###############################################################
#  Generated by:      Cadence Innovus 20.13-s083_1
#  OS:                Linux x86_64(Host ID iron-502-28)
#  Generated on:      Fri Apr 22 15:13:27 2022
#  Design:            user_proj_example
#  Command:           write_lef_abstract -specifyTopLayer 6 -PGPinLayers {5 6} -noCutObs -stripePin results/user_proj_example.lef
###############################################################

VERSION 5.8 ;

BUSBITCHARS "[]" ;
DIVIDERCHAR "/" ;

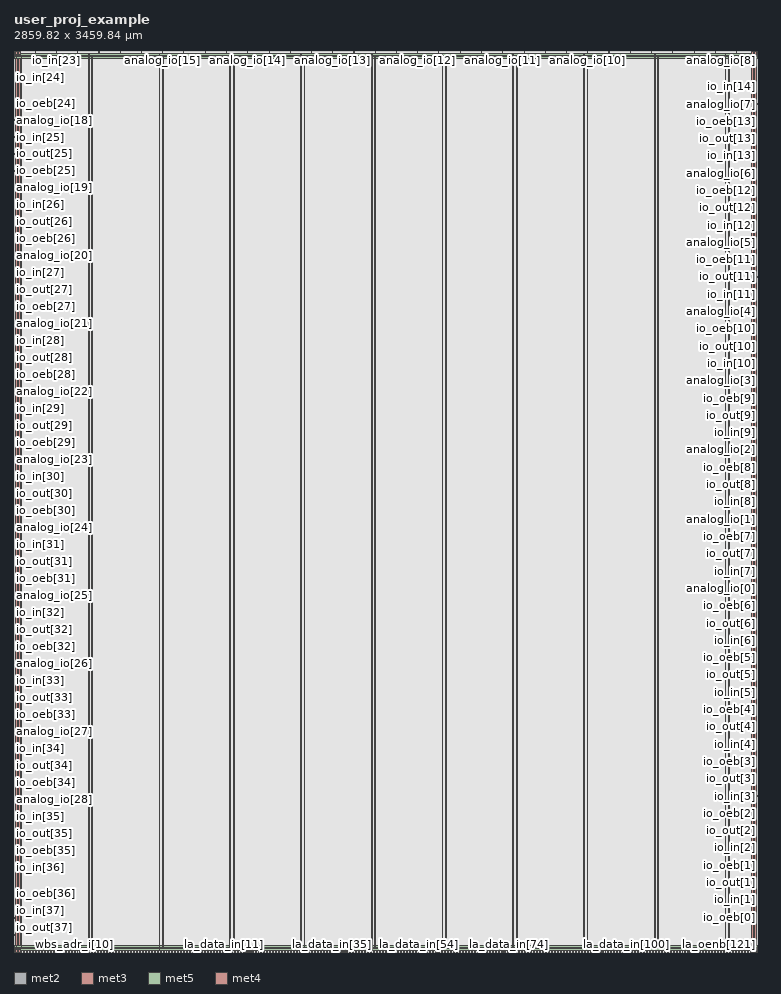
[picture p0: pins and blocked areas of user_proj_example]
MACRO user_proj_example
  CLASS BLOCK ;
  SIZE 2859.820000 BY 3459.840000 ;
  FOREIGN user_proj_example 0.000000 0.000000 ;
  ORIGIN 0 0 ;
  SYMMETRY X Y R90 ;
  PIN wb_clk_i
    DIRECTION INPUT ;
    USE SIGNAL ;
    ANTENNAPARTIALMETALAREA 4.1174 LAYER met2  ;
    ANTENNAPARTIALMETALSIDEAREA 20.426 LAYER met2  ;
    ANTENNAPARTIALCUTAREA 0.04 LAYER via2  ;
    ANTENNAPARTIALMETALAREA 8.6748 LAYER met3  ;
    ANTENNAPARTIALMETALSIDEAREA 46.736 LAYER met3  ;
    ANTENNAMODEL OXIDE1 ;
    ANTENNAGATEAREA 0.576 LAYER met3  ;
    ANTENNAMAXAREACAR 16.2276 LAYER met3  ;
    ANTENNAMAXSIDEAREACAR 83.9896 LAYER met3  ;
    ANTENNAMAXCUTCAR 0.158681 LAYER via3  ;
    PORT
      LAYER met2 ;
        RECT 0.620000 0.000000 0.760000 0.485000 ;
    END
  END wb_clk_i
  PIN wb_rst_i
    DIRECTION INPUT ;
    USE SIGNAL ;
    ANTENNAPARTIALMETALAREA 5.9323 LAYER met2  ;
    ANTENNAPARTIALMETALSIDEAREA 29.0815 LAYER met2  ;
    ANTENNAMODEL OXIDE1 ;
    ANTENNAGATEAREA 0.7425 LAYER met2  ;
    ANTENNAMAXAREACAR 10.0106 LAYER met2  ;
    ANTENNAMAXSIDEAREACAR 47.1104 LAYER met2  ;
    ANTENNAMAXCUTCAR 0.298586 LAYER via2  ;
    PORT
      LAYER met2 ;
        RECT 6.140000 0.000000 6.280000 0.485000 ;
    END
  END wb_rst_i
  PIN wbs_stb_i
    DIRECTION INPUT ;
    USE SIGNAL ;
    ANTENNAPARTIALMETALAREA 4.6987 LAYER met2  ;
    ANTENNAPARTIALMETALSIDEAREA 23.1595 LAYER met2  ;
    ANTENNAMODEL OXIDE1 ;
    ANTENNAGATEAREA 0.3735 LAYER met2  ;
    ANTENNAMAXAREACAR 17.4596 LAYER met2  ;
    ANTENNAMAXSIDEAREACAR 75.7726 LAYER met2  ;
    ANTENNAMAXCUTCAR 0.407937 LAYER via2  ;
    PORT
      LAYER met2 ;
        RECT 23.620000 0.000000 23.760000 0.485000 ;
    END
  END wbs_stb_i
  PIN wbs_cyc_i
    DIRECTION INPUT ;
    USE SIGNAL ;
    ANTENNAPARTIALMETALAREA 4.8961 LAYER met2  ;
    ANTENNAPARTIALMETALSIDEAREA 24.1465 LAYER met2  ;
    ANTENNAMODEL OXIDE1 ;
    ANTENNAGATEAREA 0.3735 LAYER met2  ;
    ANTENNAMAXAREACAR 20.2178 LAYER met2  ;
    ANTENNAMAXSIDEAREACAR 88.2643 LAYER met2  ;
    ANTENNAMAXCUTCAR 0.407937 LAYER via2  ;
    PORT
      LAYER met2 ;
        RECT 17.640000 0.000000 17.780000 0.485000 ;
    END
  END wbs_cyc_i
  PIN wbs_we_i
    DIRECTION INPUT ;
    USE SIGNAL ;
    ANTENNAPARTIALMETALAREA 5.2293 LAYER met2  ;
    ANTENNAPARTIALMETALSIDEAREA 25.8125 LAYER met2  ;
    ANTENNAMODEL OXIDE1 ;
    ANTENNAGATEAREA 0.3735 LAYER met2  ;
    ANTENNAMAXAREACAR 18.0833 LAYER met2  ;
    ANTENNAMAXSIDEAREACAR 79.3756 LAYER met2  ;
    ANTENNAMAXCUTCAR 0.407937 LAYER via2  ;
    PORT
      LAYER met2 ;
        RECT 29.600000 0.000000 29.740000 0.485000 ;
    END
  END wbs_we_i
  PIN wbs_sel_i[3]
    DIRECTION INPUT ;
    USE SIGNAL ;
    PORT
      LAYER met2 ;
        RECT 122.060000 0.000000 122.200000 0.485000 ;
    END
  END wbs_sel_i[3]
  PIN wbs_sel_i[2]
    DIRECTION INPUT ;
    USE SIGNAL ;
    PORT
      LAYER met2 ;
        RECT 99.060000 0.000000 99.200000 0.485000 ;
    END
  END wbs_sel_i[2]
  PIN wbs_sel_i[1]
    DIRECTION INPUT ;
    USE SIGNAL ;
    PORT
      LAYER met2 ;
        RECT 75.600000 0.000000 75.740000 0.485000 ;
    END
  END wbs_sel_i[1]
  PIN wbs_sel_i[0]
    DIRECTION INPUT ;
    USE SIGNAL ;
    PORT
      LAYER met2 ;
        RECT 52.600000 0.000000 52.740000 0.485000 ;
    END
  END wbs_sel_i[0]
  PIN wbs_dat_i[31]
    DIRECTION INPUT ;
    USE SIGNAL ;
    ANTENNAPARTIALMETALAREA 4.4991 LAYER met2  ;
    ANTENNAPARTIALMETALSIDEAREA 22.1515 LAYER met2  ;
    ANTENNAMODEL OXIDE1 ;
    ANTENNAGATEAREA 0.246 LAYER met2  ;
    ANTENNAMAXAREACAR 24.7075 LAYER met2  ;
    ANTENNAMAXSIDEAREACAR 120.012 LAYER met2  ;
    ANTENNAMAXCUTCAR 0.208943 LAYER via2  ;
    PORT
      LAYER met2 ;
        RECT 603.680000 0.000000 603.820000 0.485000 ;
    END
  END wbs_dat_i[31]
  PIN wbs_dat_i[30]
    DIRECTION INPUT ;
    USE SIGNAL ;
    ANTENNAPARTIALMETALAREA 5.0816 LAYER met2  ;
    ANTENNAPARTIALMETALSIDEAREA 25.102 LAYER met2  ;
    ANTENNAPARTIALCUTAREA 0.04 LAYER via2  ;
    ANTENNAPARTIALMETALAREA 2.8788 LAYER met3  ;
    ANTENNAPARTIALMETALSIDEAREA 15.824 LAYER met3  ;
    ANTENNAMODEL OXIDE1 ;
    ANTENNAGATEAREA 0.246 LAYER met3  ;
    ANTENNAMAXAREACAR 13.4085 LAYER met3  ;
    ANTENNAMAXSIDEAREACAR 69.8049 LAYER met3  ;
    ANTENNAMAXCUTCAR 0.371545 LAYER via3  ;
    PORT
      LAYER met2 ;
        RECT 586.200000 0.000000 586.340000 0.485000 ;
    END
  END wbs_dat_i[30]
  PIN wbs_dat_i[29]
    DIRECTION INPUT ;
    USE SIGNAL ;
    ANTENNAPARTIALMETALAREA 4.8799 LAYER met2  ;
    ANTENNAPARTIALMETALSIDEAREA 24.0555 LAYER met2  ;
    ANTENNAMODEL OXIDE1 ;
    ANTENNAGATEAREA 0.246 LAYER met2  ;
    ANTENNAMAXAREACAR 22.6587 LAYER met2  ;
    ANTENNAMAXSIDEAREACAR 109.768 LAYER met2  ;
    ANTENNAMAXCUTCAR 0.208943 LAYER via2  ;
    PORT
      LAYER met2 ;
        RECT 568.720000 0.000000 568.860000 0.485000 ;
    END
  END wbs_dat_i[29]
  PIN wbs_dat_i[28]
    DIRECTION INPUT ;
    USE SIGNAL ;
    ANTENNAPARTIALMETALAREA 4.9935 LAYER met2  ;
    ANTENNAPARTIALMETALSIDEAREA 24.7415 LAYER met2  ;
    ANTENNAMODEL OXIDE1 ;
    ANTENNAGATEAREA 0.246 LAYER met2  ;
    ANTENNAMAXAREACAR 21.3459 LAYER met2  ;
    ANTENNAMAXSIDEAREACAR 103.565 LAYER met2  ;
    ANTENNAMAXCUTCAR 0.208943 LAYER via2  ;
    PORT
      LAYER met2 ;
        RECT 551.240000 0.000000 551.380000 0.485000 ;
    END
  END wbs_dat_i[28]
  PIN wbs_dat_i[27]
    DIRECTION INPUT ;
    USE SIGNAL ;
    ANTENNAPARTIALMETALAREA 4.2837 LAYER met2  ;
    ANTENNAPARTIALMETALSIDEAREA 21.1925 LAYER met2  ;
    ANTENNAMODEL OXIDE1 ;
    ANTENNAGATEAREA 0.246 LAYER met2  ;
    ANTENNAMAXAREACAR 18.4606 LAYER met2  ;
    ANTENNAMAXSIDEAREACAR 89.1382 LAYER met2  ;
    ANTENNAMAXCUTCAR 0.208943 LAYER via2  ;
    PORT
      LAYER met2 ;
        RECT 533.760000 0.000000 533.900000 0.485000 ;
    END
  END wbs_dat_i[27]
  PIN wbs_dat_i[26]
    DIRECTION INPUT ;
    USE SIGNAL ;
    ANTENNAPARTIALMETALAREA 4.3271 LAYER met2  ;
    ANTENNAPARTIALMETALSIDEAREA 21.4095 LAYER met2  ;
    ANTENNAMODEL OXIDE1 ;
    ANTENNAGATEAREA 0.246 LAYER met2  ;
    ANTENNAMAXAREACAR 18.637 LAYER met2  ;
    ANTENNAMAXSIDEAREACAR 90.0203 LAYER met2  ;
    ANTENNAMAXCUTCAR 0.208943 LAYER via2  ;
    PORT
      LAYER met2 ;
        RECT 516.740000 0.000000 516.880000 0.485000 ;
    END
  END wbs_dat_i[26]
  PIN wbs_dat_i[25]
    DIRECTION INPUT ;
    USE SIGNAL ;
    ANTENNAPARTIALMETALAREA 4.1367 LAYER met2  ;
    ANTENNAPARTIALMETALSIDEAREA 20.4575 LAYER met2  ;
    ANTENNAMODEL OXIDE1 ;
    ANTENNAGATEAREA 0.246 LAYER met2  ;
    ANTENNAMAXAREACAR 17.863 LAYER met2  ;
    ANTENNAMAXSIDEAREACAR 86.1504 LAYER met2  ;
    ANTENNAMAXCUTCAR 0.208943 LAYER via2  ;
    PORT
      LAYER met2 ;
        RECT 499.260000 0.000000 499.400000 0.485000 ;
    END
  END wbs_dat_i[25]
  PIN wbs_dat_i[24]
    DIRECTION INPUT ;
    USE SIGNAL ;
    ANTENNAPARTIALMETALAREA 4.2319 LAYER met2  ;
    ANTENNAPARTIALMETALSIDEAREA 20.9335 LAYER met2  ;
    ANTENNAMODEL OXIDE1 ;
    ANTENNAGATEAREA 0.246 LAYER met2  ;
    ANTENNAMAXAREACAR 18.25 LAYER met2  ;
    ANTENNAMAXSIDEAREACAR 88.0854 LAYER met2  ;
    ANTENNAMAXCUTCAR 0.208943 LAYER via2  ;
    PORT
      LAYER met2 ;
        RECT 481.780000 0.000000 481.920000 0.485000 ;
    END
  END wbs_dat_i[24]
  PIN wbs_dat_i[23]
    DIRECTION INPUT ;
    USE SIGNAL ;
    ANTENNAPARTIALMETALAREA 4.4769 LAYER met2  ;
    ANTENNAPARTIALMETALSIDEAREA 22.1585 LAYER met2  ;
    ANTENNAMODEL OXIDE1 ;
    ANTENNAGATEAREA 0.246 LAYER met2  ;
    ANTENNAMAXAREACAR 19.2459 LAYER met2  ;
    ANTENNAMAXSIDEAREACAR 93.065 LAYER met2  ;
    ANTENNAMAXCUTCAR 0.208943 LAYER via2  ;
    PORT
      LAYER met2 ;
        RECT 464.300000 0.000000 464.440000 0.485000 ;
    END
  END wbs_dat_i[23]
  PIN wbs_dat_i[22]
    DIRECTION INPUT ;
    USE SIGNAL ;
    ANTENNAPARTIALMETALAREA 4.2319 LAYER met2  ;
    ANTENNAPARTIALMETALSIDEAREA 20.9335 LAYER met2  ;
    ANTENNAMODEL OXIDE1 ;
    ANTENNAGATEAREA 0.246 LAYER met2  ;
    ANTENNAMAXAREACAR 18.25 LAYER met2  ;
    ANTENNAMAXSIDEAREACAR 88.0854 LAYER met2  ;
    ANTENNAMAXCUTCAR 0.208943 LAYER via2  ;
    PORT
      LAYER met2 ;
        RECT 446.820000 0.000000 446.960000 0.485000 ;
    END
  END wbs_dat_i[22]
  PIN wbs_dat_i[21]
    DIRECTION INPUT ;
    USE SIGNAL ;
    ANTENNAPARTIALMETALAREA 4.3481 LAYER met2  ;
    ANTENNAPARTIALMETALSIDEAREA 21.5145 LAYER met2  ;
    ANTENNAMODEL OXIDE1 ;
    ANTENNAGATEAREA 0.246 LAYER met2  ;
    ANTENNAMAXAREACAR 18.7224 LAYER met2  ;
    ANTENNAMAXSIDEAREACAR 90.4472 LAYER met2  ;
    ANTENNAMAXCUTCAR 0.208943 LAYER via2  ;
    PORT
      LAYER met2 ;
        RECT 429.800000 0.000000 429.940000 0.485000 ;
    END
  END wbs_dat_i[21]
  PIN wbs_dat_i[20]
    DIRECTION INPUT ;
    USE SIGNAL ;
    ANTENNAPARTIALMETALAREA 4.5987 LAYER met2  ;
    ANTENNAPARTIALMETALSIDEAREA 22.7675 LAYER met2  ;
    ANTENNAMODEL OXIDE1 ;
    ANTENNAGATEAREA 0.246 LAYER met2  ;
    ANTENNAMAXAREACAR 20.9238 LAYER met2  ;
    ANTENNAMAXSIDEAREACAR 101.573 LAYER met2  ;
    ANTENNAMAXCUTCAR 0.208943 LAYER via2  ;
    PORT
      LAYER met2 ;
        RECT 412.320000 0.000000 412.460000 0.485000 ;
    END
  END wbs_dat_i[20]
  PIN wbs_dat_i[19]
    DIRECTION INPUT ;
    USE SIGNAL ;
    ANTENNAPARTIALMETALAREA 4.2795 LAYER met2  ;
    ANTENNAPARTIALMETALSIDEAREA 21.1715 LAYER met2  ;
    ANTENNAMODEL OXIDE1 ;
    ANTENNAGATEAREA 0.246 LAYER met2  ;
    ANTENNAMAXAREACAR 18.4435 LAYER met2  ;
    ANTENNAMAXSIDEAREACAR 89.0528 LAYER met2  ;
    ANTENNAMAXCUTCAR 0.208943 LAYER via2  ;
    PORT
      LAYER met2 ;
        RECT 394.840000 0.000000 394.980000 0.485000 ;
    END
  END wbs_dat_i[19]
  PIN wbs_dat_i[18]
    DIRECTION INPUT ;
    USE SIGNAL ;
    ANTENNAPARTIALMETALAREA 4.4293 LAYER met2  ;
    ANTENNAPARTIALMETALSIDEAREA 21.9205 LAYER met2  ;
    ANTENNAMODEL OXIDE1 ;
    ANTENNAGATEAREA 0.246 LAYER met2  ;
    ANTENNAMAXAREACAR 19.0524 LAYER met2  ;
    ANTENNAMAXSIDEAREACAR 92.0976 LAYER met2  ;
    ANTENNAMAXCUTCAR 0.208943 LAYER via2  ;
    PORT
      LAYER met2 ;
        RECT 377.360000 0.000000 377.500000 0.485000 ;
    END
  END wbs_dat_i[18]
  PIN wbs_dat_i[17]
    DIRECTION INPUT ;
    USE SIGNAL ;
    ANTENNAPARTIALMETALAREA 5.2385 LAYER met2  ;
    ANTENNAPARTIALMETALSIDEAREA 25.9665 LAYER met2  ;
    ANTENNAMODEL OXIDE1 ;
    ANTENNAGATEAREA 0.246 LAYER met2  ;
    ANTENNAMAXAREACAR 22.3419 LAYER met2  ;
    ANTENNAMAXSIDEAREACAR 108.545 LAYER met2  ;
    ANTENNAMAXCUTCAR 0.208943 LAYER via2  ;
    PORT
      LAYER met2 ;
        RECT 359.880000 0.000000 360.020000 0.485000 ;
    END
  END wbs_dat_i[17]
  PIN wbs_dat_i[16]
    DIRECTION INPUT ;
    USE SIGNAL ;
    ANTENNAPARTIALMETALAREA 4.3649 LAYER met2  ;
    ANTENNAPARTIALMETALSIDEAREA 21.5985 LAYER met2  ;
    ANTENNAMODEL OXIDE1 ;
    ANTENNAGATEAREA 0.246 LAYER met2  ;
    ANTENNAMAXAREACAR 18.7907 LAYER met2  ;
    ANTENNAMAXSIDEAREACAR 90.7886 LAYER met2  ;
    ANTENNAMAXCUTCAR 0.208943 LAYER via2  ;
    PORT
      LAYER met2 ;
        RECT 342.400000 0.000000 342.540000 0.485000 ;
    END
  END wbs_dat_i[16]
  PIN wbs_dat_i[15]
    DIRECTION INPUT ;
    USE SIGNAL ;
    ANTENNAPARTIALMETALAREA 5.3984 LAYER met2  ;
    ANTENNAPARTIALMETALSIDEAREA 26.831 LAYER met2  ;
    ANTENNAPARTIALCUTAREA 0.04 LAYER via2  ;
    ANTENNAPARTIALMETALAREA 15.028 LAYER met3  ;
    ANTENNAPARTIALMETALSIDEAREA 80.616 LAYER met3  ;
    ANTENNAPARTIALCUTAREA 0.04 LAYER via3  ;
    ANTENNAPARTIALMETALAREA 0.6516 LAYER met4  ;
    ANTENNAPARTIALMETALSIDEAREA 4.416 LAYER met4  ;
    ANTENNAMODEL OXIDE1 ;
    ANTENNAGATEAREA 0.2475 LAYER met4  ;
    ANTENNAMAXAREACAR 6.16909 LAYER met4  ;
    ANTENNAMAXSIDEAREACAR 35.2768 LAYER met4  ;
    ANTENNAMAXCUTCAR 0.530909 LAYER via4  ;
    PORT
      LAYER met2 ;
        RECT 325.380000 0.000000 325.520000 0.485000 ;
    END
  END wbs_dat_i[15]
  PIN wbs_dat_i[14]
    DIRECTION INPUT ;
    USE SIGNAL ;
    ANTENNAPARTIALMETALAREA 5.5717 LAYER met2  ;
    ANTENNAPARTIALMETALSIDEAREA 27.6325 LAYER met2  ;
    ANTENNAMODEL OXIDE1 ;
    ANTENNAGATEAREA 0.2475 LAYER met2  ;
    ANTENNAMAXAREACAR 26.2616 LAYER met2  ;
    ANTENNAMAXSIDEAREACAR 128.133 LAYER met2  ;
    ANTENNAMAXCUTCAR 0.207677 LAYER via2  ;
    PORT
      LAYER met2 ;
        RECT 307.900000 0.000000 308.040000 0.485000 ;
    END
  END wbs_dat_i[14]
  PIN wbs_dat_i[13]
    DIRECTION INPUT ;
    USE SIGNAL ;
    ANTENNAPARTIALMETALAREA 5.8027 LAYER met2  ;
    ANTENNAPARTIALMETALSIDEAREA 28.7875 LAYER met2  ;
    ANTENNAMODEL OXIDE1 ;
    ANTENNAGATEAREA 0.2475 LAYER met2  ;
    ANTENNAMAXAREACAR 24.4422 LAYER met2  ;
    ANTENNAMAXSIDEAREACAR 119.309 LAYER met2  ;
    ANTENNAMAXCUTCAR 0.207677 LAYER via2  ;
    PORT
      LAYER met2 ;
        RECT 290.420000 0.000000 290.560000 0.485000 ;
    END
  END wbs_dat_i[13]
  PIN wbs_dat_i[12]
    DIRECTION INPUT ;
    USE SIGNAL ;
    ANTENNAPARTIALMETALAREA 1.3846 LAYER met2  ;
    ANTENNAPARTIALMETALSIDEAREA 6.762 LAYER met2  ;
    ANTENNAPARTIALCUTAREA 0.04 LAYER via2  ;
    ANTENNAPARTIALMETALAREA 3.7068 LAYER met3  ;
    ANTENNAPARTIALMETALSIDEAREA 20.24 LAYER met3  ;
    ANTENNAMODEL OXIDE1 ;
    ANTENNAGATEAREA 0.2475 LAYER met3  ;
    ANTENNAMAXAREACAR 32.7715 LAYER met3  ;
    ANTENNAMAXSIDEAREACAR 167.798 LAYER met3  ;
    ANTENNAMAXCUTCAR 0.369293 LAYER via3  ;
    PORT
      LAYER met2 ;
        RECT 272.940000 0.000000 273.080000 0.485000 ;
    END
  END wbs_dat_i[12]
  PIN wbs_dat_i[11]
    DIRECTION INPUT ;
    USE SIGNAL ;
    ANTENNAPARTIALMETALAREA 5.4767 LAYER met2  ;
    ANTENNAPARTIALMETALSIDEAREA 27.2755 LAYER met2  ;
    ANTENNAMODEL OXIDE1 ;
    ANTENNAGATEAREA 0.2475 LAYER met2  ;
    ANTENNAMAXAREACAR 23.5869 LAYER met2  ;
    ANTENNAMAXSIDEAREACAR 115.236 LAYER met2  ;
    ANTENNAMAXCUTCAR 0.207677 LAYER via2  ;
    PORT
      LAYER met2 ;
        RECT 255.460000 0.000000 255.600000 0.485000 ;
    END
  END wbs_dat_i[11]
  PIN wbs_dat_i[10]
    DIRECTION INPUT ;
    USE SIGNAL ;
    ANTENNAPARTIALMETALAREA 4.5863 LAYER met2  ;
    ANTENNAPARTIALMETALSIDEAREA 22.8235 LAYER met2  ;
    ANTENNAMODEL OXIDE1 ;
    ANTENNAGATEAREA 0.2475 LAYER met2  ;
    ANTENNAMAXAREACAR 19.5275 LAYER met2  ;
    ANTENNAMAXSIDEAREACAR 95.2121 LAYER met2  ;
    ANTENNAMAXCUTCAR 0.207677 LAYER via2  ;
    PORT
      LAYER met2 ;
        RECT 237.980000 0.000000 238.120000 0.485000 ;
    END
  END wbs_dat_i[10]
  PIN wbs_dat_i[9]
    DIRECTION INPUT ;
    USE SIGNAL ;
    ANTENNAPARTIALMETALAREA 5.4459 LAYER met2  ;
    ANTENNAPARTIALMETALSIDEAREA 27.1215 LAYER met2  ;
    ANTENNAMODEL OXIDE1 ;
    ANTENNAGATEAREA 0.2475 LAYER met2  ;
    ANTENNAMAXAREACAR 28.0103 LAYER met2  ;
    ANTENNAMAXSIDEAREACAR 137.354 LAYER met2  ;
    ANTENNAMAXCUTCAR 0.207677 LAYER via2  ;
    PORT
      LAYER met2 ;
        RECT 220.960000 0.000000 221.100000 0.485000 ;
    END
  END wbs_dat_i[9]
  PIN wbs_dat_i[8]
    DIRECTION INPUT ;
    USE SIGNAL ;
    ANTENNAPARTIALMETALAREA 5.8237 LAYER met2  ;
    ANTENNAPARTIALMETALSIDEAREA 28.8925 LAYER met2  ;
    ANTENNAMODEL OXIDE1 ;
    ANTENNAGATEAREA 0.2475 LAYER met2  ;
    ANTENNAMAXAREACAR 30.5097 LAYER met2  ;
    ANTENNAMAXSIDEAREACAR 149.374 LAYER met2  ;
    ANTENNAMAXCUTCAR 0.207677 LAYER via2  ;
    PORT
      LAYER met2 ;
        RECT 203.480000 0.000000 203.620000 0.485000 ;
    END
  END wbs_dat_i[8]
  PIN wbs_dat_i[7]
    DIRECTION INPUT ;
    USE SIGNAL ;
    ANTENNAPARTIALMETALAREA 6.432 LAYER met2  ;
    ANTENNAPARTIALMETALSIDEAREA 31.934 LAYER met2  ;
    ANTENNAMODEL OXIDE1 ;
    ANTENNAGATEAREA 0.2475 LAYER met2  ;
    ANTENNAMAXAREACAR 27.9105 LAYER met2  ;
    ANTENNAMAXSIDEAREACAR 136.378 LAYER met2  ;
    ANTENNAMAXCUTCAR 0.207677 LAYER via2  ;
    PORT
      LAYER met2 ;
        RECT 186.000000 0.000000 186.140000 0.485000 ;
    END
  END wbs_dat_i[7]
  PIN wbs_dat_i[6]
    DIRECTION INPUT ;
    USE SIGNAL ;
    ANTENNAPARTIALMETALAREA 5.7551 LAYER met2  ;
    ANTENNAPARTIALMETALSIDEAREA 28.5495 LAYER met2  ;
    ANTENNAMODEL OXIDE1 ;
    ANTENNAGATEAREA 0.2475 LAYER met2  ;
    ANTENNAMAXAREACAR 26.4653 LAYER met2  ;
    ANTENNAMAXSIDEAREACAR 129.152 LAYER met2  ;
    ANTENNAMAXCUTCAR 0.207677 LAYER via2  ;
    PORT
      LAYER met2 ;
        RECT 168.520000 0.000000 168.660000 0.485000 ;
    END
  END wbs_dat_i[6]
  PIN wbs_dat_i[5]
    DIRECTION INPUT ;
    USE SIGNAL ;
    ANTENNAPARTIALMETALAREA 5.7957 LAYER met2  ;
    ANTENNAPARTIALMETALSIDEAREA 28.7525 LAYER met2  ;
    ANTENNAMODEL OXIDE1 ;
    ANTENNAGATEAREA 0.2475 LAYER met2  ;
    ANTENNAMAXAREACAR 24.4139 LAYER met2  ;
    ANTENNAMAXSIDEAREACAR 119.168 LAYER met2  ;
    ANTENNAMAXCUTCAR 0.207677 LAYER via2  ;
    PORT
      LAYER met2 ;
        RECT 151.040000 0.000000 151.180000 0.485000 ;
    END
  END wbs_dat_i[5]
  PIN wbs_dat_i[4]
    DIRECTION INPUT ;
    USE SIGNAL ;
    ANTENNAPARTIALMETALAREA 4.7079 LAYER met2  ;
    ANTENNAPARTIALMETALSIDEAREA 23.3135 LAYER met2  ;
    ANTENNAMODEL OXIDE1 ;
    ANTENNAGATEAREA 0.2475 LAYER met2  ;
    ANTENNAMAXAREACAR 20.2204 LAYER met2  ;
    ANTENNAMAXSIDEAREACAR 97.9273 LAYER met2  ;
    ANTENNAMAXCUTCAR 0.207677 LAYER via2  ;
    PORT
      LAYER met2 ;
        RECT 133.560000 0.000000 133.700000 0.485000 ;
    END
  END wbs_dat_i[4]
  PIN wbs_dat_i[3]
    DIRECTION INPUT ;
    USE SIGNAL ;
    ANTENNAPARTIALMETALAREA 3.115 LAYER met2  ;
    ANTENNAPARTIALMETALSIDEAREA 15.414 LAYER met2  ;
    ANTENNAPARTIALCUTAREA 0.04 LAYER via2  ;
    ANTENNAPARTIALMETALAREA 22.618 LAYER met3  ;
    ANTENNAPARTIALMETALSIDEAREA 121.096 LAYER met3  ;
    ANTENNAPARTIALCUTAREA 0.04 LAYER via3  ;
    ANTENNAPARTIALMETALAREA 5.2428 LAYER met4  ;
    ANTENNAPARTIALMETALSIDEAREA 28.432 LAYER met4  ;
    ANTENNAMODEL OXIDE1 ;
    ANTENNAGATEAREA 0.2475 LAYER met4  ;
    ANTENNAMAXAREACAR 24.6051 LAYER met4  ;
    ANTENNAMAXSIDEAREACAR 131.192 LAYER met4  ;
    ANTENNAMAXCUTCAR 0.530909 LAYER via4  ;
    PORT
      LAYER met2 ;
        RECT 110.560000 0.000000 110.700000 0.485000 ;
    END
  END wbs_dat_i[3]
  PIN wbs_dat_i[2]
    DIRECTION INPUT ;
    USE SIGNAL ;
    ANTENNAPARTIALMETALAREA 5.3003 LAYER met2  ;
    ANTENNAPARTIALMETALSIDEAREA 26.3935 LAYER met2  ;
    ANTENNAMODEL OXIDE1 ;
    ANTENNAGATEAREA 0.2475 LAYER met2  ;
    ANTENNAMAXAREACAR 67.9626 LAYER met2  ;
    ANTENNAMAXSIDEAREACAR 337.115 LAYER met2  ;
    ANTENNAMAXCUTCAR 0.207677 LAYER via2  ;
    PORT
      LAYER met2 ;
        RECT 87.560000 0.000000 87.700000 0.485000 ;
    END
  END wbs_dat_i[2]
  PIN wbs_dat_i[1]
    DIRECTION INPUT ;
    USE SIGNAL ;
    ANTENNAPARTIALMETALAREA 4.6603 LAYER met2  ;
    ANTENNAPARTIALMETALSIDEAREA 23.0755 LAYER met2  ;
    ANTENNAMODEL OXIDE1 ;
    ANTENNAGATEAREA 0.2475 LAYER met2  ;
    ANTENNAMAXAREACAR 20.2883 LAYER met2  ;
    ANTENNAMAXSIDEAREACAR 98.2667 LAYER met2  ;
    ANTENNAMAXCUTCAR 0.207677 LAYER via2  ;
    PORT
      LAYER met2 ;
        RECT 64.100000 0.000000 64.240000 0.485000 ;
    END
  END wbs_dat_i[1]
  PIN wbs_dat_i[0]
    DIRECTION INPUT ;
    USE SIGNAL ;
    ANTENNAPARTIALMETALAREA 4.5651 LAYER met2  ;
    ANTENNAPARTIALMETALSIDEAREA 22.5995 LAYER met2  ;
    ANTENNAMODEL OXIDE1 ;
    ANTENNAGATEAREA 0.2475 LAYER met2  ;
    ANTENNAMAXAREACAR 24.3271 LAYER met2  ;
    ANTENNAMAXSIDEAREACAR 118.461 LAYER met2  ;
    ANTENNAMAXCUTCAR 0.207677 LAYER via2  ;
    PORT
      LAYER met2 ;
        RECT 41.100000 0.000000 41.240000 0.485000 ;
    END
  END wbs_dat_i[0]
  PIN wbs_adr_i[31]
    DIRECTION INPUT ;
    USE SIGNAL ;
    PORT
      LAYER met2 ;
        RECT 597.700000 0.000000 597.840000 0.485000 ;
    END
  END wbs_adr_i[31]
  PIN wbs_adr_i[30]
    DIRECTION INPUT ;
    USE SIGNAL ;
    PORT
      LAYER met2 ;
        RECT 580.220000 0.000000 580.360000 0.485000 ;
    END
  END wbs_adr_i[30]
  PIN wbs_adr_i[29]
    DIRECTION INPUT ;
    USE SIGNAL ;
    PORT
      LAYER met2 ;
        RECT 563.200000 0.000000 563.340000 0.485000 ;
    END
  END wbs_adr_i[29]
  PIN wbs_adr_i[28]
    DIRECTION INPUT ;
    USE SIGNAL ;
    PORT
      LAYER met2 ;
        RECT 545.720000 0.000000 545.860000 0.485000 ;
    END
  END wbs_adr_i[28]
  PIN wbs_adr_i[27]
    DIRECTION INPUT ;
    USE SIGNAL ;
    PORT
      LAYER met2 ;
        RECT 528.240000 0.000000 528.380000 0.485000 ;
    END
  END wbs_adr_i[27]
  PIN wbs_adr_i[26]
    DIRECTION INPUT ;
    USE SIGNAL ;
    PORT
      LAYER met2 ;
        RECT 510.760000 0.000000 510.900000 0.485000 ;
    END
  END wbs_adr_i[26]
  PIN wbs_adr_i[25]
    DIRECTION INPUT ;
    USE SIGNAL ;
    PORT
      LAYER met2 ;
        RECT 493.280000 0.000000 493.420000 0.485000 ;
    END
  END wbs_adr_i[25]
  PIN wbs_adr_i[24]
    DIRECTION INPUT ;
    USE SIGNAL ;
    PORT
      LAYER met2 ;
        RECT 475.800000 0.000000 475.940000 0.485000 ;
    END
  END wbs_adr_i[24]
  PIN wbs_adr_i[23]
    DIRECTION INPUT ;
    USE SIGNAL ;
    PORT
      LAYER met2 ;
        RECT 458.780000 0.000000 458.920000 0.485000 ;
    END
  END wbs_adr_i[23]
  PIN wbs_adr_i[22]
    DIRECTION INPUT ;
    USE SIGNAL ;
    PORT
      LAYER met2 ;
        RECT 441.300000 0.000000 441.440000 0.485000 ;
    END
  END wbs_adr_i[22]
  PIN wbs_adr_i[21]
    DIRECTION INPUT ;
    USE SIGNAL ;
    PORT
      LAYER met2 ;
        RECT 423.820000 0.000000 423.960000 0.485000 ;
    END
  END wbs_adr_i[21]
  PIN wbs_adr_i[20]
    DIRECTION INPUT ;
    USE SIGNAL ;
    PORT
      LAYER met2 ;
        RECT 406.340000 0.000000 406.480000 0.485000 ;
    END
  END wbs_adr_i[20]
  PIN wbs_adr_i[19]
    DIRECTION INPUT ;
    USE SIGNAL ;
    PORT
      LAYER met2 ;
        RECT 388.860000 0.000000 389.000000 0.485000 ;
    END
  END wbs_adr_i[19]
  PIN wbs_adr_i[18]
    DIRECTION INPUT ;
    USE SIGNAL ;
    PORT
      LAYER met2 ;
        RECT 371.380000 0.000000 371.520000 0.485000 ;
    END
  END wbs_adr_i[18]
  PIN wbs_adr_i[17]
    DIRECTION INPUT ;
    USE SIGNAL ;
    PORT
      LAYER met2 ;
        RECT 354.360000 0.000000 354.500000 0.485000 ;
    END
  END wbs_adr_i[17]
  PIN wbs_adr_i[16]
    DIRECTION INPUT ;
    USE SIGNAL ;
    PORT
      LAYER met2 ;
        RECT 336.880000 0.000000 337.020000 0.485000 ;
    END
  END wbs_adr_i[16]
  PIN wbs_adr_i[15]
    DIRECTION INPUT ;
    USE SIGNAL ;
    PORT
      LAYER met2 ;
        RECT 319.400000 0.000000 319.540000 0.485000 ;
    END
  END wbs_adr_i[15]
  PIN wbs_adr_i[14]
    DIRECTION INPUT ;
    USE SIGNAL ;
    PORT
      LAYER met2 ;
        RECT 301.920000 0.000000 302.060000 0.485000 ;
    END
  END wbs_adr_i[14]
  PIN wbs_adr_i[13]
    DIRECTION INPUT ;
    USE SIGNAL ;
    PORT
      LAYER met2 ;
        RECT 284.440000 0.000000 284.580000 0.485000 ;
    END
  END wbs_adr_i[13]
  PIN wbs_adr_i[12]
    DIRECTION INPUT ;
    USE SIGNAL ;
    PORT
      LAYER met2 ;
        RECT 266.960000 0.000000 267.100000 0.485000 ;
    END
  END wbs_adr_i[12]
  PIN wbs_adr_i[11]
    DIRECTION INPUT ;
    USE SIGNAL ;
    PORT
      LAYER met2 ;
        RECT 249.940000 0.000000 250.080000 0.485000 ;
    END
  END wbs_adr_i[11]
  PIN wbs_adr_i[10]
    DIRECTION INPUT ;
    USE SIGNAL ;
    PORT
      LAYER met2 ;
        RECT 232.460000 0.000000 232.600000 0.485000 ;
    END
  END wbs_adr_i[10]
  PIN wbs_adr_i[9]
    DIRECTION INPUT ;
    USE SIGNAL ;
    PORT
      LAYER met2 ;
        RECT 214.980000 0.000000 215.120000 0.485000 ;
    END
  END wbs_adr_i[9]
  PIN wbs_adr_i[8]
    DIRECTION INPUT ;
    USE SIGNAL ;
    PORT
      LAYER met2 ;
        RECT 197.500000 0.000000 197.640000 0.485000 ;
    END
  END wbs_adr_i[8]
  PIN wbs_adr_i[7]
    DIRECTION INPUT ;
    USE SIGNAL ;
    PORT
      LAYER met2 ;
        RECT 180.020000 0.000000 180.160000 0.485000 ;
    END
  END wbs_adr_i[7]
  PIN wbs_adr_i[6]
    DIRECTION INPUT ;
    USE SIGNAL ;
    PORT
      LAYER met2 ;
        RECT 163.000000 0.000000 163.140000 0.485000 ;
    END
  END wbs_adr_i[6]
  PIN wbs_adr_i[5]
    DIRECTION INPUT ;
    USE SIGNAL ;
    PORT
      LAYER met2 ;
        RECT 145.520000 0.000000 145.660000 0.485000 ;
    END
  END wbs_adr_i[5]
  PIN wbs_adr_i[4]
    DIRECTION INPUT ;
    USE SIGNAL ;
    PORT
      LAYER met2 ;
        RECT 128.040000 0.000000 128.180000 0.485000 ;
    END
  END wbs_adr_i[4]
  PIN wbs_adr_i[3]
    DIRECTION INPUT ;
    USE SIGNAL ;
    PORT
      LAYER met2 ;
        RECT 104.580000 0.000000 104.720000 0.485000 ;
    END
  END wbs_adr_i[3]
  PIN wbs_adr_i[2]
    DIRECTION INPUT ;
    USE SIGNAL ;
    PORT
      LAYER met2 ;
        RECT 81.580000 0.000000 81.720000 0.485000 ;
    END
  END wbs_adr_i[2]
  PIN wbs_adr_i[1]
    DIRECTION INPUT ;
    USE SIGNAL ;
    PORT
      LAYER met2 ;
        RECT 58.580000 0.000000 58.720000 0.485000 ;
    END
  END wbs_adr_i[1]
  PIN wbs_adr_i[0]
    DIRECTION INPUT ;
    USE SIGNAL ;
    PORT
      LAYER met2 ;
        RECT 35.120000 0.000000 35.260000 0.485000 ;
    END
  END wbs_adr_i[0]
  PIN wbs_ack_o
    DIRECTION OUTPUT ;
    USE SIGNAL ;
    ANTENNADIFFAREA 0.429 LAYER met2  ;
    ANTENNAPARTIALMETALAREA 4.5651 LAYER met2  ;
    ANTENNAPARTIALMETALSIDEAREA 22.5995 LAYER met2  ;
    PORT
      LAYER met2 ;
        RECT 12.120000 0.000000 12.260000 0.485000 ;
    END
  END wbs_ack_o
  PIN wbs_dat_o[31]
    DIRECTION OUTPUT ;
    USE SIGNAL ;
    ANTENNADIFFAREA 0.336 LAYER met2  ;
    ANTENNAPARTIALMETALAREA 4.0627 LAYER met2  ;
    ANTENNAPARTIALMETALSIDEAREA 20.2055 LAYER met2  ;
    PORT
      LAYER met2 ;
        RECT 609.200000 0.000000 609.340000 0.485000 ;
    END
  END wbs_dat_o[31]
  PIN wbs_dat_o[30]
    DIRECTION OUTPUT ;
    USE SIGNAL ;
    ANTENNADIFFAREA 0.336 LAYER met2  ;
    ANTENNAPARTIALMETALAREA 4.0627 LAYER met2  ;
    ANTENNAPARTIALMETALSIDEAREA 20.2055 LAYER met2  ;
    PORT
      LAYER met2 ;
        RECT 592.180000 0.000000 592.320000 0.485000 ;
    END
  END wbs_dat_o[30]
  PIN wbs_dat_o[29]
    DIRECTION OUTPUT ;
    USE SIGNAL ;
    ANTENNADIFFAREA 0.336 LAYER met2  ;
    ANTENNAPARTIALMETALAREA 4.0627 LAYER met2  ;
    ANTENNAPARTIALMETALSIDEAREA 20.2055 LAYER met2  ;
    PORT
      LAYER met2 ;
        RECT 574.700000 0.000000 574.840000 0.485000 ;
    END
  END wbs_dat_o[29]
  PIN wbs_dat_o[28]
    DIRECTION OUTPUT ;
    USE SIGNAL ;
    ANTENNADIFFAREA 0.336 LAYER met2  ;
    ANTENNAPARTIALMETALAREA 4.0627 LAYER met2  ;
    ANTENNAPARTIALMETALSIDEAREA 20.2055 LAYER met2  ;
    PORT
      LAYER met2 ;
        RECT 557.220000 0.000000 557.360000 0.485000 ;
    END
  END wbs_dat_o[28]
  PIN wbs_dat_o[27]
    DIRECTION OUTPUT ;
    USE SIGNAL ;
    ANTENNADIFFAREA 0.336 LAYER met2  ;
    ANTENNAPARTIALMETALAREA 4.0627 LAYER met2  ;
    ANTENNAPARTIALMETALSIDEAREA 20.2055 LAYER met2  ;
    PORT
      LAYER met2 ;
        RECT 539.740000 0.000000 539.880000 0.485000 ;
    END
  END wbs_dat_o[27]
  PIN wbs_dat_o[26]
    DIRECTION OUTPUT ;
    USE SIGNAL ;
    ANTENNADIFFAREA 0.336 LAYER met2  ;
    ANTENNAPARTIALMETALAREA 4.0627 LAYER met2  ;
    ANTENNAPARTIALMETALSIDEAREA 20.2055 LAYER met2  ;
    PORT
      LAYER met2 ;
        RECT 522.260000 0.000000 522.400000 0.485000 ;
    END
  END wbs_dat_o[26]
  PIN wbs_dat_o[25]
    DIRECTION OUTPUT ;
    USE SIGNAL ;
    ANTENNADIFFAREA 0.336 LAYER met2  ;
    ANTENNAPARTIALMETALAREA 4.4435 LAYER met2  ;
    ANTENNAPARTIALMETALSIDEAREA 22.1095 LAYER met2  ;
    PORT
      LAYER met2 ;
        RECT 504.780000 0.000000 504.920000 0.485000 ;
    END
  END wbs_dat_o[25]
  PIN wbs_dat_o[24]
    DIRECTION OUTPUT ;
    USE SIGNAL ;
    ANTENNADIFFAREA 0.336 LAYER met2  ;
    ANTENNAPARTIALMETALAREA 4.0627 LAYER met2  ;
    ANTENNAPARTIALMETALSIDEAREA 20.2055 LAYER met2  ;
    PORT
      LAYER met2 ;
        RECT 487.760000 0.000000 487.900000 0.485000 ;
    END
  END wbs_dat_o[24]
  PIN wbs_dat_o[23]
    DIRECTION OUTPUT ;
    USE SIGNAL ;
    ANTENNADIFFAREA 0.336 LAYER met2  ;
    ANTENNAPARTIALMETALAREA 4.0627 LAYER met2  ;
    ANTENNAPARTIALMETALSIDEAREA 20.2055 LAYER met2  ;
    PORT
      LAYER met2 ;
        RECT 470.280000 0.000000 470.420000 0.485000 ;
    END
  END wbs_dat_o[23]
  PIN wbs_dat_o[22]
    DIRECTION OUTPUT ;
    USE SIGNAL ;
    ANTENNADIFFAREA 0.336 LAYER met2  ;
    ANTENNAPARTIALMETALAREA 4.4435 LAYER met2  ;
    ANTENNAPARTIALMETALSIDEAREA 22.1095 LAYER met2  ;
    PORT
      LAYER met2 ;
        RECT 452.800000 0.000000 452.940000 0.485000 ;
    END
  END wbs_dat_o[22]
  PIN wbs_dat_o[21]
    DIRECTION OUTPUT ;
    USE SIGNAL ;
    ANTENNADIFFAREA 0.336 LAYER met2  ;
    ANTENNAPARTIALMETALAREA 4.0627 LAYER met2  ;
    ANTENNAPARTIALMETALSIDEAREA 20.2055 LAYER met2  ;
    PORT
      LAYER met2 ;
        RECT 435.320000 0.000000 435.460000 0.485000 ;
    END
  END wbs_dat_o[21]
  PIN wbs_dat_o[20]
    DIRECTION OUTPUT ;
    USE SIGNAL ;
    ANTENNADIFFAREA 0.336 LAYER met2  ;
    ANTENNAPARTIALMETALAREA 4.0627 LAYER met2  ;
    ANTENNAPARTIALMETALSIDEAREA 20.2055 LAYER met2  ;
    PORT
      LAYER met2 ;
        RECT 417.840000 0.000000 417.980000 0.485000 ;
    END
  END wbs_dat_o[20]
  PIN wbs_dat_o[19]
    DIRECTION OUTPUT ;
    USE SIGNAL ;
    ANTENNADIFFAREA 0.336 LAYER met2  ;
    ANTENNAPARTIALMETALAREA 4.0627 LAYER met2  ;
    ANTENNAPARTIALMETALSIDEAREA 20.2055 LAYER met2  ;
    PORT
      LAYER met2 ;
        RECT 400.360000 0.000000 400.500000 0.485000 ;
    END
  END wbs_dat_o[19]
  PIN wbs_dat_o[18]
    DIRECTION OUTPUT ;
    USE SIGNAL ;
    ANTENNADIFFAREA 0.336 LAYER met2  ;
    ANTENNAPARTIALMETALAREA 4.0627 LAYER met2  ;
    ANTENNAPARTIALMETALSIDEAREA 20.2055 LAYER met2  ;
    PORT
      LAYER met2 ;
        RECT 383.340000 0.000000 383.480000 0.485000 ;
    END
  END wbs_dat_o[18]
  PIN wbs_dat_o[17]
    DIRECTION OUTPUT ;
    USE SIGNAL ;
    ANTENNADIFFAREA 0.336 LAYER met2  ;
    ANTENNAPARTIALMETALAREA 4.0627 LAYER met2  ;
    ANTENNAPARTIALMETALSIDEAREA 20.2055 LAYER met2  ;
    PORT
      LAYER met2 ;
        RECT 365.860000 0.000000 366.000000 0.485000 ;
    END
  END wbs_dat_o[17]
  PIN wbs_dat_o[16]
    DIRECTION OUTPUT ;
    USE SIGNAL ;
    ANTENNADIFFAREA 0.336 LAYER met2  ;
    ANTENNAPARTIALMETALAREA 4.0627 LAYER met2  ;
    ANTENNAPARTIALMETALSIDEAREA 20.2055 LAYER met2  ;
    PORT
      LAYER met2 ;
        RECT 348.380000 0.000000 348.520000 0.485000 ;
    END
  END wbs_dat_o[16]
  PIN wbs_dat_o[15]
    DIRECTION OUTPUT ;
    USE SIGNAL ;
    ANTENNADIFFAREA 0.525 LAYER met2  ;
    ANTENNAPARTIALMETALAREA 4.9935 LAYER met2  ;
    ANTENNAPARTIALMETALSIDEAREA 24.7415 LAYER met2  ;
    ANTENNAMODEL OXIDE1 ;
    ANTENNAGATEAREA 0.246 LAYER met2  ;
    ANTENNAMAXAREACAR 21.288 LAYER met2  ;
    ANTENNAMAXSIDEAREACAR 103.528 LAYER met2  ;
    ANTENNAMAXCUTCAR 0.208943 LAYER via2  ;
    PORT
      LAYER met2 ;
        RECT 330.900000 0.000000 331.040000 0.485000 ;
    END
  END wbs_dat_o[15]
  PIN wbs_dat_o[14]
    DIRECTION OUTPUT ;
    USE SIGNAL ;
    ANTENNADIFFAREA 0.5235 LAYER met2  ;
    ANTENNAPARTIALMETALAREA 5.4261 LAYER met2  ;
    ANTENNAPARTIALMETALSIDEAREA 26.7435 LAYER met2  ;
    ANTENNAPARTIALCUTAREA 0.04 LAYER via2  ;
    ANTENNADIFFAREA 0.5235 LAYER met3  ;
    ANTENNAPARTIALMETALAREA 3.0168 LAYER met3  ;
    ANTENNAPARTIALMETALSIDEAREA 16.56 LAYER met3  ;
    ANTENNAMODEL OXIDE1 ;
    ANTENNAGATEAREA 0.246 LAYER met3  ;
    ANTENNAMAXAREACAR 15.7098 LAYER met3  ;
    ANTENNAMAXSIDEAREACAR 81.9797 LAYER met3  ;
    ANTENNAMAXCUTCAR 0.371545 LAYER via3  ;
    PORT
      LAYER met2 ;
        RECT 313.420000 0.000000 313.560000 0.485000 ;
    END
  END wbs_dat_o[14]
  PIN wbs_dat_o[13]
    DIRECTION OUTPUT ;
    USE SIGNAL ;
    ANTENNAPARTIALMETALAREA 4.459 LAYER met2  ;
    ANTENNAPARTIALMETALSIDEAREA 22.134 LAYER met2  ;
    ANTENNAPARTIALCUTAREA 0.04 LAYER via2  ;
    ANTENNADIFFAREA 0.5235 LAYER met3  ;
    ANTENNAPARTIALMETALAREA 7.2567 LAYER met3  ;
    ANTENNAPARTIALMETALSIDEAREA 39.168 LAYER met3  ;
    ANTENNAMODEL OXIDE1 ;
    ANTENNAGATEAREA 0.246 LAYER met3  ;
    ANTENNAMAXAREACAR 31.0835 LAYER met3  ;
    ANTENNAMAXSIDEAREACAR 164.492 LAYER met3  ;
    ANTENNAMAXCUTCAR 0.371545 LAYER via3  ;
    PORT
      LAYER met2 ;
        RECT 296.400000 0.000000 296.540000 0.485000 ;
    END
  END wbs_dat_o[13]
  PIN wbs_dat_o[12]
    DIRECTION OUTPUT ;
    USE SIGNAL ;
    ANTENNADIFFAREA 0.5235 LAYER met2  ;
    ANTENNAPARTIALMETALAREA 4.9669 LAYER met2  ;
    ANTENNAPARTIALMETALSIDEAREA 24.6085 LAYER met2  ;
    ANTENNAMODEL OXIDE1 ;
    ANTENNAGATEAREA 0.246 LAYER met2  ;
    ANTENNAMAXAREACAR 21.1799 LAYER met2  ;
    ANTENNAMAXSIDEAREACAR 102.988 LAYER met2  ;
    ANTENNAMAXCUTCAR 0.208943 LAYER via2  ;
    PORT
      LAYER met2 ;
        RECT 278.920000 0.000000 279.060000 0.485000 ;
    END
  END wbs_dat_o[12]
  PIN wbs_dat_o[11]
    DIRECTION OUTPUT ;
    USE SIGNAL ;
    ANTENNADIFFAREA 0.5235 LAYER met2  ;
    ANTENNAPARTIALMETALAREA 5.6187 LAYER met2  ;
    ANTENNAPARTIALMETALSIDEAREA 27.8775 LAYER met2  ;
    ANTENNAMODEL OXIDE1 ;
    ANTENNAGATEAREA 0.246 LAYER met2  ;
    ANTENNAMAXAREACAR 23.8295 LAYER met2  ;
    ANTENNAMAXSIDEAREACAR 116.276 LAYER met2  ;
    ANTENNAMAXCUTCAR 0.208943 LAYER via2  ;
    PORT
      LAYER met2 ;
        RECT 261.440000 0.000000 261.580000 0.485000 ;
    END
  END wbs_dat_o[11]
  PIN wbs_dat_o[10]
    DIRECTION OUTPUT ;
    USE SIGNAL ;
    ANTENNADIFFAREA 0.5235 LAYER met2  ;
    ANTENNAPARTIALMETALAREA 5.0559 LAYER met2  ;
    ANTENNAPARTIALMETALSIDEAREA 25.0635 LAYER met2  ;
    ANTENNAMODEL OXIDE1 ;
    ANTENNAGATEAREA 0.246 LAYER met2  ;
    ANTENNAMAXAREACAR 21.9561 LAYER met2  ;
    ANTENNAMAXSIDEAREACAR 107.028 LAYER met2  ;
    ANTENNAMAXCUTCAR 0.208943 LAYER via2  ;
    PORT
      LAYER met2 ;
        RECT 243.960000 0.000000 244.100000 0.485000 ;
    END
  END wbs_dat_o[10]
  PIN wbs_dat_o[9]
    DIRECTION OUTPUT ;
    USE SIGNAL ;
    ANTENNADIFFAREA 0.5235 LAYER met2  ;
    ANTENNAPARTIALMETALAREA 4.7227 LAYER met2  ;
    ANTENNAPARTIALMETALSIDEAREA 23.3975 LAYER met2  ;
    ANTENNAMODEL OXIDE1 ;
    ANTENNAGATEAREA 0.246 LAYER met2  ;
    ANTENNAMAXAREACAR 23.0089 LAYER met2  ;
    ANTENNAMAXSIDEAREACAR 112.293 LAYER met2  ;
    ANTENNAMAXCUTCAR 0.208943 LAYER via2  ;
    PORT
      LAYER met2 ;
        RECT 226.480000 0.000000 226.620000 0.485000 ;
    END
  END wbs_dat_o[9]
  PIN wbs_dat_o[8]
    DIRECTION OUTPUT ;
    USE SIGNAL ;
    ANTENNAPARTIALMETALAREA 4.032 LAYER met2  ;
    ANTENNAPARTIALMETALSIDEAREA 19.999 LAYER met2  ;
    ANTENNAPARTIALCUTAREA 0.04 LAYER via2  ;
    ANTENNADIFFAREA 0.5235 LAYER met3  ;
    ANTENNAPARTIALMETALAREA 4.4868 LAYER met3  ;
    ANTENNAPARTIALMETALSIDEAREA 24.4 LAYER met3  ;
    ANTENNAMODEL OXIDE1 ;
    ANTENNAGATEAREA 0.246 LAYER met3  ;
    ANTENNAMAXAREACAR 25.239 LAYER met3  ;
    ANTENNAMAXSIDEAREACAR 131.179 LAYER met3  ;
    ANTENNAMAXCUTCAR 0.371545 LAYER via3  ;
    PORT
      LAYER met2 ;
        RECT 209.000000 0.000000 209.140000 0.485000 ;
    END
  END wbs_dat_o[8]
  PIN wbs_dat_o[7]
    DIRECTION OUTPUT ;
    USE SIGNAL ;
    ANTENNADIFFAREA 0.5235 LAYER met2  ;
    ANTENNAPARTIALMETALAREA 4.7673 LAYER met2  ;
    ANTENNAPARTIALMETALSIDEAREA 23.5025 LAYER met2  ;
    ANTENNAMODEL OXIDE1 ;
    ANTENNAGATEAREA 0.246 LAYER met2  ;
    ANTENNAMAXAREACAR 22.1431 LAYER met2  ;
    ANTENNAMAXSIDEAREACAR 107.484 LAYER met2  ;
    ANTENNAMAXCUTCAR 0.208943 LAYER via2  ;
    PORT
      LAYER met2 ;
        RECT 191.980000 0.000000 192.120000 0.485000 ;
    END
  END wbs_dat_o[7]
  PIN wbs_dat_o[6]
    DIRECTION OUTPUT ;
    USE SIGNAL ;
    ANTENNADIFFAREA 0.5235 LAYER met2  ;
    ANTENNAPARTIALMETALAREA 5.4987 LAYER met2  ;
    ANTENNAPARTIALMETALSIDEAREA 27.1495 LAYER met2  ;
    ANTENNAMODEL OXIDE1 ;
    ANTENNAGATEAREA 0.246 LAYER met2  ;
    ANTENNAMAXAREACAR 23.3075 LAYER met2  ;
    ANTENNAMAXSIDEAREACAR 113.146 LAYER met2  ;
    ANTENNAMAXCUTCAR 0.208943 LAYER via2  ;
    PORT
      LAYER met2 ;
        RECT 174.500000 0.000000 174.640000 0.485000 ;
    END
  END wbs_dat_o[6]
  PIN wbs_dat_o[5]
    DIRECTION OUTPUT ;
    USE SIGNAL ;
    ANTENNADIFFAREA 0.5235 LAYER met2  ;
    ANTENNAPARTIALMETALAREA 5.5435 LAYER met2  ;
    ANTENNAPARTIALMETALSIDEAREA 27.3735 LAYER met2  ;
    ANTENNAMODEL OXIDE1 ;
    ANTENNAGATEAREA 0.246 LAYER met2  ;
    ANTENNAMAXAREACAR 24.2 LAYER met2  ;
    ANTENNAMAXSIDEAREACAR 117.728 LAYER met2  ;
    ANTENNAMAXCUTCAR 0.208943 LAYER via2  ;
    PORT
      LAYER met2 ;
        RECT 157.020000 0.000000 157.160000 0.485000 ;
    END
  END wbs_dat_o[5]
  PIN wbs_dat_o[4]
    DIRECTION OUTPUT ;
    USE SIGNAL ;
    ANTENNADIFFAREA 0.5235 LAYER met2  ;
    ANTENNAPARTIALMETALAREA 5.4175 LAYER met2  ;
    ANTENNAPARTIALMETALSIDEAREA 26.7435 LAYER met2  ;
    ANTENNAMODEL OXIDE1 ;
    ANTENNAGATEAREA 0.246 LAYER met2  ;
    ANTENNAMAXAREACAR 25.2415 LAYER met2  ;
    ANTENNAMAXSIDEAREACAR 122.935 LAYER met2  ;
    ANTENNAMAXCUTCAR 0.208943 LAYER via2  ;
    PORT
      LAYER met2 ;
        RECT 139.540000 0.000000 139.680000 0.485000 ;
    END
  END wbs_dat_o[4]
  PIN wbs_dat_o[3]
    DIRECTION OUTPUT ;
    USE SIGNAL ;
    ANTENNAPARTIALMETALAREA 3.9466 LAYER met2  ;
    ANTENNAPARTIALMETALSIDEAREA 19.572 LAYER met2  ;
    ANTENNAPARTIALCUTAREA 0.04 LAYER via2  ;
    ANTENNADIFFAREA 0.5235 LAYER met3  ;
    ANTENNAPARTIALMETALAREA 23.2548 LAYER met3  ;
    ANTENNAPARTIALMETALSIDEAREA 124.496 LAYER met3  ;
    ANTENNAMODEL OXIDE1 ;
    ANTENNAGATEAREA 0.246 LAYER met3  ;
    ANTENNAMAXAREACAR 107.377 LAYER met3  ;
    ANTENNAMAXSIDEAREACAR 567.183 LAYER met3  ;
    ANTENNAMAXCUTCAR 0.371545 LAYER via3  ;
    PORT
      LAYER met2 ;
        RECT 116.540000 0.000000 116.680000 0.485000 ;
    END
  END wbs_dat_o[3]
  PIN wbs_dat_o[2]
    DIRECTION OUTPUT ;
    USE SIGNAL ;
    ANTENNADIFFAREA 0.5235 LAYER met2  ;
    ANTENNAPARTIALMETALAREA 6.3675 LAYER met2  ;
    ANTENNAPARTIALMETALSIDEAREA 31.5035 LAYER met2  ;
    ANTENNAMODEL OXIDE1 ;
    ANTENNAGATEAREA 0.246 LAYER met2  ;
    ANTENNAMAXAREACAR 27.2878 LAYER met2  ;
    ANTENNAMAXSIDEAREACAR 133.207 LAYER met2  ;
    ANTENNAMAXCUTCAR 0.208943 LAYER via2  ;
    PORT
      LAYER met2 ;
        RECT 93.080000 0.000000 93.220000 0.485000 ;
    END
  END wbs_dat_o[2]
  PIN wbs_dat_o[1]
    DIRECTION OUTPUT ;
    USE SIGNAL ;
    ANTENNADIFFAREA 0.5235 LAYER met2  ;
    ANTENNAPARTIALMETALAREA 7.8971 LAYER met2  ;
    ANTENNAPARTIALMETALSIDEAREA 39.2595 LAYER met2  ;
    ANTENNAMODEL OXIDE1 ;
    ANTENNAGATEAREA 0.246 LAYER met2  ;
    ANTENNAMAXAREACAR 39.1797 LAYER met2  ;
    ANTENNAMAXSIDEAREACAR 193.106 LAYER met2  ;
    ANTENNAMAXCUTCAR 0.208943 LAYER via2  ;
    PORT
      LAYER met2 ;
        RECT 70.080000 0.000000 70.220000 0.485000 ;
    END
  END wbs_dat_o[1]
  PIN wbs_dat_o[0]
    DIRECTION OUTPUT ;
    USE SIGNAL ;
    ANTENNADIFFAREA 0.8005 LAYER met2  ;
    ANTENNAPARTIALMETALAREA 4.6447 LAYER met2  ;
    ANTENNAPARTIALMETALSIDEAREA 22.8655 LAYER met2  ;
    ANTENNAPARTIALCUTAREA 0.04 LAYER via2  ;
    ANTENNADIFFAREA 0.8005 LAYER met3  ;
    ANTENNAPARTIALMETALAREA 1.3608 LAYER met3  ;
    ANTENNAPARTIALMETALSIDEAREA 7.728 LAYER met3  ;
    ANTENNAMODEL OXIDE1 ;
    ANTENNAGATEAREA 0.246 LAYER met3  ;
    ANTENNAMAXAREACAR 8.31463 LAYER met3  ;
    ANTENNAMAXSIDEAREACAR 42.9187 LAYER met3  ;
    ANTENNAMAXCUTCAR 0.371545 LAYER via3  ;
    PORT
      LAYER met2 ;
        RECT 46.620000 0.000000 46.760000 0.485000 ;
    END
  END wbs_dat_o[0]
  PIN la_data_in[127]
    DIRECTION INPUT ;
    USE SIGNAL ;
    PORT
      LAYER met2 ;
        RECT 2825.020000 0.000000 2825.160000 0.485000 ;
    END
  END la_data_in[127]
  PIN la_data_in[126]
    DIRECTION INPUT ;
    USE SIGNAL ;
    PORT
      LAYER met2 ;
        RECT 2807.540000 0.000000 2807.680000 0.485000 ;
    END
  END la_data_in[126]
  PIN la_data_in[125]
    DIRECTION INPUT ;
    USE SIGNAL ;
    PORT
      LAYER met2 ;
        RECT 2790.060000 0.000000 2790.200000 0.485000 ;
    END
  END la_data_in[125]
  PIN la_data_in[124]
    DIRECTION INPUT ;
    USE SIGNAL ;
    PORT
      LAYER met2 ;
        RECT 2772.580000 0.000000 2772.720000 0.485000 ;
    END
  END la_data_in[124]
  PIN la_data_in[123]
    DIRECTION INPUT ;
    USE SIGNAL ;
    PORT
      LAYER met2 ;
        RECT 2755.560000 0.000000 2755.700000 0.485000 ;
    END
  END la_data_in[123]
  PIN la_data_in[122]
    DIRECTION INPUT ;
    USE SIGNAL ;
    PORT
      LAYER met2 ;
        RECT 2738.080000 0.000000 2738.220000 0.485000 ;
    END
  END la_data_in[122]
  PIN la_data_in[121]
    DIRECTION INPUT ;
    USE SIGNAL ;
    PORT
      LAYER met2 ;
        RECT 2720.600000 0.000000 2720.740000 0.485000 ;
    END
  END la_data_in[121]
  PIN la_data_in[120]
    DIRECTION INPUT ;
    USE SIGNAL ;
    PORT
      LAYER met2 ;
        RECT 2703.120000 0.000000 2703.260000 0.485000 ;
    END
  END la_data_in[120]
  PIN la_data_in[119]
    DIRECTION INPUT ;
    USE SIGNAL ;
    PORT
      LAYER met2 ;
        RECT 2685.640000 0.000000 2685.780000 0.485000 ;
    END
  END la_data_in[119]
  PIN la_data_in[118]
    DIRECTION INPUT ;
    USE SIGNAL ;
    PORT
      LAYER met2 ;
        RECT 2668.160000 0.000000 2668.300000 0.485000 ;
    END
  END la_data_in[118]
  PIN la_data_in[117]
    DIRECTION INPUT ;
    USE SIGNAL ;
    PORT
      LAYER met2 ;
        RECT 2651.140000 0.000000 2651.280000 0.485000 ;
    END
  END la_data_in[117]
  PIN la_data_in[116]
    DIRECTION INPUT ;
    USE SIGNAL ;
    PORT
      LAYER met2 ;
        RECT 2633.660000 0.000000 2633.800000 0.485000 ;
    END
  END la_data_in[116]
  PIN la_data_in[115]
    DIRECTION INPUT ;
    USE SIGNAL ;
    PORT
      LAYER met2 ;
        RECT 2616.180000 0.000000 2616.320000 0.485000 ;
    END
  END la_data_in[115]
  PIN la_data_in[114]
    DIRECTION INPUT ;
    USE SIGNAL ;
    PORT
      LAYER met2 ;
        RECT 2598.700000 0.000000 2598.840000 0.485000 ;
    END
  END la_data_in[114]
  PIN la_data_in[113]
    DIRECTION INPUT ;
    USE SIGNAL ;
    PORT
      LAYER met2 ;
        RECT 2581.220000 0.000000 2581.360000 0.485000 ;
    END
  END la_data_in[113]
  PIN la_data_in[112]
    DIRECTION INPUT ;
    USE SIGNAL ;
    PORT
      LAYER met2 ;
        RECT 2563.740000 0.000000 2563.880000 0.485000 ;
    END
  END la_data_in[112]
  PIN la_data_in[111]
    DIRECTION INPUT ;
    USE SIGNAL ;
    PORT
      LAYER met2 ;
        RECT 2546.720000 0.000000 2546.860000 0.485000 ;
    END
  END la_data_in[111]
  PIN la_data_in[110]
    DIRECTION INPUT ;
    USE SIGNAL ;
    PORT
      LAYER met2 ;
        RECT 2529.240000 0.000000 2529.380000 0.485000 ;
    END
  END la_data_in[110]
  PIN la_data_in[109]
    DIRECTION INPUT ;
    USE SIGNAL ;
    PORT
      LAYER met2 ;
        RECT 2511.760000 0.000000 2511.900000 0.485000 ;
    END
  END la_data_in[109]
  PIN la_data_in[108]
    DIRECTION INPUT ;
    USE SIGNAL ;
    PORT
      LAYER met2 ;
        RECT 2494.280000 0.000000 2494.420000 0.485000 ;
    END
  END la_data_in[108]
  PIN la_data_in[107]
    DIRECTION INPUT ;
    USE SIGNAL ;
    PORT
      LAYER met2 ;
        RECT 2476.800000 0.000000 2476.940000 0.485000 ;
    END
  END la_data_in[107]
  PIN la_data_in[106]
    DIRECTION INPUT ;
    USE SIGNAL ;
    PORT
      LAYER met2 ;
        RECT 2459.780000 0.000000 2459.920000 0.485000 ;
    END
  END la_data_in[106]
  PIN la_data_in[105]
    DIRECTION INPUT ;
    USE SIGNAL ;
    PORT
      LAYER met2 ;
        RECT 2442.300000 0.000000 2442.440000 0.485000 ;
    END
  END la_data_in[105]
  PIN la_data_in[104]
    DIRECTION INPUT ;
    USE SIGNAL ;
    PORT
      LAYER met2 ;
        RECT 2424.820000 0.000000 2424.960000 0.485000 ;
    END
  END la_data_in[104]
  PIN la_data_in[103]
    DIRECTION INPUT ;
    USE SIGNAL ;
    PORT
      LAYER met2 ;
        RECT 2407.340000 0.000000 2407.480000 0.485000 ;
    END
  END la_data_in[103]
  PIN la_data_in[102]
    DIRECTION INPUT ;
    USE SIGNAL ;
    PORT
      LAYER met2 ;
        RECT 2389.860000 0.000000 2390.000000 0.485000 ;
    END
  END la_data_in[102]
  PIN la_data_in[101]
    DIRECTION INPUT ;
    USE SIGNAL ;
    PORT
      LAYER met2 ;
        RECT 2372.380000 0.000000 2372.520000 0.485000 ;
    END
  END la_data_in[101]
  PIN la_data_in[100]
    DIRECTION INPUT ;
    USE SIGNAL ;
    PORT
      LAYER met2 ;
        RECT 2355.360000 0.000000 2355.500000 0.485000 ;
    END
  END la_data_in[100]
  PIN la_data_in[99]
    DIRECTION INPUT ;
    USE SIGNAL ;
    PORT
      LAYER met2 ;
        RECT 2337.880000 0.000000 2338.020000 0.485000 ;
    END
  END la_data_in[99]
  PIN la_data_in[98]
    DIRECTION INPUT ;
    USE SIGNAL ;
    PORT
      LAYER met2 ;
        RECT 2320.400000 0.000000 2320.540000 0.485000 ;
    END
  END la_data_in[98]
  PIN la_data_in[97]
    DIRECTION INPUT ;
    USE SIGNAL ;
    PORT
      LAYER met2 ;
        RECT 2302.920000 0.000000 2303.060000 0.485000 ;
    END
  END la_data_in[97]
  PIN la_data_in[96]
    DIRECTION INPUT ;
    USE SIGNAL ;
    PORT
      LAYER met2 ;
        RECT 2285.440000 0.000000 2285.580000 0.485000 ;
    END
  END la_data_in[96]
  PIN la_data_in[95]
    DIRECTION INPUT ;
    USE SIGNAL ;
    PORT
      LAYER met2 ;
        RECT 2267.960000 0.000000 2268.100000 0.485000 ;
    END
  END la_data_in[95]
  PIN la_data_in[94]
    DIRECTION INPUT ;
    USE SIGNAL ;
    PORT
      LAYER met2 ;
        RECT 2250.940000 0.000000 2251.080000 0.485000 ;
    END
  END la_data_in[94]
  PIN la_data_in[93]
    DIRECTION INPUT ;
    USE SIGNAL ;
    PORT
      LAYER met2 ;
        RECT 2233.460000 0.000000 2233.600000 0.485000 ;
    END
  END la_data_in[93]
  PIN la_data_in[92]
    DIRECTION INPUT ;
    USE SIGNAL ;
    PORT
      LAYER met2 ;
        RECT 2215.980000 0.000000 2216.120000 0.485000 ;
    END
  END la_data_in[92]
  PIN la_data_in[91]
    DIRECTION INPUT ;
    USE SIGNAL ;
    PORT
      LAYER met2 ;
        RECT 2198.500000 0.000000 2198.640000 0.485000 ;
    END
  END la_data_in[91]
  PIN la_data_in[90]
    DIRECTION INPUT ;
    USE SIGNAL ;
    PORT
      LAYER met2 ;
        RECT 2181.020000 0.000000 2181.160000 0.485000 ;
    END
  END la_data_in[90]
  PIN la_data_in[89]
    DIRECTION INPUT ;
    USE SIGNAL ;
    PORT
      LAYER met2 ;
        RECT 2163.540000 0.000000 2163.680000 0.485000 ;
    END
  END la_data_in[89]
  PIN la_data_in[88]
    DIRECTION INPUT ;
    USE SIGNAL ;
    PORT
      LAYER met2 ;
        RECT 2146.520000 0.000000 2146.660000 0.485000 ;
    END
  END la_data_in[88]
  PIN la_data_in[87]
    DIRECTION INPUT ;
    USE SIGNAL ;
    PORT
      LAYER met2 ;
        RECT 2129.040000 0.000000 2129.180000 0.485000 ;
    END
  END la_data_in[87]
  PIN la_data_in[86]
    DIRECTION INPUT ;
    USE SIGNAL ;
    PORT
      LAYER met2 ;
        RECT 2111.560000 0.000000 2111.700000 0.485000 ;
    END
  END la_data_in[86]
  PIN la_data_in[85]
    DIRECTION INPUT ;
    USE SIGNAL ;
    PORT
      LAYER met2 ;
        RECT 2094.080000 0.000000 2094.220000 0.485000 ;
    END
  END la_data_in[85]
  PIN la_data_in[84]
    DIRECTION INPUT ;
    USE SIGNAL ;
    PORT
      LAYER met2 ;
        RECT 2076.600000 0.000000 2076.740000 0.485000 ;
    END
  END la_data_in[84]
  PIN la_data_in[83]
    DIRECTION INPUT ;
    USE SIGNAL ;
    PORT
      LAYER met2 ;
        RECT 2059.580000 0.000000 2059.720000 0.485000 ;
    END
  END la_data_in[83]
  PIN la_data_in[82]
    DIRECTION INPUT ;
    USE SIGNAL ;
    PORT
      LAYER met2 ;
        RECT 2042.100000 0.000000 2042.240000 0.485000 ;
    END
  END la_data_in[82]
  PIN la_data_in[81]
    DIRECTION INPUT ;
    USE SIGNAL ;
    PORT
      LAYER met2 ;
        RECT 2024.620000 0.000000 2024.760000 0.485000 ;
    END
  END la_data_in[81]
  PIN la_data_in[80]
    DIRECTION INPUT ;
    USE SIGNAL ;
    PORT
      LAYER met2 ;
        RECT 2007.140000 0.000000 2007.280000 0.485000 ;
    END
  END la_data_in[80]
  PIN la_data_in[79]
    DIRECTION INPUT ;
    USE SIGNAL ;
    PORT
      LAYER met2 ;
        RECT 1989.660000 0.000000 1989.800000 0.485000 ;
    END
  END la_data_in[79]
  PIN la_data_in[78]
    DIRECTION INPUT ;
    USE SIGNAL ;
    PORT
      LAYER met2 ;
        RECT 1972.180000 0.000000 1972.320000 0.485000 ;
    END
  END la_data_in[78]
  PIN la_data_in[77]
    DIRECTION INPUT ;
    USE SIGNAL ;
    PORT
      LAYER met2 ;
        RECT 1955.160000 0.000000 1955.300000 0.485000 ;
    END
  END la_data_in[77]
  PIN la_data_in[76]
    DIRECTION INPUT ;
    USE SIGNAL ;
    PORT
      LAYER met2 ;
        RECT 1937.680000 0.000000 1937.820000 0.485000 ;
    END
  END la_data_in[76]
  PIN la_data_in[75]
    DIRECTION INPUT ;
    USE SIGNAL ;
    PORT
      LAYER met2 ;
        RECT 1920.200000 0.000000 1920.340000 0.485000 ;
    END
  END la_data_in[75]
  PIN la_data_in[74]
    DIRECTION INPUT ;
    USE SIGNAL ;
    PORT
      LAYER met2 ;
        RECT 1902.720000 0.000000 1902.860000 0.485000 ;
    END
  END la_data_in[74]
  PIN la_data_in[73]
    DIRECTION INPUT ;
    USE SIGNAL ;
    PORT
      LAYER met2 ;
        RECT 1885.240000 0.000000 1885.380000 0.485000 ;
    END
  END la_data_in[73]
  PIN la_data_in[72]
    DIRECTION INPUT ;
    USE SIGNAL ;
    PORT
      LAYER met2 ;
        RECT 1867.760000 0.000000 1867.900000 0.485000 ;
    END
  END la_data_in[72]
  PIN la_data_in[71]
    DIRECTION INPUT ;
    USE SIGNAL ;
    PORT
      LAYER met2 ;
        RECT 1850.740000 0.000000 1850.880000 0.485000 ;
    END
  END la_data_in[71]
  PIN la_data_in[70]
    DIRECTION INPUT ;
    USE SIGNAL ;
    PORT
      LAYER met2 ;
        RECT 1833.260000 0.000000 1833.400000 0.485000 ;
    END
  END la_data_in[70]
  PIN la_data_in[69]
    DIRECTION INPUT ;
    USE SIGNAL ;
    PORT
      LAYER met2 ;
        RECT 1815.780000 0.000000 1815.920000 0.485000 ;
    END
  END la_data_in[69]
  PIN la_data_in[68]
    DIRECTION INPUT ;
    USE SIGNAL ;
    PORT
      LAYER met2 ;
        RECT 1798.300000 0.000000 1798.440000 0.485000 ;
    END
  END la_data_in[68]
  PIN la_data_in[67]
    DIRECTION INPUT ;
    USE SIGNAL ;
    PORT
      LAYER met2 ;
        RECT 1780.820000 0.000000 1780.960000 0.485000 ;
    END
  END la_data_in[67]
  PIN la_data_in[66]
    DIRECTION INPUT ;
    USE SIGNAL ;
    PORT
      LAYER met2 ;
        RECT 1763.340000 0.000000 1763.480000 0.485000 ;
    END
  END la_data_in[66]
  PIN la_data_in[65]
    DIRECTION INPUT ;
    USE SIGNAL ;
    PORT
      LAYER met2 ;
        RECT 1746.320000 0.000000 1746.460000 0.485000 ;
    END
  END la_data_in[65]
  PIN la_data_in[64]
    DIRECTION INPUT ;
    USE SIGNAL ;
    PORT
      LAYER met2 ;
        RECT 1728.840000 0.000000 1728.980000 0.485000 ;
    END
  END la_data_in[64]
  PIN la_data_in[63]
    DIRECTION INPUT ;
    USE SIGNAL ;
    PORT
      LAYER met2 ;
        RECT 1711.360000 0.000000 1711.500000 0.485000 ;
    END
  END la_data_in[63]
  PIN la_data_in[62]
    DIRECTION INPUT ;
    USE SIGNAL ;
    PORT
      LAYER met2 ;
        RECT 1693.880000 0.000000 1694.020000 0.485000 ;
    END
  END la_data_in[62]
  PIN la_data_in[61]
    DIRECTION INPUT ;
    USE SIGNAL ;
    PORT
      LAYER met2 ;
        RECT 1676.400000 0.000000 1676.540000 0.485000 ;
    END
  END la_data_in[61]
  PIN la_data_in[60]
    DIRECTION INPUT ;
    USE SIGNAL ;
    PORT
      LAYER met2 ;
        RECT 1659.380000 0.000000 1659.520000 0.485000 ;
    END
  END la_data_in[60]
  PIN la_data_in[59]
    DIRECTION INPUT ;
    USE SIGNAL ;
    PORT
      LAYER met2 ;
        RECT 1641.900000 0.000000 1642.040000 0.485000 ;
    END
  END la_data_in[59]
  PIN la_data_in[58]
    DIRECTION INPUT ;
    USE SIGNAL ;
    PORT
      LAYER met2 ;
        RECT 1624.420000 0.000000 1624.560000 0.485000 ;
    END
  END la_data_in[58]
  PIN la_data_in[57]
    DIRECTION INPUT ;
    USE SIGNAL ;
    PORT
      LAYER met2 ;
        RECT 1606.940000 0.000000 1607.080000 0.485000 ;
    END
  END la_data_in[57]
  PIN la_data_in[56]
    DIRECTION INPUT ;
    USE SIGNAL ;
    PORT
      LAYER met2 ;
        RECT 1589.460000 0.000000 1589.600000 0.485000 ;
    END
  END la_data_in[56]
  PIN la_data_in[55]
    DIRECTION INPUT ;
    USE SIGNAL ;
    PORT
      LAYER met2 ;
        RECT 1571.980000 0.000000 1572.120000 0.485000 ;
    END
  END la_data_in[55]
  PIN la_data_in[54]
    DIRECTION INPUT ;
    USE SIGNAL ;
    PORT
      LAYER met2 ;
        RECT 1554.960000 0.000000 1555.100000 0.485000 ;
    END
  END la_data_in[54]
  PIN la_data_in[53]
    DIRECTION INPUT ;
    USE SIGNAL ;
    PORT
      LAYER met2 ;
        RECT 1537.480000 0.000000 1537.620000 0.485000 ;
    END
  END la_data_in[53]
  PIN la_data_in[52]
    DIRECTION INPUT ;
    USE SIGNAL ;
    PORT
      LAYER met2 ;
        RECT 1520.000000 0.000000 1520.140000 0.485000 ;
    END
  END la_data_in[52]
  PIN la_data_in[51]
    DIRECTION INPUT ;
    USE SIGNAL ;
    PORT
      LAYER met2 ;
        RECT 1502.520000 0.000000 1502.660000 0.485000 ;
    END
  END la_data_in[51]
  PIN la_data_in[50]
    DIRECTION INPUT ;
    USE SIGNAL ;
    PORT
      LAYER met2 ;
        RECT 1485.040000 0.000000 1485.180000 0.485000 ;
    END
  END la_data_in[50]
  PIN la_data_in[49]
    DIRECTION INPUT ;
    USE SIGNAL ;
    PORT
      LAYER met2 ;
        RECT 1467.560000 0.000000 1467.700000 0.485000 ;
    END
  END la_data_in[49]
  PIN la_data_in[48]
    DIRECTION INPUT ;
    USE SIGNAL ;
    PORT
      LAYER met2 ;
        RECT 1450.540000 0.000000 1450.680000 0.485000 ;
    END
  END la_data_in[48]
  PIN la_data_in[47]
    DIRECTION INPUT ;
    USE SIGNAL ;
    PORT
      LAYER met2 ;
        RECT 1433.060000 0.000000 1433.200000 0.485000 ;
    END
  END la_data_in[47]
  PIN la_data_in[46]
    DIRECTION INPUT ;
    USE SIGNAL ;
    PORT
      LAYER met2 ;
        RECT 1415.580000 0.000000 1415.720000 0.485000 ;
    END
  END la_data_in[46]
  PIN la_data_in[45]
    DIRECTION INPUT ;
    USE SIGNAL ;
    PORT
      LAYER met2 ;
        RECT 1398.100000 0.000000 1398.240000 0.485000 ;
    END
  END la_data_in[45]
  PIN la_data_in[44]
    DIRECTION INPUT ;
    USE SIGNAL ;
    PORT
      LAYER met2 ;
        RECT 1380.620000 0.000000 1380.760000 0.485000 ;
    END
  END la_data_in[44]
  PIN la_data_in[43]
    DIRECTION INPUT ;
    USE SIGNAL ;
    PORT
      LAYER met2 ;
        RECT 1363.600000 0.000000 1363.740000 0.485000 ;
    END
  END la_data_in[43]
  PIN la_data_in[42]
    DIRECTION INPUT ;
    USE SIGNAL ;
    PORT
      LAYER met2 ;
        RECT 1346.120000 0.000000 1346.260000 0.485000 ;
    END
  END la_data_in[42]
  PIN la_data_in[41]
    DIRECTION INPUT ;
    USE SIGNAL ;
    PORT
      LAYER met2 ;
        RECT 1328.640000 0.000000 1328.780000 0.485000 ;
    END
  END la_data_in[41]
  PIN la_data_in[40]
    DIRECTION INPUT ;
    USE SIGNAL ;
    PORT
      LAYER met2 ;
        RECT 1311.160000 0.000000 1311.300000 0.485000 ;
    END
  END la_data_in[40]
  PIN la_data_in[39]
    DIRECTION INPUT ;
    USE SIGNAL ;
    PORT
      LAYER met2 ;
        RECT 1293.680000 0.000000 1293.820000 0.485000 ;
    END
  END la_data_in[39]
  PIN la_data_in[38]
    DIRECTION INPUT ;
    USE SIGNAL ;
    PORT
      LAYER met2 ;
        RECT 1276.200000 0.000000 1276.340000 0.485000 ;
    END
  END la_data_in[38]
  PIN la_data_in[37]
    DIRECTION INPUT ;
    USE SIGNAL ;
    PORT
      LAYER met2 ;
        RECT 1259.180000 0.000000 1259.320000 0.485000 ;
    END
  END la_data_in[37]
  PIN la_data_in[36]
    DIRECTION INPUT ;
    USE SIGNAL ;
    PORT
      LAYER met2 ;
        RECT 1241.700000 0.000000 1241.840000 0.485000 ;
    END
  END la_data_in[36]
  PIN la_data_in[35]
    DIRECTION INPUT ;
    USE SIGNAL ;
    PORT
      LAYER met2 ;
        RECT 1224.220000 0.000000 1224.360000 0.485000 ;
    END
  END la_data_in[35]
  PIN la_data_in[34]
    DIRECTION INPUT ;
    USE SIGNAL ;
    PORT
      LAYER met2 ;
        RECT 1206.740000 0.000000 1206.880000 0.485000 ;
    END
  END la_data_in[34]
  PIN la_data_in[33]
    DIRECTION INPUT ;
    USE SIGNAL ;
    PORT
      LAYER met2 ;
        RECT 1189.260000 0.000000 1189.400000 0.485000 ;
    END
  END la_data_in[33]
  PIN la_data_in[32]
    DIRECTION INPUT ;
    USE SIGNAL ;
    PORT
      LAYER met2 ;
        RECT 1171.780000 0.000000 1171.920000 0.485000 ;
    END
  END la_data_in[32]
  PIN la_data_in[31]
    DIRECTION INPUT ;
    USE SIGNAL ;
    PORT
      LAYER met2 ;
        RECT 1154.760000 0.000000 1154.900000 0.485000 ;
    END
  END la_data_in[31]
  PIN la_data_in[30]
    DIRECTION INPUT ;
    USE SIGNAL ;
    PORT
      LAYER met2 ;
        RECT 1137.280000 0.000000 1137.420000 0.485000 ;
    END
  END la_data_in[30]
  PIN la_data_in[29]
    DIRECTION INPUT ;
    USE SIGNAL ;
    PORT
      LAYER met2 ;
        RECT 1119.800000 0.000000 1119.940000 0.485000 ;
    END
  END la_data_in[29]
  PIN la_data_in[28]
    DIRECTION INPUT ;
    USE SIGNAL ;
    PORT
      LAYER met2 ;
        RECT 1102.320000 0.000000 1102.460000 0.485000 ;
    END
  END la_data_in[28]
  PIN la_data_in[27]
    DIRECTION INPUT ;
    USE SIGNAL ;
    PORT
      LAYER met2 ;
        RECT 1084.840000 0.000000 1084.980000 0.485000 ;
    END
  END la_data_in[27]
  PIN la_data_in[26]
    DIRECTION INPUT ;
    USE SIGNAL ;
    PORT
      LAYER met2 ;
        RECT 1067.360000 0.000000 1067.500000 0.485000 ;
    END
  END la_data_in[26]
  PIN la_data_in[25]
    DIRECTION INPUT ;
    USE SIGNAL ;
    PORT
      LAYER met2 ;
        RECT 1050.340000 0.000000 1050.480000 0.485000 ;
    END
  END la_data_in[25]
  PIN la_data_in[24]
    DIRECTION INPUT ;
    USE SIGNAL ;
    PORT
      LAYER met2 ;
        RECT 1032.860000 0.000000 1033.000000 0.485000 ;
    END
  END la_data_in[24]
  PIN la_data_in[23]
    DIRECTION INPUT ;
    USE SIGNAL ;
    PORT
      LAYER met2 ;
        RECT 1015.380000 0.000000 1015.520000 0.485000 ;
    END
  END la_data_in[23]
  PIN la_data_in[22]
    DIRECTION INPUT ;
    USE SIGNAL ;
    PORT
      LAYER met2 ;
        RECT 997.900000 0.000000 998.040000 0.485000 ;
    END
  END la_data_in[22]
  PIN la_data_in[21]
    DIRECTION INPUT ;
    USE SIGNAL ;
    PORT
      LAYER met2 ;
        RECT 980.420000 0.000000 980.560000 0.485000 ;
    END
  END la_data_in[21]
  PIN la_data_in[20]
    DIRECTION INPUT ;
    USE SIGNAL ;
    PORT
      LAYER met2 ;
        RECT 963.400000 0.000000 963.540000 0.485000 ;
    END
  END la_data_in[20]
  PIN la_data_in[19]
    DIRECTION INPUT ;
    USE SIGNAL ;
    PORT
      LAYER met2 ;
        RECT 945.920000 0.000000 946.060000 0.485000 ;
    END
  END la_data_in[19]
  PIN la_data_in[18]
    DIRECTION INPUT ;
    USE SIGNAL ;
    PORT
      LAYER met2 ;
        RECT 928.440000 0.000000 928.580000 0.485000 ;
    END
  END la_data_in[18]
  PIN la_data_in[17]
    DIRECTION INPUT ;
    USE SIGNAL ;
    PORT
      LAYER met2 ;
        RECT 910.960000 0.000000 911.100000 0.485000 ;
    END
  END la_data_in[17]
  PIN la_data_in[16]
    DIRECTION INPUT ;
    USE SIGNAL ;
    PORT
      LAYER met2 ;
        RECT 893.480000 0.000000 893.620000 0.485000 ;
    END
  END la_data_in[16]
  PIN la_data_in[15]
    DIRECTION INPUT ;
    USE SIGNAL ;
    PORT
      LAYER met2 ;
        RECT 876.000000 0.000000 876.140000 0.485000 ;
    END
  END la_data_in[15]
  PIN la_data_in[14]
    DIRECTION INPUT ;
    USE SIGNAL ;
    PORT
      LAYER met2 ;
        RECT 858.980000 0.000000 859.120000 0.485000 ;
    END
  END la_data_in[14]
  PIN la_data_in[13]
    DIRECTION INPUT ;
    USE SIGNAL ;
    PORT
      LAYER met2 ;
        RECT 841.500000 0.000000 841.640000 0.485000 ;
    END
  END la_data_in[13]
  PIN la_data_in[12]
    DIRECTION INPUT ;
    USE SIGNAL ;
    PORT
      LAYER met2 ;
        RECT 824.020000 0.000000 824.160000 0.485000 ;
    END
  END la_data_in[12]
  PIN la_data_in[11]
    DIRECTION INPUT ;
    USE SIGNAL ;
    PORT
      LAYER met2 ;
        RECT 806.540000 0.000000 806.680000 0.485000 ;
    END
  END la_data_in[11]
  PIN la_data_in[10]
    DIRECTION INPUT ;
    USE SIGNAL ;
    PORT
      LAYER met2 ;
        RECT 789.060000 0.000000 789.200000 0.485000 ;
    END
  END la_data_in[10]
  PIN la_data_in[9]
    DIRECTION INPUT ;
    USE SIGNAL ;
    PORT
      LAYER met2 ;
        RECT 771.580000 0.000000 771.720000 0.485000 ;
    END
  END la_data_in[9]
  PIN la_data_in[8]
    DIRECTION INPUT ;
    USE SIGNAL ;
    PORT
      LAYER met2 ;
        RECT 754.560000 0.000000 754.700000 0.485000 ;
    END
  END la_data_in[8]
  PIN la_data_in[7]
    DIRECTION INPUT ;
    USE SIGNAL ;
    PORT
      LAYER met2 ;
        RECT 737.080000 0.000000 737.220000 0.485000 ;
    END
  END la_data_in[7]
  PIN la_data_in[6]
    DIRECTION INPUT ;
    USE SIGNAL ;
    PORT
      LAYER met2 ;
        RECT 719.600000 0.000000 719.740000 0.485000 ;
    END
  END la_data_in[6]
  PIN la_data_in[5]
    DIRECTION INPUT ;
    USE SIGNAL ;
    PORT
      LAYER met2 ;
        RECT 702.120000 0.000000 702.260000 0.485000 ;
    END
  END la_data_in[5]
  PIN la_data_in[4]
    DIRECTION INPUT ;
    USE SIGNAL ;
    PORT
      LAYER met2 ;
        RECT 684.640000 0.000000 684.780000 0.485000 ;
    END
  END la_data_in[4]
  PIN la_data_in[3]
    DIRECTION INPUT ;
    USE SIGNAL ;
    PORT
      LAYER met2 ;
        RECT 667.160000 0.000000 667.300000 0.485000 ;
    END
  END la_data_in[3]
  PIN la_data_in[2]
    DIRECTION INPUT ;
    USE SIGNAL ;
    PORT
      LAYER met2 ;
        RECT 650.140000 0.000000 650.280000 0.485000 ;
    END
  END la_data_in[2]
  PIN la_data_in[1]
    DIRECTION INPUT ;
    USE SIGNAL ;
    PORT
      LAYER met2 ;
        RECT 632.660000 0.000000 632.800000 0.485000 ;
    END
  END la_data_in[1]
  PIN la_data_in[0]
    DIRECTION INPUT ;
    USE SIGNAL ;
    PORT
      LAYER met2 ;
        RECT 615.180000 0.000000 615.320000 0.485000 ;
    END
  END la_data_in[0]
  PIN la_data_out[127]
    DIRECTION OUTPUT ;
    USE SIGNAL ;
    ANTENNADIFFAREA 0.336 LAYER met2  ;
    ANTENNAPARTIALMETALAREA 4.0627 LAYER met2  ;
    ANTENNAPARTIALMETALSIDEAREA 20.2055 LAYER met2  ;
    PORT
      LAYER met2 ;
        RECT 2830.540000 0.000000 2830.680000 0.485000 ;
    END
  END la_data_out[127]
  PIN la_data_out[126]
    DIRECTION OUTPUT ;
    USE SIGNAL ;
    ANTENNADIFFAREA 0.336 LAYER met2  ;
    ANTENNAPARTIALMETALAREA 4.0627 LAYER met2  ;
    ANTENNAPARTIALMETALSIDEAREA 20.2055 LAYER met2  ;
    PORT
      LAYER met2 ;
        RECT 2813.520000 0.000000 2813.660000 0.485000 ;
    END
  END la_data_out[126]
  PIN la_data_out[125]
    DIRECTION OUTPUT ;
    USE SIGNAL ;
    ANTENNADIFFAREA 0.336 LAYER met2  ;
    ANTENNAPARTIALMETALAREA 4.0627 LAYER met2  ;
    ANTENNAPARTIALMETALSIDEAREA 20.2055 LAYER met2  ;
    PORT
      LAYER met2 ;
        RECT 2796.040000 0.000000 2796.180000 0.485000 ;
    END
  END la_data_out[125]
  PIN la_data_out[124]
    DIRECTION OUTPUT ;
    USE SIGNAL ;
    ANTENNADIFFAREA 0.336 LAYER met2  ;
    ANTENNAPARTIALMETALAREA 4.0627 LAYER met2  ;
    ANTENNAPARTIALMETALSIDEAREA 20.2055 LAYER met2  ;
    PORT
      LAYER met2 ;
        RECT 2778.560000 0.000000 2778.700000 0.485000 ;
    END
  END la_data_out[124]
  PIN la_data_out[123]
    DIRECTION OUTPUT ;
    USE SIGNAL ;
    ANTENNADIFFAREA 0.336 LAYER met2  ;
    ANTENNAPARTIALMETALAREA 4.0627 LAYER met2  ;
    ANTENNAPARTIALMETALSIDEAREA 20.2055 LAYER met2  ;
    PORT
      LAYER met2 ;
        RECT 2761.080000 0.000000 2761.220000 0.485000 ;
    END
  END la_data_out[123]
  PIN la_data_out[122]
    DIRECTION OUTPUT ;
    USE SIGNAL ;
    ANTENNADIFFAREA 0.336 LAYER met2  ;
    ANTENNAPARTIALMETALAREA 4.0627 LAYER met2  ;
    ANTENNAPARTIALMETALSIDEAREA 20.2055 LAYER met2  ;
    PORT
      LAYER met2 ;
        RECT 2743.600000 0.000000 2743.740000 0.485000 ;
    END
  END la_data_out[122]
  PIN la_data_out[121]
    DIRECTION OUTPUT ;
    USE SIGNAL ;
    ANTENNADIFFAREA 0.336 LAYER met2  ;
    ANTENNAPARTIALMETALAREA 4.0627 LAYER met2  ;
    ANTENNAPARTIALMETALSIDEAREA 20.2055 LAYER met2  ;
    PORT
      LAYER met2 ;
        RECT 2726.580000 0.000000 2726.720000 0.485000 ;
    END
  END la_data_out[121]
  PIN la_data_out[120]
    DIRECTION OUTPUT ;
    USE SIGNAL ;
    ANTENNADIFFAREA 0.336 LAYER met2  ;
    ANTENNAPARTIALMETALAREA 4.0627 LAYER met2  ;
    ANTENNAPARTIALMETALSIDEAREA 20.2055 LAYER met2  ;
    PORT
      LAYER met2 ;
        RECT 2709.100000 0.000000 2709.240000 0.485000 ;
    END
  END la_data_out[120]
  PIN la_data_out[119]
    DIRECTION OUTPUT ;
    USE SIGNAL ;
    ANTENNADIFFAREA 0.336 LAYER met2  ;
    ANTENNAPARTIALMETALAREA 4.4435 LAYER met2  ;
    ANTENNAPARTIALMETALSIDEAREA 22.1095 LAYER met2  ;
    PORT
      LAYER met2 ;
        RECT 2691.620000 0.000000 2691.760000 0.485000 ;
    END
  END la_data_out[119]
  PIN la_data_out[118]
    DIRECTION OUTPUT ;
    USE SIGNAL ;
    ANTENNADIFFAREA 0.336 LAYER met2  ;
    ANTENNAPARTIALMETALAREA 4.0627 LAYER met2  ;
    ANTENNAPARTIALMETALSIDEAREA 20.2055 LAYER met2  ;
    PORT
      LAYER met2 ;
        RECT 2674.140000 0.000000 2674.280000 0.485000 ;
    END
  END la_data_out[118]
  PIN la_data_out[117]
    DIRECTION OUTPUT ;
    USE SIGNAL ;
    ANTENNADIFFAREA 0.336 LAYER met2  ;
    ANTENNAPARTIALMETALAREA 4.0627 LAYER met2  ;
    ANTENNAPARTIALMETALSIDEAREA 20.2055 LAYER met2  ;
    PORT
      LAYER met2 ;
        RECT 2656.660000 0.000000 2656.800000 0.485000 ;
    END
  END la_data_out[117]
  PIN la_data_out[116]
    DIRECTION OUTPUT ;
    USE SIGNAL ;
    ANTENNADIFFAREA 0.336 LAYER met2  ;
    ANTENNAPARTIALMETALAREA 4.0627 LAYER met2  ;
    ANTENNAPARTIALMETALSIDEAREA 20.2055 LAYER met2  ;
    PORT
      LAYER met2 ;
        RECT 2639.180000 0.000000 2639.320000 0.485000 ;
    END
  END la_data_out[116]
  PIN la_data_out[115]
    DIRECTION OUTPUT ;
    USE SIGNAL ;
    ANTENNADIFFAREA 0.336 LAYER met2  ;
    ANTENNAPARTIALMETALAREA 4.0627 LAYER met2  ;
    ANTENNAPARTIALMETALSIDEAREA 20.2055 LAYER met2  ;
    PORT
      LAYER met2 ;
        RECT 2622.160000 0.000000 2622.300000 0.485000 ;
    END
  END la_data_out[115]
  PIN la_data_out[114]
    DIRECTION OUTPUT ;
    USE SIGNAL ;
    ANTENNADIFFAREA 0.336 LAYER met2  ;
    ANTENNAPARTIALMETALAREA 4.0627 LAYER met2  ;
    ANTENNAPARTIALMETALSIDEAREA 20.2055 LAYER met2  ;
    PORT
      LAYER met2 ;
        RECT 2604.680000 0.000000 2604.820000 0.485000 ;
    END
  END la_data_out[114]
  PIN la_data_out[113]
    DIRECTION OUTPUT ;
    USE SIGNAL ;
    ANTENNADIFFAREA 0.336 LAYER met2  ;
    ANTENNAPARTIALMETALAREA 4.0627 LAYER met2  ;
    ANTENNAPARTIALMETALSIDEAREA 20.2055 LAYER met2  ;
    PORT
      LAYER met2 ;
        RECT 2587.200000 0.000000 2587.340000 0.485000 ;
    END
  END la_data_out[113]
  PIN la_data_out[112]
    DIRECTION OUTPUT ;
    USE SIGNAL ;
    ANTENNADIFFAREA 0.336 LAYER met2  ;
    ANTENNAPARTIALMETALAREA 4.0627 LAYER met2  ;
    ANTENNAPARTIALMETALSIDEAREA 20.2055 LAYER met2  ;
    PORT
      LAYER met2 ;
        RECT 2569.720000 0.000000 2569.860000 0.485000 ;
    END
  END la_data_out[112]
  PIN la_data_out[111]
    DIRECTION OUTPUT ;
    USE SIGNAL ;
    ANTENNADIFFAREA 0.336 LAYER met2  ;
    ANTENNAPARTIALMETALAREA 4.4435 LAYER met2  ;
    ANTENNAPARTIALMETALSIDEAREA 22.1095 LAYER met2  ;
    PORT
      LAYER met2 ;
        RECT 2552.240000 0.000000 2552.380000 0.485000 ;
    END
  END la_data_out[111]
  PIN la_data_out[110]
    DIRECTION OUTPUT ;
    USE SIGNAL ;
    ANTENNADIFFAREA 0.336 LAYER met2  ;
    ANTENNAPARTIALMETALAREA 4.0627 LAYER met2  ;
    ANTENNAPARTIALMETALSIDEAREA 20.2055 LAYER met2  ;
    PORT
      LAYER met2 ;
        RECT 2534.760000 0.000000 2534.900000 0.485000 ;
    END
  END la_data_out[110]
  PIN la_data_out[109]
    DIRECTION OUTPUT ;
    USE SIGNAL ;
    ANTENNADIFFAREA 0.336 LAYER met2  ;
    ANTENNAPARTIALMETALAREA 4.0627 LAYER met2  ;
    ANTENNAPARTIALMETALSIDEAREA 20.2055 LAYER met2  ;
    PORT
      LAYER met2 ;
        RECT 2517.740000 0.000000 2517.880000 0.485000 ;
    END
  END la_data_out[109]
  PIN la_data_out[108]
    DIRECTION OUTPUT ;
    USE SIGNAL ;
    ANTENNADIFFAREA 0.336 LAYER met2  ;
    ANTENNAPARTIALMETALAREA 4.0627 LAYER met2  ;
    ANTENNAPARTIALMETALSIDEAREA 20.2055 LAYER met2  ;
    PORT
      LAYER met2 ;
        RECT 2500.260000 0.000000 2500.400000 0.485000 ;
    END
  END la_data_out[108]
  PIN la_data_out[107]
    DIRECTION OUTPUT ;
    USE SIGNAL ;
    ANTENNADIFFAREA 0.336 LAYER met2  ;
    ANTENNAPARTIALMETALAREA 4.0627 LAYER met2  ;
    ANTENNAPARTIALMETALSIDEAREA 20.2055 LAYER met2  ;
    PORT
      LAYER met2 ;
        RECT 2482.780000 0.000000 2482.920000 0.485000 ;
    END
  END la_data_out[107]
  PIN la_data_out[106]
    DIRECTION OUTPUT ;
    USE SIGNAL ;
    ANTENNADIFFAREA 0.336 LAYER met2  ;
    ANTENNAPARTIALMETALAREA 4.0627 LAYER met2  ;
    ANTENNAPARTIALMETALSIDEAREA 20.2055 LAYER met2  ;
    PORT
      LAYER met2 ;
        RECT 2465.300000 0.000000 2465.440000 0.485000 ;
    END
  END la_data_out[106]
  PIN la_data_out[105]
    DIRECTION OUTPUT ;
    USE SIGNAL ;
    ANTENNADIFFAREA 0.336 LAYER met2  ;
    ANTENNAPARTIALMETALAREA 4.0627 LAYER met2  ;
    ANTENNAPARTIALMETALSIDEAREA 20.2055 LAYER met2  ;
    PORT
      LAYER met2 ;
        RECT 2447.820000 0.000000 2447.960000 0.485000 ;
    END
  END la_data_out[105]
  PIN la_data_out[104]
    DIRECTION OUTPUT ;
    USE SIGNAL ;
    ANTENNADIFFAREA 0.336 LAYER met2  ;
    ANTENNAPARTIALMETALAREA 4.4435 LAYER met2  ;
    ANTENNAPARTIALMETALSIDEAREA 22.1095 LAYER met2  ;
    PORT
      LAYER met2 ;
        RECT 2430.340000 0.000000 2430.480000 0.485000 ;
    END
  END la_data_out[104]
  PIN la_data_out[103]
    DIRECTION OUTPUT ;
    USE SIGNAL ;
    ANTENNADIFFAREA 0.336 LAYER met2  ;
    ANTENNAPARTIALMETALAREA 4.0627 LAYER met2  ;
    ANTENNAPARTIALMETALSIDEAREA 20.2055 LAYER met2  ;
    PORT
      LAYER met2 ;
        RECT 2413.320000 0.000000 2413.460000 0.485000 ;
    END
  END la_data_out[103]
  PIN la_data_out[102]
    DIRECTION OUTPUT ;
    USE SIGNAL ;
    ANTENNADIFFAREA 0.336 LAYER met2  ;
    ANTENNAPARTIALMETALAREA 4.0627 LAYER met2  ;
    ANTENNAPARTIALMETALSIDEAREA 20.2055 LAYER met2  ;
    PORT
      LAYER met2 ;
        RECT 2395.840000 0.000000 2395.980000 0.485000 ;
    END
  END la_data_out[102]
  PIN la_data_out[101]
    DIRECTION OUTPUT ;
    USE SIGNAL ;
    ANTENNADIFFAREA 0.336 LAYER met2  ;
    ANTENNAPARTIALMETALAREA 4.0627 LAYER met2  ;
    ANTENNAPARTIALMETALSIDEAREA 20.2055 LAYER met2  ;
    PORT
      LAYER met2 ;
        RECT 2378.360000 0.000000 2378.500000 0.485000 ;
    END
  END la_data_out[101]
  PIN la_data_out[100]
    DIRECTION OUTPUT ;
    USE SIGNAL ;
    ANTENNADIFFAREA 0.336 LAYER met2  ;
    ANTENNAPARTIALMETALAREA 4.0627 LAYER met2  ;
    ANTENNAPARTIALMETALSIDEAREA 20.2055 LAYER met2  ;
    PORT
      LAYER met2 ;
        RECT 2360.880000 0.000000 2361.020000 0.485000 ;
    END
  END la_data_out[100]
  PIN la_data_out[99]
    DIRECTION OUTPUT ;
    USE SIGNAL ;
    ANTENNADIFFAREA 0.336 LAYER met2  ;
    ANTENNAPARTIALMETALAREA 4.0627 LAYER met2  ;
    ANTENNAPARTIALMETALSIDEAREA 20.2055 LAYER met2  ;
    PORT
      LAYER met2 ;
        RECT 2343.400000 0.000000 2343.540000 0.485000 ;
    END
  END la_data_out[99]
  PIN la_data_out[98]
    DIRECTION OUTPUT ;
    USE SIGNAL ;
    ANTENNADIFFAREA 0.336 LAYER met2  ;
    ANTENNAPARTIALMETALAREA 4.0627 LAYER met2  ;
    ANTENNAPARTIALMETALSIDEAREA 20.2055 LAYER met2  ;
    PORT
      LAYER met2 ;
        RECT 2326.380000 0.000000 2326.520000 0.485000 ;
    END
  END la_data_out[98]
  PIN la_data_out[97]
    DIRECTION OUTPUT ;
    USE SIGNAL ;
    ANTENNADIFFAREA 0.336 LAYER met2  ;
    ANTENNAPARTIALMETALAREA 4.0627 LAYER met2  ;
    ANTENNAPARTIALMETALSIDEAREA 20.2055 LAYER met2  ;
    PORT
      LAYER met2 ;
        RECT 2308.900000 0.000000 2309.040000 0.485000 ;
    END
  END la_data_out[97]
  PIN la_data_out[96]
    DIRECTION OUTPUT ;
    USE SIGNAL ;
    ANTENNADIFFAREA 0.336 LAYER met2  ;
    ANTENNAPARTIALMETALAREA 4.0627 LAYER met2  ;
    ANTENNAPARTIALMETALSIDEAREA 20.2055 LAYER met2  ;
    PORT
      LAYER met2 ;
        RECT 2291.420000 0.000000 2291.560000 0.485000 ;
    END
  END la_data_out[96]
  PIN la_data_out[95]
    DIRECTION OUTPUT ;
    USE SIGNAL ;
    ANTENNADIFFAREA 0.336 LAYER met2  ;
    ANTENNAPARTIALMETALAREA 4.0627 LAYER met2  ;
    ANTENNAPARTIALMETALSIDEAREA 20.2055 LAYER met2  ;
    PORT
      LAYER met2 ;
        RECT 2273.940000 0.000000 2274.080000 0.485000 ;
    END
  END la_data_out[95]
  PIN la_data_out[94]
    DIRECTION OUTPUT ;
    USE SIGNAL ;
    ANTENNADIFFAREA 0.336 LAYER met2  ;
    ANTENNAPARTIALMETALAREA 4.4435 LAYER met2  ;
    ANTENNAPARTIALMETALSIDEAREA 22.1095 LAYER met2  ;
    PORT
      LAYER met2 ;
        RECT 2256.460000 0.000000 2256.600000 0.485000 ;
    END
  END la_data_out[94]
  PIN la_data_out[93]
    DIRECTION OUTPUT ;
    USE SIGNAL ;
    ANTENNADIFFAREA 0.336 LAYER met2  ;
    ANTENNAPARTIALMETALAREA 4.0627 LAYER met2  ;
    ANTENNAPARTIALMETALSIDEAREA 20.2055 LAYER met2  ;
    PORT
      LAYER met2 ;
        RECT 2238.980000 0.000000 2239.120000 0.485000 ;
    END
  END la_data_out[93]
  PIN la_data_out[92]
    DIRECTION OUTPUT ;
    USE SIGNAL ;
    ANTENNADIFFAREA 0.336 LAYER met2  ;
    ANTENNAPARTIALMETALAREA 4.0627 LAYER met2  ;
    ANTENNAPARTIALMETALSIDEAREA 20.2055 LAYER met2  ;
    PORT
      LAYER met2 ;
        RECT 2221.960000 0.000000 2222.100000 0.485000 ;
    END
  END la_data_out[92]
  PIN la_data_out[91]
    DIRECTION OUTPUT ;
    USE SIGNAL ;
    ANTENNADIFFAREA 0.336 LAYER met2  ;
    ANTENNAPARTIALMETALAREA 4.0627 LAYER met2  ;
    ANTENNAPARTIALMETALSIDEAREA 20.2055 LAYER met2  ;
    PORT
      LAYER met2 ;
        RECT 2204.480000 0.000000 2204.620000 0.485000 ;
    END
  END la_data_out[91]
  PIN la_data_out[90]
    DIRECTION OUTPUT ;
    USE SIGNAL ;
    ANTENNADIFFAREA 0.336 LAYER met2  ;
    ANTENNAPARTIALMETALAREA 4.0627 LAYER met2  ;
    ANTENNAPARTIALMETALSIDEAREA 20.2055 LAYER met2  ;
    PORT
      LAYER met2 ;
        RECT 2187.000000 0.000000 2187.140000 0.485000 ;
    END
  END la_data_out[90]
  PIN la_data_out[89]
    DIRECTION OUTPUT ;
    USE SIGNAL ;
    ANTENNADIFFAREA 0.336 LAYER met2  ;
    ANTENNAPARTIALMETALAREA 4.0627 LAYER met2  ;
    ANTENNAPARTIALMETALSIDEAREA 20.2055 LAYER met2  ;
    PORT
      LAYER met2 ;
        RECT 2169.520000 0.000000 2169.660000 0.485000 ;
    END
  END la_data_out[89]
  PIN la_data_out[88]
    DIRECTION OUTPUT ;
    USE SIGNAL ;
    ANTENNADIFFAREA 0.336 LAYER met2  ;
    ANTENNAPARTIALMETALAREA 4.0627 LAYER met2  ;
    ANTENNAPARTIALMETALSIDEAREA 20.2055 LAYER met2  ;
    PORT
      LAYER met2 ;
        RECT 2152.040000 0.000000 2152.180000 0.485000 ;
    END
  END la_data_out[88]
  PIN la_data_out[87]
    DIRECTION OUTPUT ;
    USE SIGNAL ;
    ANTENNADIFFAREA 0.336 LAYER met2  ;
    ANTENNAPARTIALMETALAREA 4.4435 LAYER met2  ;
    ANTENNAPARTIALMETALSIDEAREA 22.1095 LAYER met2  ;
    PORT
      LAYER met2 ;
        RECT 2134.560000 0.000000 2134.700000 0.485000 ;
    END
  END la_data_out[87]
  PIN la_data_out[86]
    DIRECTION OUTPUT ;
    USE SIGNAL ;
    ANTENNADIFFAREA 0.336 LAYER met2  ;
    ANTENNAPARTIALMETALAREA 4.0627 LAYER met2  ;
    ANTENNAPARTIALMETALSIDEAREA 20.2055 LAYER met2  ;
    PORT
      LAYER met2 ;
        RECT 2117.540000 0.000000 2117.680000 0.485000 ;
    END
  END la_data_out[86]
  PIN la_data_out[85]
    DIRECTION OUTPUT ;
    USE SIGNAL ;
    ANTENNADIFFAREA 0.336 LAYER met2  ;
    ANTENNAPARTIALMETALAREA 4.0627 LAYER met2  ;
    ANTENNAPARTIALMETALSIDEAREA 20.2055 LAYER met2  ;
    PORT
      LAYER met2 ;
        RECT 2100.060000 0.000000 2100.200000 0.485000 ;
    END
  END la_data_out[85]
  PIN la_data_out[84]
    DIRECTION OUTPUT ;
    USE SIGNAL ;
    ANTENNADIFFAREA 0.336 LAYER met2  ;
    ANTENNAPARTIALMETALAREA 4.0627 LAYER met2  ;
    ANTENNAPARTIALMETALSIDEAREA 20.2055 LAYER met2  ;
    PORT
      LAYER met2 ;
        RECT 2082.580000 0.000000 2082.720000 0.485000 ;
    END
  END la_data_out[84]
  PIN la_data_out[83]
    DIRECTION OUTPUT ;
    USE SIGNAL ;
    ANTENNADIFFAREA 0.336 LAYER met2  ;
    ANTENNAPARTIALMETALAREA 4.0627 LAYER met2  ;
    ANTENNAPARTIALMETALSIDEAREA 20.2055 LAYER met2  ;
    PORT
      LAYER met2 ;
        RECT 2065.100000 0.000000 2065.240000 0.485000 ;
    END
  END la_data_out[83]
  PIN la_data_out[82]
    DIRECTION OUTPUT ;
    USE SIGNAL ;
    ANTENNADIFFAREA 0.336 LAYER met2  ;
    ANTENNAPARTIALMETALAREA 4.0627 LAYER met2  ;
    ANTENNAPARTIALMETALSIDEAREA 20.2055 LAYER met2  ;
    PORT
      LAYER met2 ;
        RECT 2047.620000 0.000000 2047.760000 0.485000 ;
    END
  END la_data_out[82]
  PIN la_data_out[81]
    DIRECTION OUTPUT ;
    USE SIGNAL ;
    ANTENNADIFFAREA 0.336 LAYER met2  ;
    ANTENNAPARTIALMETALAREA 4.0627 LAYER met2  ;
    ANTENNAPARTIALMETALSIDEAREA 20.2055 LAYER met2  ;
    PORT
      LAYER met2 ;
        RECT 2030.140000 0.000000 2030.280000 0.485000 ;
    END
  END la_data_out[81]
  PIN la_data_out[80]
    DIRECTION OUTPUT ;
    USE SIGNAL ;
    ANTENNADIFFAREA 0.336 LAYER met2  ;
    ANTENNAPARTIALMETALAREA 4.0627 LAYER met2  ;
    ANTENNAPARTIALMETALSIDEAREA 20.2055 LAYER met2  ;
    PORT
      LAYER met2 ;
        RECT 2013.120000 0.000000 2013.260000 0.485000 ;
    END
  END la_data_out[80]
  PIN la_data_out[79]
    DIRECTION OUTPUT ;
    USE SIGNAL ;
    ANTENNADIFFAREA 0.336 LAYER met2  ;
    ANTENNAPARTIALMETALAREA 4.0627 LAYER met2  ;
    ANTENNAPARTIALMETALSIDEAREA 20.2055 LAYER met2  ;
    PORT
      LAYER met2 ;
        RECT 1995.640000 0.000000 1995.780000 0.485000 ;
    END
  END la_data_out[79]
  PIN la_data_out[78]
    DIRECTION OUTPUT ;
    USE SIGNAL ;
    ANTENNADIFFAREA 0.336 LAYER met2  ;
    ANTENNAPARTIALMETALAREA 4.0627 LAYER met2  ;
    ANTENNAPARTIALMETALSIDEAREA 20.2055 LAYER met2  ;
    PORT
      LAYER met2 ;
        RECT 1978.160000 0.000000 1978.300000 0.485000 ;
    END
  END la_data_out[78]
  PIN la_data_out[77]
    DIRECTION OUTPUT ;
    USE SIGNAL ;
    ANTENNADIFFAREA 0.336 LAYER met2  ;
    ANTENNAPARTIALMETALAREA 4.4435 LAYER met2  ;
    ANTENNAPARTIALMETALSIDEAREA 22.1095 LAYER met2  ;
    PORT
      LAYER met2 ;
        RECT 1960.680000 0.000000 1960.820000 0.485000 ;
    END
  END la_data_out[77]
  PIN la_data_out[76]
    DIRECTION OUTPUT ;
    USE SIGNAL ;
    ANTENNADIFFAREA 0.336 LAYER met2  ;
    ANTENNAPARTIALMETALAREA 4.0627 LAYER met2  ;
    ANTENNAPARTIALMETALSIDEAREA 20.2055 LAYER met2  ;
    PORT
      LAYER met2 ;
        RECT 1943.200000 0.000000 1943.340000 0.485000 ;
    END
  END la_data_out[76]
  PIN la_data_out[75]
    DIRECTION OUTPUT ;
    USE SIGNAL ;
    ANTENNADIFFAREA 0.336 LAYER met2  ;
    ANTENNAPARTIALMETALAREA 4.0627 LAYER met2  ;
    ANTENNAPARTIALMETALSIDEAREA 20.2055 LAYER met2  ;
    PORT
      LAYER met2 ;
        RECT 1926.180000 0.000000 1926.320000 0.485000 ;
    END
  END la_data_out[75]
  PIN la_data_out[74]
    DIRECTION OUTPUT ;
    USE SIGNAL ;
    ANTENNADIFFAREA 0.336 LAYER met2  ;
    ANTENNAPARTIALMETALAREA 4.0627 LAYER met2  ;
    ANTENNAPARTIALMETALSIDEAREA 20.2055 LAYER met2  ;
    PORT
      LAYER met2 ;
        RECT 1908.700000 0.000000 1908.840000 0.485000 ;
    END
  END la_data_out[74]
  PIN la_data_out[73]
    DIRECTION OUTPUT ;
    USE SIGNAL ;
    ANTENNADIFFAREA 0.336 LAYER met2  ;
    ANTENNAPARTIALMETALAREA 4.0627 LAYER met2  ;
    ANTENNAPARTIALMETALSIDEAREA 20.2055 LAYER met2  ;
    PORT
      LAYER met2 ;
        RECT 1891.220000 0.000000 1891.360000 0.485000 ;
    END
  END la_data_out[73]
  PIN la_data_out[72]
    DIRECTION OUTPUT ;
    USE SIGNAL ;
    ANTENNADIFFAREA 0.336 LAYER met2  ;
    ANTENNAPARTIALMETALAREA 4.0627 LAYER met2  ;
    ANTENNAPARTIALMETALSIDEAREA 20.2055 LAYER met2  ;
    PORT
      LAYER met2 ;
        RECT 1873.740000 0.000000 1873.880000 0.485000 ;
    END
  END la_data_out[72]
  PIN la_data_out[71]
    DIRECTION OUTPUT ;
    USE SIGNAL ;
    ANTENNADIFFAREA 0.336 LAYER met2  ;
    ANTENNAPARTIALMETALAREA 4.0627 LAYER met2  ;
    ANTENNAPARTIALMETALSIDEAREA 20.2055 LAYER met2  ;
    PORT
      LAYER met2 ;
        RECT 1856.260000 0.000000 1856.400000 0.485000 ;
    END
  END la_data_out[71]
  PIN la_data_out[70]
    DIRECTION OUTPUT ;
    USE SIGNAL ;
    ANTENNADIFFAREA 0.336 LAYER met2  ;
    ANTENNAPARTIALMETALAREA 4.0627 LAYER met2  ;
    ANTENNAPARTIALMETALSIDEAREA 20.2055 LAYER met2  ;
    PORT
      LAYER met2 ;
        RECT 1838.780000 0.000000 1838.920000 0.485000 ;
    END
  END la_data_out[70]
  PIN la_data_out[69]
    DIRECTION OUTPUT ;
    USE SIGNAL ;
    ANTENNADIFFAREA 0.336 LAYER met2  ;
    ANTENNAPARTIALMETALAREA 4.0627 LAYER met2  ;
    ANTENNAPARTIALMETALSIDEAREA 20.2055 LAYER met2  ;
    PORT
      LAYER met2 ;
        RECT 1821.760000 0.000000 1821.900000 0.485000 ;
    END
  END la_data_out[69]
  PIN la_data_out[68]
    DIRECTION OUTPUT ;
    USE SIGNAL ;
    ANTENNADIFFAREA 0.336 LAYER met2  ;
    ANTENNAPARTIALMETALAREA 4.0627 LAYER met2  ;
    ANTENNAPARTIALMETALSIDEAREA 20.2055 LAYER met2  ;
    PORT
      LAYER met2 ;
        RECT 1804.280000 0.000000 1804.420000 0.485000 ;
    END
  END la_data_out[68]
  PIN la_data_out[67]
    DIRECTION OUTPUT ;
    USE SIGNAL ;
    ANTENNADIFFAREA 0.336 LAYER met2  ;
    ANTENNAPARTIALMETALAREA 4.4435 LAYER met2  ;
    ANTENNAPARTIALMETALSIDEAREA 22.1095 LAYER met2  ;
    PORT
      LAYER met2 ;
        RECT 1786.800000 0.000000 1786.940000 0.485000 ;
    END
  END la_data_out[67]
  PIN la_data_out[66]
    DIRECTION OUTPUT ;
    USE SIGNAL ;
    ANTENNADIFFAREA 0.336 LAYER met2  ;
    ANTENNAPARTIALMETALAREA 4.0627 LAYER met2  ;
    ANTENNAPARTIALMETALSIDEAREA 20.2055 LAYER met2  ;
    PORT
      LAYER met2 ;
        RECT 1769.320000 0.000000 1769.460000 0.485000 ;
    END
  END la_data_out[66]
  PIN la_data_out[65]
    DIRECTION OUTPUT ;
    USE SIGNAL ;
    ANTENNADIFFAREA 0.336 LAYER met2  ;
    ANTENNAPARTIALMETALAREA 4.0627 LAYER met2  ;
    ANTENNAPARTIALMETALSIDEAREA 20.2055 LAYER met2  ;
    PORT
      LAYER met2 ;
        RECT 1751.840000 0.000000 1751.980000 0.485000 ;
    END
  END la_data_out[65]
  PIN la_data_out[64]
    DIRECTION OUTPUT ;
    USE SIGNAL ;
    ANTENNADIFFAREA 0.336 LAYER met2  ;
    ANTENNAPARTIALMETALAREA 4.0627 LAYER met2  ;
    ANTENNAPARTIALMETALSIDEAREA 20.2055 LAYER met2  ;
    PORT
      LAYER met2 ;
        RECT 1734.360000 0.000000 1734.500000 0.485000 ;
    END
  END la_data_out[64]
  PIN la_data_out[63]
    DIRECTION OUTPUT ;
    USE SIGNAL ;
    ANTENNADIFFAREA 0.336 LAYER met2  ;
    ANTENNAPARTIALMETALAREA 4.0627 LAYER met2  ;
    ANTENNAPARTIALMETALSIDEAREA 20.2055 LAYER met2  ;
    PORT
      LAYER met2 ;
        RECT 1717.340000 0.000000 1717.480000 0.485000 ;
    END
  END la_data_out[63]
  PIN la_data_out[62]
    DIRECTION OUTPUT ;
    USE SIGNAL ;
    ANTENNADIFFAREA 0.336 LAYER met2  ;
    ANTENNAPARTIALMETALAREA 4.0627 LAYER met2  ;
    ANTENNAPARTIALMETALSIDEAREA 20.2055 LAYER met2  ;
    PORT
      LAYER met2 ;
        RECT 1699.860000 0.000000 1700.000000 0.485000 ;
    END
  END la_data_out[62]
  PIN la_data_out[61]
    DIRECTION OUTPUT ;
    USE SIGNAL ;
    ANTENNADIFFAREA 0.336 LAYER met2  ;
    ANTENNAPARTIALMETALAREA 4.0627 LAYER met2  ;
    ANTENNAPARTIALMETALSIDEAREA 20.2055 LAYER met2  ;
    PORT
      LAYER met2 ;
        RECT 1682.380000 0.000000 1682.520000 0.485000 ;
    END
  END la_data_out[61]
  PIN la_data_out[60]
    DIRECTION OUTPUT ;
    USE SIGNAL ;
    ANTENNADIFFAREA 0.336 LAYER met2  ;
    ANTENNAPARTIALMETALAREA 4.0627 LAYER met2  ;
    ANTENNAPARTIALMETALSIDEAREA 20.2055 LAYER met2  ;
    PORT
      LAYER met2 ;
        RECT 1664.900000 0.000000 1665.040000 0.485000 ;
    END
  END la_data_out[60]
  PIN la_data_out[59]
    DIRECTION OUTPUT ;
    USE SIGNAL ;
    ANTENNADIFFAREA 0.336 LAYER met2  ;
    ANTENNAPARTIALMETALAREA 4.7256 LAYER met2  ;
    ANTENNAPARTIALMETALSIDEAREA 23.52 LAYER met2  ;
    PORT
      LAYER met2 ;
        RECT 1647.420000 0.000000 1647.560000 0.485000 ;
    END
  END la_data_out[59]
  PIN la_data_out[58]
    DIRECTION OUTPUT ;
    USE SIGNAL ;
    ANTENNADIFFAREA 0.336 LAYER met2  ;
    ANTENNAPARTIALMETALAREA 4.0627 LAYER met2  ;
    ANTENNAPARTIALMETALSIDEAREA 20.2055 LAYER met2  ;
    PORT
      LAYER met2 ;
        RECT 1629.940000 0.000000 1630.080000 0.485000 ;
    END
  END la_data_out[58]
  PIN la_data_out[57]
    DIRECTION OUTPUT ;
    USE SIGNAL ;
    ANTENNADIFFAREA 0.336 LAYER met2  ;
    ANTENNAPARTIALMETALAREA 4.0627 LAYER met2  ;
    ANTENNAPARTIALMETALSIDEAREA 20.2055 LAYER met2  ;
    PORT
      LAYER met2 ;
        RECT 1612.920000 0.000000 1613.060000 0.485000 ;
    END
  END la_data_out[57]
  PIN la_data_out[56]
    DIRECTION OUTPUT ;
    USE SIGNAL ;
    ANTENNADIFFAREA 0.336 LAYER met2  ;
    ANTENNAPARTIALMETALAREA 4.0627 LAYER met2  ;
    ANTENNAPARTIALMETALSIDEAREA 20.2055 LAYER met2  ;
    PORT
      LAYER met2 ;
        RECT 1595.440000 0.000000 1595.580000 0.485000 ;
    END
  END la_data_out[56]
  PIN la_data_out[55]
    DIRECTION OUTPUT ;
    USE SIGNAL ;
    ANTENNADIFFAREA 0.336 LAYER met2  ;
    ANTENNAPARTIALMETALAREA 4.0627 LAYER met2  ;
    ANTENNAPARTIALMETALSIDEAREA 20.2055 LAYER met2  ;
    PORT
      LAYER met2 ;
        RECT 1577.960000 0.000000 1578.100000 0.485000 ;
    END
  END la_data_out[55]
  PIN la_data_out[54]
    DIRECTION OUTPUT ;
    USE SIGNAL ;
    ANTENNADIFFAREA 0.336 LAYER met2  ;
    ANTENNAPARTIALMETALAREA 4.0627 LAYER met2  ;
    ANTENNAPARTIALMETALSIDEAREA 20.2055 LAYER met2  ;
    PORT
      LAYER met2 ;
        RECT 1560.480000 0.000000 1560.620000 0.485000 ;
    END
  END la_data_out[54]
  PIN la_data_out[53]
    DIRECTION OUTPUT ;
    USE SIGNAL ;
    ANTENNADIFFAREA 0.336 LAYER met2  ;
    ANTENNAPARTIALMETALAREA 4.0627 LAYER met2  ;
    ANTENNAPARTIALMETALSIDEAREA 20.2055 LAYER met2  ;
    PORT
      LAYER met2 ;
        RECT 1543.000000 0.000000 1543.140000 0.485000 ;
    END
  END la_data_out[53]
  PIN la_data_out[52]
    DIRECTION OUTPUT ;
    USE SIGNAL ;
    ANTENNADIFFAREA 0.336 LAYER met2  ;
    ANTENNAPARTIALMETALAREA 4.0627 LAYER met2  ;
    ANTENNAPARTIALMETALSIDEAREA 20.2055 LAYER met2  ;
    PORT
      LAYER met2 ;
        RECT 1525.980000 0.000000 1526.120000 0.485000 ;
    END
  END la_data_out[52]
  PIN la_data_out[51]
    DIRECTION OUTPUT ;
    USE SIGNAL ;
    ANTENNADIFFAREA 0.336 LAYER met2  ;
    ANTENNAPARTIALMETALAREA 4.0627 LAYER met2  ;
    ANTENNAPARTIALMETALSIDEAREA 20.2055 LAYER met2  ;
    PORT
      LAYER met2 ;
        RECT 1508.500000 0.000000 1508.640000 0.485000 ;
    END
  END la_data_out[51]
  PIN la_data_out[50]
    DIRECTION OUTPUT ;
    USE SIGNAL ;
    ANTENNADIFFAREA 0.336 LAYER met2  ;
    ANTENNAPARTIALMETALAREA 4.0627 LAYER met2  ;
    ANTENNAPARTIALMETALSIDEAREA 20.2055 LAYER met2  ;
    PORT
      LAYER met2 ;
        RECT 1491.020000 0.000000 1491.160000 0.485000 ;
    END
  END la_data_out[50]
  PIN la_data_out[49]
    DIRECTION OUTPUT ;
    USE SIGNAL ;
    ANTENNADIFFAREA 0.336 LAYER met2  ;
    ANTENNAPARTIALMETALAREA 4.0627 LAYER met2  ;
    ANTENNAPARTIALMETALSIDEAREA 20.2055 LAYER met2  ;
    PORT
      LAYER met2 ;
        RECT 1473.540000 0.000000 1473.680000 0.485000 ;
    END
  END la_data_out[49]
  PIN la_data_out[48]
    DIRECTION OUTPUT ;
    USE SIGNAL ;
    ANTENNADIFFAREA 0.336 LAYER met2  ;
    ANTENNAPARTIALMETALAREA 4.0627 LAYER met2  ;
    ANTENNAPARTIALMETALSIDEAREA 20.2055 LAYER met2  ;
    PORT
      LAYER met2 ;
        RECT 1456.060000 0.000000 1456.200000 0.485000 ;
    END
  END la_data_out[48]
  PIN la_data_out[47]
    DIRECTION OUTPUT ;
    USE SIGNAL ;
    ANTENNADIFFAREA 0.336 LAYER met2  ;
    ANTENNAPARTIALMETALAREA 4.0627 LAYER met2  ;
    ANTENNAPARTIALMETALSIDEAREA 20.2055 LAYER met2  ;
    PORT
      LAYER met2 ;
        RECT 1438.580000 0.000000 1438.720000 0.485000 ;
    END
  END la_data_out[47]
  PIN la_data_out[46]
    DIRECTION OUTPUT ;
    USE SIGNAL ;
    ANTENNADIFFAREA 0.336 LAYER met2  ;
    ANTENNAPARTIALMETALAREA 4.4435 LAYER met2  ;
    ANTENNAPARTIALMETALSIDEAREA 22.1095 LAYER met2  ;
    PORT
      LAYER met2 ;
        RECT 1421.560000 0.000000 1421.700000 0.485000 ;
    END
  END la_data_out[46]
  PIN la_data_out[45]
    DIRECTION OUTPUT ;
    USE SIGNAL ;
    ANTENNADIFFAREA 0.336 LAYER met2  ;
    ANTENNAPARTIALMETALAREA 4.0627 LAYER met2  ;
    ANTENNAPARTIALMETALSIDEAREA 20.2055 LAYER met2  ;
    PORT
      LAYER met2 ;
        RECT 1404.080000 0.000000 1404.220000 0.485000 ;
    END
  END la_data_out[45]
  PIN la_data_out[44]
    DIRECTION OUTPUT ;
    USE SIGNAL ;
    ANTENNADIFFAREA 0.336 LAYER met2  ;
    ANTENNAPARTIALMETALAREA 4.0627 LAYER met2  ;
    ANTENNAPARTIALMETALSIDEAREA 20.2055 LAYER met2  ;
    PORT
      LAYER met2 ;
        RECT 1386.600000 0.000000 1386.740000 0.485000 ;
    END
  END la_data_out[44]
  PIN la_data_out[43]
    DIRECTION OUTPUT ;
    USE SIGNAL ;
    ANTENNADIFFAREA 0.336 LAYER met2  ;
    ANTENNAPARTIALMETALAREA 4.0627 LAYER met2  ;
    ANTENNAPARTIALMETALSIDEAREA 20.2055 LAYER met2  ;
    PORT
      LAYER met2 ;
        RECT 1369.120000 0.000000 1369.260000 0.485000 ;
    END
  END la_data_out[43]
  PIN la_data_out[42]
    DIRECTION OUTPUT ;
    USE SIGNAL ;
    ANTENNADIFFAREA 0.336 LAYER met2  ;
    ANTENNAPARTIALMETALAREA 4.0627 LAYER met2  ;
    ANTENNAPARTIALMETALSIDEAREA 20.2055 LAYER met2  ;
    PORT
      LAYER met2 ;
        RECT 1351.640000 0.000000 1351.780000 0.485000 ;
    END
  END la_data_out[42]
  PIN la_data_out[41]
    DIRECTION OUTPUT ;
    USE SIGNAL ;
    ANTENNADIFFAREA 0.336 LAYER met2  ;
    ANTENNAPARTIALMETALAREA 4.0627 LAYER met2  ;
    ANTENNAPARTIALMETALSIDEAREA 20.2055 LAYER met2  ;
    PORT
      LAYER met2 ;
        RECT 1334.160000 0.000000 1334.300000 0.485000 ;
    END
  END la_data_out[41]
  PIN la_data_out[40]
    DIRECTION OUTPUT ;
    USE SIGNAL ;
    ANTENNADIFFAREA 0.336 LAYER met2  ;
    ANTENNAPARTIALMETALAREA 4.0627 LAYER met2  ;
    ANTENNAPARTIALMETALSIDEAREA 20.2055 LAYER met2  ;
    PORT
      LAYER met2 ;
        RECT 1317.140000 0.000000 1317.280000 0.485000 ;
    END
  END la_data_out[40]
  PIN la_data_out[39]
    DIRECTION OUTPUT ;
    USE SIGNAL ;
    ANTENNADIFFAREA 0.336 LAYER met2  ;
    ANTENNAPARTIALMETALAREA 4.0627 LAYER met2  ;
    ANTENNAPARTIALMETALSIDEAREA 20.2055 LAYER met2  ;
    PORT
      LAYER met2 ;
        RECT 1299.660000 0.000000 1299.800000 0.485000 ;
    END
  END la_data_out[39]
  PIN la_data_out[38]
    DIRECTION OUTPUT ;
    USE SIGNAL ;
    ANTENNADIFFAREA 0.336 LAYER met2  ;
    ANTENNAPARTIALMETALAREA 4.4435 LAYER met2  ;
    ANTENNAPARTIALMETALSIDEAREA 22.1095 LAYER met2  ;
    PORT
      LAYER met2 ;
        RECT 1282.180000 0.000000 1282.320000 0.485000 ;
    END
  END la_data_out[38]
  PIN la_data_out[37]
    DIRECTION OUTPUT ;
    USE SIGNAL ;
    ANTENNADIFFAREA 0.336 LAYER met2  ;
    ANTENNAPARTIALMETALAREA 4.0627 LAYER met2  ;
    ANTENNAPARTIALMETALSIDEAREA 20.2055 LAYER met2  ;
    PORT
      LAYER met2 ;
        RECT 1264.700000 0.000000 1264.840000 0.485000 ;
    END
  END la_data_out[37]
  PIN la_data_out[36]
    DIRECTION OUTPUT ;
    USE SIGNAL ;
    ANTENNADIFFAREA 0.336 LAYER met2  ;
    ANTENNAPARTIALMETALAREA 4.0627 LAYER met2  ;
    ANTENNAPARTIALMETALSIDEAREA 20.2055 LAYER met2  ;
    PORT
      LAYER met2 ;
        RECT 1247.220000 0.000000 1247.360000 0.485000 ;
    END
  END la_data_out[36]
  PIN la_data_out[35]
    DIRECTION OUTPUT ;
    USE SIGNAL ;
    ANTENNADIFFAREA 0.336 LAYER met2  ;
    ANTENNAPARTIALMETALAREA 4.0627 LAYER met2  ;
    ANTENNAPARTIALMETALSIDEAREA 20.2055 LAYER met2  ;
    PORT
      LAYER met2 ;
        RECT 1230.200000 0.000000 1230.340000 0.485000 ;
    END
  END la_data_out[35]
  PIN la_data_out[34]
    DIRECTION OUTPUT ;
    USE SIGNAL ;
    ANTENNADIFFAREA 0.336 LAYER met2  ;
    ANTENNAPARTIALMETALAREA 4.0627 LAYER met2  ;
    ANTENNAPARTIALMETALSIDEAREA 20.2055 LAYER met2  ;
    PORT
      LAYER met2 ;
        RECT 1212.720000 0.000000 1212.860000 0.485000 ;
    END
  END la_data_out[34]
  PIN la_data_out[33]
    DIRECTION OUTPUT ;
    USE SIGNAL ;
    ANTENNADIFFAREA 0.336 LAYER met2  ;
    ANTENNAPARTIALMETALAREA 4.0627 LAYER met2  ;
    ANTENNAPARTIALMETALSIDEAREA 20.2055 LAYER met2  ;
    PORT
      LAYER met2 ;
        RECT 1195.240000 0.000000 1195.380000 0.485000 ;
    END
  END la_data_out[33]
  PIN la_data_out[32]
    DIRECTION OUTPUT ;
    USE SIGNAL ;
    ANTENNADIFFAREA 0.336 LAYER met2  ;
    ANTENNAPARTIALMETALAREA 4.0627 LAYER met2  ;
    ANTENNAPARTIALMETALSIDEAREA 20.2055 LAYER met2  ;
    PORT
      LAYER met2 ;
        RECT 1177.760000 0.000000 1177.900000 0.485000 ;
    END
  END la_data_out[32]
  PIN la_data_out[31]
    DIRECTION OUTPUT ;
    USE SIGNAL ;
    ANTENNADIFFAREA 0.336 LAYER met2  ;
    ANTENNAPARTIALMETALAREA 4.0627 LAYER met2  ;
    ANTENNAPARTIALMETALSIDEAREA 20.2055 LAYER met2  ;
    PORT
      LAYER met2 ;
        RECT 1160.280000 0.000000 1160.420000 0.485000 ;
    END
  END la_data_out[31]
  PIN la_data_out[30]
    DIRECTION OUTPUT ;
    USE SIGNAL ;
    ANTENNADIFFAREA 0.336 LAYER met2  ;
    ANTENNAPARTIALMETALAREA 4.0627 LAYER met2  ;
    ANTENNAPARTIALMETALSIDEAREA 20.2055 LAYER met2  ;
    PORT
      LAYER met2 ;
        RECT 1142.800000 0.000000 1142.940000 0.485000 ;
    END
  END la_data_out[30]
  PIN la_data_out[29]
    DIRECTION OUTPUT ;
    USE SIGNAL ;
    ANTENNADIFFAREA 0.336 LAYER met2  ;
    ANTENNAPARTIALMETALAREA 4.0627 LAYER met2  ;
    ANTENNAPARTIALMETALSIDEAREA 20.2055 LAYER met2  ;
    PORT
      LAYER met2 ;
        RECT 1125.780000 0.000000 1125.920000 0.485000 ;
    END
  END la_data_out[29]
  PIN la_data_out[28]
    DIRECTION OUTPUT ;
    USE SIGNAL ;
    ANTENNADIFFAREA 0.336 LAYER met2  ;
    ANTENNAPARTIALMETALAREA 4.4435 LAYER met2  ;
    ANTENNAPARTIALMETALSIDEAREA 22.1095 LAYER met2  ;
    PORT
      LAYER met2 ;
        RECT 1108.300000 0.000000 1108.440000 0.485000 ;
    END
  END la_data_out[28]
  PIN la_data_out[27]
    DIRECTION OUTPUT ;
    USE SIGNAL ;
    ANTENNADIFFAREA 0.336 LAYER met2  ;
    ANTENNAPARTIALMETALAREA 4.0627 LAYER met2  ;
    ANTENNAPARTIALMETALSIDEAREA 20.2055 LAYER met2  ;
    PORT
      LAYER met2 ;
        RECT 1090.820000 0.000000 1090.960000 0.485000 ;
    END
  END la_data_out[27]
  PIN la_data_out[26]
    DIRECTION OUTPUT ;
    USE SIGNAL ;
    ANTENNADIFFAREA 0.336 LAYER met2  ;
    ANTENNAPARTIALMETALAREA 4.0627 LAYER met2  ;
    ANTENNAPARTIALMETALSIDEAREA 20.2055 LAYER met2  ;
    PORT
      LAYER met2 ;
        RECT 1073.340000 0.000000 1073.480000 0.485000 ;
    END
  END la_data_out[26]
  PIN la_data_out[25]
    DIRECTION OUTPUT ;
    USE SIGNAL ;
    ANTENNADIFFAREA 0.336 LAYER met2  ;
    ANTENNAPARTIALMETALAREA 4.0627 LAYER met2  ;
    ANTENNAPARTIALMETALSIDEAREA 20.2055 LAYER met2  ;
    PORT
      LAYER met2 ;
        RECT 1055.860000 0.000000 1056.000000 0.485000 ;
    END
  END la_data_out[25]
  PIN la_data_out[24]
    DIRECTION OUTPUT ;
    USE SIGNAL ;
    ANTENNADIFFAREA 0.336 LAYER met2  ;
    ANTENNAPARTIALMETALAREA 4.0627 LAYER met2  ;
    ANTENNAPARTIALMETALSIDEAREA 20.2055 LAYER met2  ;
    PORT
      LAYER met2 ;
        RECT 1038.380000 0.000000 1038.520000 0.485000 ;
    END
  END la_data_out[24]
  PIN la_data_out[23]
    DIRECTION OUTPUT ;
    USE SIGNAL ;
    ANTENNADIFFAREA 0.336 LAYER met2  ;
    ANTENNAPARTIALMETALAREA 4.0627 LAYER met2  ;
    ANTENNAPARTIALMETALSIDEAREA 20.2055 LAYER met2  ;
    PORT
      LAYER met2 ;
        RECT 1021.360000 0.000000 1021.500000 0.485000 ;
    END
  END la_data_out[23]
  PIN la_data_out[22]
    DIRECTION OUTPUT ;
    USE SIGNAL ;
    ANTENNADIFFAREA 0.336 LAYER met2  ;
    ANTENNAPARTIALMETALAREA 4.0627 LAYER met2  ;
    ANTENNAPARTIALMETALSIDEAREA 20.2055 LAYER met2  ;
    PORT
      LAYER met2 ;
        RECT 1003.880000 0.000000 1004.020000 0.485000 ;
    END
  END la_data_out[22]
  PIN la_data_out[21]
    DIRECTION OUTPUT ;
    USE SIGNAL ;
    ANTENNADIFFAREA 0.336 LAYER met2  ;
    ANTENNAPARTIALMETALAREA 4.0627 LAYER met2  ;
    ANTENNAPARTIALMETALSIDEAREA 20.2055 LAYER met2  ;
    PORT
      LAYER met2 ;
        RECT 986.400000 0.000000 986.540000 0.485000 ;
    END
  END la_data_out[21]
  PIN la_data_out[20]
    DIRECTION OUTPUT ;
    USE SIGNAL ;
    ANTENNADIFFAREA 0.336 LAYER met2  ;
    ANTENNAPARTIALMETALAREA 4.0627 LAYER met2  ;
    ANTENNAPARTIALMETALSIDEAREA 20.2055 LAYER met2  ;
    PORT
      LAYER met2 ;
        RECT 968.920000 0.000000 969.060000 0.485000 ;
    END
  END la_data_out[20]
  PIN la_data_out[19]
    DIRECTION OUTPUT ;
    USE SIGNAL ;
    ANTENNADIFFAREA 0.336 LAYER met2  ;
    ANTENNAPARTIALMETALAREA 4.0627 LAYER met2  ;
    ANTENNAPARTIALMETALSIDEAREA 20.2055 LAYER met2  ;
    PORT
      LAYER met2 ;
        RECT 951.440000 0.000000 951.580000 0.485000 ;
    END
  END la_data_out[19]
  PIN la_data_out[18]
    DIRECTION OUTPUT ;
    USE SIGNAL ;
    ANTENNADIFFAREA 0.336 LAYER met2  ;
    ANTENNAPARTIALMETALAREA 4.0627 LAYER met2  ;
    ANTENNAPARTIALMETALSIDEAREA 20.2055 LAYER met2  ;
    PORT
      LAYER met2 ;
        RECT 933.960000 0.000000 934.100000 0.485000 ;
    END
  END la_data_out[18]
  PIN la_data_out[17]
    DIRECTION OUTPUT ;
    USE SIGNAL ;
    ANTENNADIFFAREA 0.336 LAYER met2  ;
    ANTENNAPARTIALMETALAREA 4.0627 LAYER met2  ;
    ANTENNAPARTIALMETALSIDEAREA 20.2055 LAYER met2  ;
    PORT
      LAYER met2 ;
        RECT 916.940000 0.000000 917.080000 0.485000 ;
    END
  END la_data_out[17]
  PIN la_data_out[16]
    DIRECTION OUTPUT ;
    USE SIGNAL ;
    ANTENNADIFFAREA 0.336 LAYER met2  ;
    ANTENNAPARTIALMETALAREA 4.0627 LAYER met2  ;
    ANTENNAPARTIALMETALSIDEAREA 20.2055 LAYER met2  ;
    PORT
      LAYER met2 ;
        RECT 899.460000 0.000000 899.600000 0.485000 ;
    END
  END la_data_out[16]
  PIN la_data_out[15]
    DIRECTION OUTPUT ;
    USE SIGNAL ;
    ANTENNADIFFAREA 0.336 LAYER met2  ;
    ANTENNAPARTIALMETALAREA 4.0627 LAYER met2  ;
    ANTENNAPARTIALMETALSIDEAREA 20.2055 LAYER met2  ;
    PORT
      LAYER met2 ;
        RECT 881.980000 0.000000 882.120000 0.485000 ;
    END
  END la_data_out[15]
  PIN la_data_out[14]
    DIRECTION OUTPUT ;
    USE SIGNAL ;
    ANTENNADIFFAREA 0.336 LAYER met2  ;
    ANTENNAPARTIALMETALAREA 4.0627 LAYER met2  ;
    ANTENNAPARTIALMETALSIDEAREA 20.2055 LAYER met2  ;
    PORT
      LAYER met2 ;
        RECT 864.500000 0.000000 864.640000 0.485000 ;
    END
  END la_data_out[14]
  PIN la_data_out[13]
    DIRECTION OUTPUT ;
    USE SIGNAL ;
    ANTENNADIFFAREA 0.336 LAYER met2  ;
    ANTENNAPARTIALMETALAREA 4.0627 LAYER met2  ;
    ANTENNAPARTIALMETALSIDEAREA 20.2055 LAYER met2  ;
    PORT
      LAYER met2 ;
        RECT 847.020000 0.000000 847.160000 0.485000 ;
    END
  END la_data_out[13]
  PIN la_data_out[12]
    DIRECTION OUTPUT ;
    USE SIGNAL ;
    ANTENNADIFFAREA 0.336 LAYER met2  ;
    ANTENNAPARTIALMETALAREA 4.216 LAYER met2  ;
    ANTENNAPARTIALMETALSIDEAREA 20.972 LAYER met2  ;
    PORT
      LAYER met2 ;
        RECT 830.000000 0.000000 830.140000 0.485000 ;
    END
  END la_data_out[12]
  PIN la_data_out[11]
    DIRECTION OUTPUT ;
    USE SIGNAL ;
    ANTENNADIFFAREA 0.336 LAYER met2  ;
    ANTENNAPARTIALMETALAREA 4.0627 LAYER met2  ;
    ANTENNAPARTIALMETALSIDEAREA 20.2055 LAYER met2  ;
    PORT
      LAYER met2 ;
        RECT 812.520000 0.000000 812.660000 0.485000 ;
    END
  END la_data_out[11]
  PIN la_data_out[10]
    DIRECTION OUTPUT ;
    USE SIGNAL ;
    ANTENNADIFFAREA 0.336 LAYER met2  ;
    ANTENNAPARTIALMETALAREA 4.4435 LAYER met2  ;
    ANTENNAPARTIALMETALSIDEAREA 22.1095 LAYER met2  ;
    PORT
      LAYER met2 ;
        RECT 795.040000 0.000000 795.180000 0.485000 ;
    END
  END la_data_out[10]
  PIN la_data_out[9]
    DIRECTION OUTPUT ;
    USE SIGNAL ;
    ANTENNADIFFAREA 0.336 LAYER met2  ;
    ANTENNAPARTIALMETALAREA 4.0627 LAYER met2  ;
    ANTENNAPARTIALMETALSIDEAREA 20.2055 LAYER met2  ;
    PORT
      LAYER met2 ;
        RECT 777.560000 0.000000 777.700000 0.485000 ;
    END
  END la_data_out[9]
  PIN la_data_out[8]
    DIRECTION OUTPUT ;
    USE SIGNAL ;
    ANTENNADIFFAREA 0.336 LAYER met2  ;
    ANTENNAPARTIALMETALAREA 4.0627 LAYER met2  ;
    ANTENNAPARTIALMETALSIDEAREA 20.2055 LAYER met2  ;
    PORT
      LAYER met2 ;
        RECT 760.080000 0.000000 760.220000 0.485000 ;
    END
  END la_data_out[8]
  PIN la_data_out[7]
    DIRECTION OUTPUT ;
    USE SIGNAL ;
    ANTENNADIFFAREA 0.336 LAYER met2  ;
    ANTENNAPARTIALMETALAREA 4.0627 LAYER met2  ;
    ANTENNAPARTIALMETALSIDEAREA 20.2055 LAYER met2  ;
    PORT
      LAYER met2 ;
        RECT 742.600000 0.000000 742.740000 0.485000 ;
    END
  END la_data_out[7]
  PIN la_data_out[6]
    DIRECTION OUTPUT ;
    USE SIGNAL ;
    ANTENNADIFFAREA 0.336 LAYER met2  ;
    ANTENNAPARTIALMETALAREA 4.0627 LAYER met2  ;
    ANTENNAPARTIALMETALSIDEAREA 20.2055 LAYER met2  ;
    PORT
      LAYER met2 ;
        RECT 725.580000 0.000000 725.720000 0.485000 ;
    END
  END la_data_out[6]
  PIN la_data_out[5]
    DIRECTION OUTPUT ;
    USE SIGNAL ;
    ANTENNADIFFAREA 0.336 LAYER met2  ;
    ANTENNAPARTIALMETALAREA 4.0627 LAYER met2  ;
    ANTENNAPARTIALMETALSIDEAREA 20.2055 LAYER met2  ;
    PORT
      LAYER met2 ;
        RECT 708.100000 0.000000 708.240000 0.485000 ;
    END
  END la_data_out[5]
  PIN la_data_out[4]
    DIRECTION OUTPUT ;
    USE SIGNAL ;
    ANTENNADIFFAREA 0.336 LAYER met2  ;
    ANTENNAPARTIALMETALAREA 4.0627 LAYER met2  ;
    ANTENNAPARTIALMETALSIDEAREA 20.2055 LAYER met2  ;
    PORT
      LAYER met2 ;
        RECT 690.620000 0.000000 690.760000 0.485000 ;
    END
  END la_data_out[4]
  PIN la_data_out[3]
    DIRECTION OUTPUT ;
    USE SIGNAL ;
    ANTENNADIFFAREA 0.336 LAYER met2  ;
    ANTENNAPARTIALMETALAREA 4.0627 LAYER met2  ;
    ANTENNAPARTIALMETALSIDEAREA 20.2055 LAYER met2  ;
    PORT
      LAYER met2 ;
        RECT 673.140000 0.000000 673.280000 0.485000 ;
    END
  END la_data_out[3]
  PIN la_data_out[2]
    DIRECTION OUTPUT ;
    USE SIGNAL ;
    ANTENNADIFFAREA 0.336 LAYER met2  ;
    ANTENNAPARTIALMETALAREA 4.0627 LAYER met2  ;
    ANTENNAPARTIALMETALSIDEAREA 20.2055 LAYER met2  ;
    PORT
      LAYER met2 ;
        RECT 655.660000 0.000000 655.800000 0.485000 ;
    END
  END la_data_out[2]
  PIN la_data_out[1]
    DIRECTION OUTPUT ;
    USE SIGNAL ;
    ANTENNADIFFAREA 0.336 LAYER met2  ;
    ANTENNAPARTIALMETALAREA 4.0627 LAYER met2  ;
    ANTENNAPARTIALMETALSIDEAREA 20.2055 LAYER met2  ;
    PORT
      LAYER met2 ;
        RECT 638.180000 0.000000 638.320000 0.485000 ;
    END
  END la_data_out[1]
  PIN la_data_out[0]
    DIRECTION OUTPUT ;
    USE SIGNAL ;
    ANTENNADIFFAREA 0.336 LAYER met2  ;
    ANTENNAPARTIALMETALAREA 4.0627 LAYER met2  ;
    ANTENNAPARTIALMETALSIDEAREA 20.2055 LAYER met2  ;
    PORT
      LAYER met2 ;
        RECT 621.160000 0.000000 621.300000 0.485000 ;
    END
  END la_data_out[0]
  PIN la_oenb[127]
    DIRECTION INPUT ;
    USE SIGNAL ;
    PORT
      LAYER met2 ;
        RECT 2836.520000 0.000000 2836.660000 0.485000 ;
    END
  END la_oenb[127]
  PIN la_oenb[126]
    DIRECTION INPUT ;
    USE SIGNAL ;
    PORT
      LAYER met2 ;
        RECT 2819.040000 0.000000 2819.180000 0.485000 ;
    END
  END la_oenb[126]
  PIN la_oenb[125]
    DIRECTION INPUT ;
    USE SIGNAL ;
    PORT
      LAYER met2 ;
        RECT 2801.560000 0.000000 2801.700000 0.485000 ;
    END
  END la_oenb[125]
  PIN la_oenb[124]
    DIRECTION INPUT ;
    USE SIGNAL ;
    PORT
      LAYER met2 ;
        RECT 2784.540000 0.000000 2784.680000 0.485000 ;
    END
  END la_oenb[124]
  PIN la_oenb[123]
    DIRECTION INPUT ;
    USE SIGNAL ;
    PORT
      LAYER met2 ;
        RECT 2767.060000 0.000000 2767.200000 0.485000 ;
    END
  END la_oenb[123]
  PIN la_oenb[122]
    DIRECTION INPUT ;
    USE SIGNAL ;
    PORT
      LAYER met2 ;
        RECT 2749.580000 0.000000 2749.720000 0.485000 ;
    END
  END la_oenb[122]
  PIN la_oenb[121]
    DIRECTION INPUT ;
    USE SIGNAL ;
    PORT
      LAYER met2 ;
        RECT 2732.100000 0.000000 2732.240000 0.485000 ;
    END
  END la_oenb[121]
  PIN la_oenb[120]
    DIRECTION INPUT ;
    USE SIGNAL ;
    PORT
      LAYER met2 ;
        RECT 2714.620000 0.000000 2714.760000 0.485000 ;
    END
  END la_oenb[120]
  PIN la_oenb[119]
    DIRECTION INPUT ;
    USE SIGNAL ;
    PORT
      LAYER met2 ;
        RECT 2697.140000 0.000000 2697.280000 0.485000 ;
    END
  END la_oenb[119]
  PIN la_oenb[118]
    DIRECTION INPUT ;
    USE SIGNAL ;
    PORT
      LAYER met2 ;
        RECT 2680.120000 0.000000 2680.260000 0.485000 ;
    END
  END la_oenb[118]
  PIN la_oenb[117]
    DIRECTION INPUT ;
    USE SIGNAL ;
    PORT
      LAYER met2 ;
        RECT 2662.640000 0.000000 2662.780000 0.485000 ;
    END
  END la_oenb[117]
  PIN la_oenb[116]
    DIRECTION INPUT ;
    USE SIGNAL ;
    PORT
      LAYER met2 ;
        RECT 2645.160000 0.000000 2645.300000 0.485000 ;
    END
  END la_oenb[116]
  PIN la_oenb[115]
    DIRECTION INPUT ;
    USE SIGNAL ;
    PORT
      LAYER met2 ;
        RECT 2627.680000 0.000000 2627.820000 0.485000 ;
    END
  END la_oenb[115]
  PIN la_oenb[114]
    DIRECTION INPUT ;
    USE SIGNAL ;
    PORT
      LAYER met2 ;
        RECT 2610.200000 0.000000 2610.340000 0.485000 ;
    END
  END la_oenb[114]
  PIN la_oenb[113]
    DIRECTION INPUT ;
    USE SIGNAL ;
    PORT
      LAYER met2 ;
        RECT 2593.180000 0.000000 2593.320000 0.485000 ;
    END
  END la_oenb[113]
  PIN la_oenb[112]
    DIRECTION INPUT ;
    USE SIGNAL ;
    PORT
      LAYER met2 ;
        RECT 2575.700000 0.000000 2575.840000 0.485000 ;
    END
  END la_oenb[112]
  PIN la_oenb[111]
    DIRECTION INPUT ;
    USE SIGNAL ;
    PORT
      LAYER met2 ;
        RECT 2558.220000 0.000000 2558.360000 0.485000 ;
    END
  END la_oenb[111]
  PIN la_oenb[110]
    DIRECTION INPUT ;
    USE SIGNAL ;
    PORT
      LAYER met2 ;
        RECT 2540.740000 0.000000 2540.880000 0.485000 ;
    END
  END la_oenb[110]
  PIN la_oenb[109]
    DIRECTION INPUT ;
    USE SIGNAL ;
    PORT
      LAYER met2 ;
        RECT 2523.260000 0.000000 2523.400000 0.485000 ;
    END
  END la_oenb[109]
  PIN la_oenb[108]
    DIRECTION INPUT ;
    USE SIGNAL ;
    PORT
      LAYER met2 ;
        RECT 2505.780000 0.000000 2505.920000 0.485000 ;
    END
  END la_oenb[108]
  PIN la_oenb[107]
    DIRECTION INPUT ;
    USE SIGNAL ;
    PORT
      LAYER met2 ;
        RECT 2488.760000 0.000000 2488.900000 0.485000 ;
    END
  END la_oenb[107]
  PIN la_oenb[106]
    DIRECTION INPUT ;
    USE SIGNAL ;
    PORT
      LAYER met2 ;
        RECT 2471.280000 0.000000 2471.420000 0.485000 ;
    END
  END la_oenb[106]
  PIN la_oenb[105]
    DIRECTION INPUT ;
    USE SIGNAL ;
    PORT
      LAYER met2 ;
        RECT 2453.800000 0.000000 2453.940000 0.485000 ;
    END
  END la_oenb[105]
  PIN la_oenb[104]
    DIRECTION INPUT ;
    USE SIGNAL ;
    PORT
      LAYER met2 ;
        RECT 2436.320000 0.000000 2436.460000 0.485000 ;
    END
  END la_oenb[104]
  PIN la_oenb[103]
    DIRECTION INPUT ;
    USE SIGNAL ;
    PORT
      LAYER met2 ;
        RECT 2418.840000 0.000000 2418.980000 0.485000 ;
    END
  END la_oenb[103]
  PIN la_oenb[102]
    DIRECTION INPUT ;
    USE SIGNAL ;
    PORT
      LAYER met2 ;
        RECT 2401.360000 0.000000 2401.500000 0.485000 ;
    END
  END la_oenb[102]
  PIN la_oenb[101]
    DIRECTION INPUT ;
    USE SIGNAL ;
    PORT
      LAYER met2 ;
        RECT 2384.340000 0.000000 2384.480000 0.485000 ;
    END
  END la_oenb[101]
  PIN la_oenb[100]
    DIRECTION INPUT ;
    USE SIGNAL ;
    PORT
      LAYER met2 ;
        RECT 2366.860000 0.000000 2367.000000 0.485000 ;
    END
  END la_oenb[100]
  PIN la_oenb[99]
    DIRECTION INPUT ;
    USE SIGNAL ;
    PORT
      LAYER met2 ;
        RECT 2349.380000 0.000000 2349.520000 0.485000 ;
    END
  END la_oenb[99]
  PIN la_oenb[98]
    DIRECTION INPUT ;
    USE SIGNAL ;
    PORT
      LAYER met2 ;
        RECT 2331.900000 0.000000 2332.040000 0.485000 ;
    END
  END la_oenb[98]
  PIN la_oenb[97]
    DIRECTION INPUT ;
    USE SIGNAL ;
    PORT
      LAYER met2 ;
        RECT 2314.420000 0.000000 2314.560000 0.485000 ;
    END
  END la_oenb[97]
  PIN la_oenb[96]
    DIRECTION INPUT ;
    USE SIGNAL ;
    PORT
      LAYER met2 ;
        RECT 2296.940000 0.000000 2297.080000 0.485000 ;
    END
  END la_oenb[96]
  PIN la_oenb[95]
    DIRECTION INPUT ;
    USE SIGNAL ;
    PORT
      LAYER met2 ;
        RECT 2279.920000 0.000000 2280.060000 0.485000 ;
    END
  END la_oenb[95]
  PIN la_oenb[94]
    DIRECTION INPUT ;
    USE SIGNAL ;
    PORT
      LAYER met2 ;
        RECT 2262.440000 0.000000 2262.580000 0.485000 ;
    END
  END la_oenb[94]
  PIN la_oenb[93]
    DIRECTION INPUT ;
    USE SIGNAL ;
    PORT
      LAYER met2 ;
        RECT 2244.960000 0.000000 2245.100000 0.485000 ;
    END
  END la_oenb[93]
  PIN la_oenb[92]
    DIRECTION INPUT ;
    USE SIGNAL ;
    PORT
      LAYER met2 ;
        RECT 2227.480000 0.000000 2227.620000 0.485000 ;
    END
  END la_oenb[92]
  PIN la_oenb[91]
    DIRECTION INPUT ;
    USE SIGNAL ;
    PORT
      LAYER met2 ;
        RECT 2210.000000 0.000000 2210.140000 0.485000 ;
    END
  END la_oenb[91]
  PIN la_oenb[90]
    DIRECTION INPUT ;
    USE SIGNAL ;
    PORT
      LAYER met2 ;
        RECT 2192.980000 0.000000 2193.120000 0.485000 ;
    END
  END la_oenb[90]
  PIN la_oenb[89]
    DIRECTION INPUT ;
    USE SIGNAL ;
    PORT
      LAYER met2 ;
        RECT 2175.500000 0.000000 2175.640000 0.485000 ;
    END
  END la_oenb[89]
  PIN la_oenb[88]
    DIRECTION INPUT ;
    USE SIGNAL ;
    PORT
      LAYER met2 ;
        RECT 2158.020000 0.000000 2158.160000 0.485000 ;
    END
  END la_oenb[88]
  PIN la_oenb[87]
    DIRECTION INPUT ;
    USE SIGNAL ;
    PORT
      LAYER met2 ;
        RECT 2140.540000 0.000000 2140.680000 0.485000 ;
    END
  END la_oenb[87]
  PIN la_oenb[86]
    DIRECTION INPUT ;
    USE SIGNAL ;
    PORT
      LAYER met2 ;
        RECT 2123.060000 0.000000 2123.200000 0.485000 ;
    END
  END la_oenb[86]
  PIN la_oenb[85]
    DIRECTION INPUT ;
    USE SIGNAL ;
    PORT
      LAYER met2 ;
        RECT 2105.580000 0.000000 2105.720000 0.485000 ;
    END
  END la_oenb[85]
  PIN la_oenb[84]
    DIRECTION INPUT ;
    USE SIGNAL ;
    PORT
      LAYER met2 ;
        RECT 2088.560000 0.000000 2088.700000 0.485000 ;
    END
  END la_oenb[84]
  PIN la_oenb[83]
    DIRECTION INPUT ;
    USE SIGNAL ;
    PORT
      LAYER met2 ;
        RECT 2071.080000 0.000000 2071.220000 0.485000 ;
    END
  END la_oenb[83]
  PIN la_oenb[82]
    DIRECTION INPUT ;
    USE SIGNAL ;
    PORT
      LAYER met2 ;
        RECT 2053.600000 0.000000 2053.740000 0.485000 ;
    END
  END la_oenb[82]
  PIN la_oenb[81]
    DIRECTION INPUT ;
    USE SIGNAL ;
    PORT
      LAYER met2 ;
        RECT 2036.120000 0.000000 2036.260000 0.485000 ;
    END
  END la_oenb[81]
  PIN la_oenb[80]
    DIRECTION INPUT ;
    USE SIGNAL ;
    PORT
      LAYER met2 ;
        RECT 2018.640000 0.000000 2018.780000 0.485000 ;
    END
  END la_oenb[80]
  PIN la_oenb[79]
    DIRECTION INPUT ;
    USE SIGNAL ;
    PORT
      LAYER met2 ;
        RECT 2001.160000 0.000000 2001.300000 0.485000 ;
    END
  END la_oenb[79]
  PIN la_oenb[78]
    DIRECTION INPUT ;
    USE SIGNAL ;
    PORT
      LAYER met2 ;
        RECT 1984.140000 0.000000 1984.280000 0.485000 ;
    END
  END la_oenb[78]
  PIN la_oenb[77]
    DIRECTION INPUT ;
    USE SIGNAL ;
    PORT
      LAYER met2 ;
        RECT 1966.660000 0.000000 1966.800000 0.485000 ;
    END
  END la_oenb[77]
  PIN la_oenb[76]
    DIRECTION INPUT ;
    USE SIGNAL ;
    PORT
      LAYER met2 ;
        RECT 1949.180000 0.000000 1949.320000 0.485000 ;
    END
  END la_oenb[76]
  PIN la_oenb[75]
    DIRECTION INPUT ;
    USE SIGNAL ;
    PORT
      LAYER met2 ;
        RECT 1931.700000 0.000000 1931.840000 0.485000 ;
    END
  END la_oenb[75]
  PIN la_oenb[74]
    DIRECTION INPUT ;
    USE SIGNAL ;
    PORT
      LAYER met2 ;
        RECT 1914.220000 0.000000 1914.360000 0.485000 ;
    END
  END la_oenb[74]
  PIN la_oenb[73]
    DIRECTION INPUT ;
    USE SIGNAL ;
    PORT
      LAYER met2 ;
        RECT 1896.740000 0.000000 1896.880000 0.485000 ;
    END
  END la_oenb[73]
  PIN la_oenb[72]
    DIRECTION INPUT ;
    USE SIGNAL ;
    PORT
      LAYER met2 ;
        RECT 1879.720000 0.000000 1879.860000 0.485000 ;
    END
  END la_oenb[72]
  PIN la_oenb[71]
    DIRECTION INPUT ;
    USE SIGNAL ;
    PORT
      LAYER met2 ;
        RECT 1862.240000 0.000000 1862.380000 0.485000 ;
    END
  END la_oenb[71]
  PIN la_oenb[70]
    DIRECTION INPUT ;
    USE SIGNAL ;
    PORT
      LAYER met2 ;
        RECT 1844.760000 0.000000 1844.900000 0.485000 ;
    END
  END la_oenb[70]
  PIN la_oenb[69]
    DIRECTION INPUT ;
    USE SIGNAL ;
    PORT
      LAYER met2 ;
        RECT 1827.280000 0.000000 1827.420000 0.485000 ;
    END
  END la_oenb[69]
  PIN la_oenb[68]
    DIRECTION INPUT ;
    USE SIGNAL ;
    PORT
      LAYER met2 ;
        RECT 1809.800000 0.000000 1809.940000 0.485000 ;
    END
  END la_oenb[68]
  PIN la_oenb[67]
    DIRECTION INPUT ;
    USE SIGNAL ;
    PORT
      LAYER met2 ;
        RECT 1792.780000 0.000000 1792.920000 0.485000 ;
    END
  END la_oenb[67]
  PIN la_oenb[66]
    DIRECTION INPUT ;
    USE SIGNAL ;
    PORT
      LAYER met2 ;
        RECT 1775.300000 0.000000 1775.440000 0.485000 ;
    END
  END la_oenb[66]
  PIN la_oenb[65]
    DIRECTION INPUT ;
    USE SIGNAL ;
    PORT
      LAYER met2 ;
        RECT 1757.820000 0.000000 1757.960000 0.485000 ;
    END
  END la_oenb[65]
  PIN la_oenb[64]
    DIRECTION INPUT ;
    USE SIGNAL ;
    PORT
      LAYER met2 ;
        RECT 1740.340000 0.000000 1740.480000 0.485000 ;
    END
  END la_oenb[64]
  PIN la_oenb[63]
    DIRECTION INPUT ;
    USE SIGNAL ;
    PORT
      LAYER met2 ;
        RECT 1722.860000 0.000000 1723.000000 0.485000 ;
    END
  END la_oenb[63]
  PIN la_oenb[62]
    DIRECTION INPUT ;
    USE SIGNAL ;
    PORT
      LAYER met2 ;
        RECT 1705.380000 0.000000 1705.520000 0.485000 ;
    END
  END la_oenb[62]
  PIN la_oenb[61]
    DIRECTION INPUT ;
    USE SIGNAL ;
    PORT
      LAYER met2 ;
        RECT 1688.360000 0.000000 1688.500000 0.485000 ;
    END
  END la_oenb[61]
  PIN la_oenb[60]
    DIRECTION INPUT ;
    USE SIGNAL ;
    PORT
      LAYER met2 ;
        RECT 1670.880000 0.000000 1671.020000 0.485000 ;
    END
  END la_oenb[60]
  PIN la_oenb[59]
    DIRECTION INPUT ;
    USE SIGNAL ;
    PORT
      LAYER met2 ;
        RECT 1653.400000 0.000000 1653.540000 0.485000 ;
    END
  END la_oenb[59]
  PIN la_oenb[58]
    DIRECTION INPUT ;
    USE SIGNAL ;
    PORT
      LAYER met2 ;
        RECT 1635.920000 0.000000 1636.060000 0.485000 ;
    END
  END la_oenb[58]
  PIN la_oenb[57]
    DIRECTION INPUT ;
    USE SIGNAL ;
    PORT
      LAYER met2 ;
        RECT 1618.440000 0.000000 1618.580000 0.485000 ;
    END
  END la_oenb[57]
  PIN la_oenb[56]
    DIRECTION INPUT ;
    USE SIGNAL ;
    PORT
      LAYER met2 ;
        RECT 1600.960000 0.000000 1601.100000 0.485000 ;
    END
  END la_oenb[56]
  PIN la_oenb[55]
    DIRECTION INPUT ;
    USE SIGNAL ;
    PORT
      LAYER met2 ;
        RECT 1583.940000 0.000000 1584.080000 0.485000 ;
    END
  END la_oenb[55]
  PIN la_oenb[54]
    DIRECTION INPUT ;
    USE SIGNAL ;
    PORT
      LAYER met2 ;
        RECT 1566.460000 0.000000 1566.600000 0.485000 ;
    END
  END la_oenb[54]
  PIN la_oenb[53]
    DIRECTION INPUT ;
    USE SIGNAL ;
    PORT
      LAYER met2 ;
        RECT 1548.980000 0.000000 1549.120000 0.485000 ;
    END
  END la_oenb[53]
  PIN la_oenb[52]
    DIRECTION INPUT ;
    USE SIGNAL ;
    PORT
      LAYER met2 ;
        RECT 1531.500000 0.000000 1531.640000 0.485000 ;
    END
  END la_oenb[52]
  PIN la_oenb[51]
    DIRECTION INPUT ;
    USE SIGNAL ;
    PORT
      LAYER met2 ;
        RECT 1514.020000 0.000000 1514.160000 0.485000 ;
    END
  END la_oenb[51]
  PIN la_oenb[50]
    DIRECTION INPUT ;
    USE SIGNAL ;
    PORT
      LAYER met2 ;
        RECT 1496.540000 0.000000 1496.680000 0.485000 ;
    END
  END la_oenb[50]
  PIN la_oenb[49]
    DIRECTION INPUT ;
    USE SIGNAL ;
    PORT
      LAYER met2 ;
        RECT 1479.520000 0.000000 1479.660000 0.485000 ;
    END
  END la_oenb[49]
  PIN la_oenb[48]
    DIRECTION INPUT ;
    USE SIGNAL ;
    PORT
      LAYER met2 ;
        RECT 1462.040000 0.000000 1462.180000 0.485000 ;
    END
  END la_oenb[48]
  PIN la_oenb[47]
    DIRECTION INPUT ;
    USE SIGNAL ;
    PORT
      LAYER met2 ;
        RECT 1444.560000 0.000000 1444.700000 0.485000 ;
    END
  END la_oenb[47]
  PIN la_oenb[46]
    DIRECTION INPUT ;
    USE SIGNAL ;
    PORT
      LAYER met2 ;
        RECT 1427.080000 0.000000 1427.220000 0.485000 ;
    END
  END la_oenb[46]
  PIN la_oenb[45]
    DIRECTION INPUT ;
    USE SIGNAL ;
    PORT
      LAYER met2 ;
        RECT 1409.600000 0.000000 1409.740000 0.485000 ;
    END
  END la_oenb[45]
  PIN la_oenb[44]
    DIRECTION INPUT ;
    USE SIGNAL ;
    PORT
      LAYER met2 ;
        RECT 1392.580000 0.000000 1392.720000 0.485000 ;
    END
  END la_oenb[44]
  PIN la_oenb[43]
    DIRECTION INPUT ;
    USE SIGNAL ;
    PORT
      LAYER met2 ;
        RECT 1375.100000 0.000000 1375.240000 0.485000 ;
    END
  END la_oenb[43]
  PIN la_oenb[42]
    DIRECTION INPUT ;
    USE SIGNAL ;
    PORT
      LAYER met2 ;
        RECT 1357.620000 0.000000 1357.760000 0.485000 ;
    END
  END la_oenb[42]
  PIN la_oenb[41]
    DIRECTION INPUT ;
    USE SIGNAL ;
    PORT
      LAYER met2 ;
        RECT 1340.140000 0.000000 1340.280000 0.485000 ;
    END
  END la_oenb[41]
  PIN la_oenb[40]
    DIRECTION INPUT ;
    USE SIGNAL ;
    PORT
      LAYER met2 ;
        RECT 1322.660000 0.000000 1322.800000 0.485000 ;
    END
  END la_oenb[40]
  PIN la_oenb[39]
    DIRECTION INPUT ;
    USE SIGNAL ;
    PORT
      LAYER met2 ;
        RECT 1305.180000 0.000000 1305.320000 0.485000 ;
    END
  END la_oenb[39]
  PIN la_oenb[38]
    DIRECTION INPUT ;
    USE SIGNAL ;
    PORT
      LAYER met2 ;
        RECT 1288.160000 0.000000 1288.300000 0.485000 ;
    END
  END la_oenb[38]
  PIN la_oenb[37]
    DIRECTION INPUT ;
    USE SIGNAL ;
    PORT
      LAYER met2 ;
        RECT 1270.680000 0.000000 1270.820000 0.485000 ;
    END
  END la_oenb[37]
  PIN la_oenb[36]
    DIRECTION INPUT ;
    USE SIGNAL ;
    PORT
      LAYER met2 ;
        RECT 1253.200000 0.000000 1253.340000 0.485000 ;
    END
  END la_oenb[36]
  PIN la_oenb[35]
    DIRECTION INPUT ;
    USE SIGNAL ;
    PORT
      LAYER met2 ;
        RECT 1235.720000 0.000000 1235.860000 0.485000 ;
    END
  END la_oenb[35]
  PIN la_oenb[34]
    DIRECTION INPUT ;
    USE SIGNAL ;
    PORT
      LAYER met2 ;
        RECT 1218.240000 0.000000 1218.380000 0.485000 ;
    END
  END la_oenb[34]
  PIN la_oenb[33]
    DIRECTION INPUT ;
    USE SIGNAL ;
    PORT
      LAYER met2 ;
        RECT 1200.760000 0.000000 1200.900000 0.485000 ;
    END
  END la_oenb[33]
  PIN la_oenb[32]
    DIRECTION INPUT ;
    USE SIGNAL ;
    PORT
      LAYER met2 ;
        RECT 1183.740000 0.000000 1183.880000 0.485000 ;
    END
  END la_oenb[32]
  PIN la_oenb[31]
    DIRECTION INPUT ;
    USE SIGNAL ;
    PORT
      LAYER met2 ;
        RECT 1166.260000 0.000000 1166.400000 0.485000 ;
    END
  END la_oenb[31]
  PIN la_oenb[30]
    DIRECTION INPUT ;
    USE SIGNAL ;
    PORT
      LAYER met2 ;
        RECT 1148.780000 0.000000 1148.920000 0.485000 ;
    END
  END la_oenb[30]
  PIN la_oenb[29]
    DIRECTION INPUT ;
    USE SIGNAL ;
    PORT
      LAYER met2 ;
        RECT 1131.300000 0.000000 1131.440000 0.485000 ;
    END
  END la_oenb[29]
  PIN la_oenb[28]
    DIRECTION INPUT ;
    USE SIGNAL ;
    PORT
      LAYER met2 ;
        RECT 1113.820000 0.000000 1113.960000 0.485000 ;
    END
  END la_oenb[28]
  PIN la_oenb[27]
    DIRECTION INPUT ;
    USE SIGNAL ;
    PORT
      LAYER met2 ;
        RECT 1096.800000 0.000000 1096.940000 0.485000 ;
    END
  END la_oenb[27]
  PIN la_oenb[26]
    DIRECTION INPUT ;
    USE SIGNAL ;
    PORT
      LAYER met2 ;
        RECT 1079.320000 0.000000 1079.460000 0.485000 ;
    END
  END la_oenb[26]
  PIN la_oenb[25]
    DIRECTION INPUT ;
    USE SIGNAL ;
    PORT
      LAYER met2 ;
        RECT 1061.840000 0.000000 1061.980000 0.485000 ;
    END
  END la_oenb[25]
  PIN la_oenb[24]
    DIRECTION INPUT ;
    USE SIGNAL ;
    PORT
      LAYER met2 ;
        RECT 1044.360000 0.000000 1044.500000 0.485000 ;
    END
  END la_oenb[24]
  PIN la_oenb[23]
    DIRECTION INPUT ;
    USE SIGNAL ;
    PORT
      LAYER met2 ;
        RECT 1026.880000 0.000000 1027.020000 0.485000 ;
    END
  END la_oenb[23]
  PIN la_oenb[22]
    DIRECTION INPUT ;
    USE SIGNAL ;
    PORT
      LAYER met2 ;
        RECT 1009.400000 0.000000 1009.540000 0.485000 ;
    END
  END la_oenb[22]
  PIN la_oenb[21]
    DIRECTION INPUT ;
    USE SIGNAL ;
    PORT
      LAYER met2 ;
        RECT 992.380000 0.000000 992.520000 0.485000 ;
    END
  END la_oenb[21]
  PIN la_oenb[20]
    DIRECTION INPUT ;
    USE SIGNAL ;
    PORT
      LAYER met2 ;
        RECT 974.900000 0.000000 975.040000 0.485000 ;
    END
  END la_oenb[20]
  PIN la_oenb[19]
    DIRECTION INPUT ;
    USE SIGNAL ;
    PORT
      LAYER met2 ;
        RECT 957.420000 0.000000 957.560000 0.485000 ;
    END
  END la_oenb[19]
  PIN la_oenb[18]
    DIRECTION INPUT ;
    USE SIGNAL ;
    PORT
      LAYER met2 ;
        RECT 939.940000 0.000000 940.080000 0.485000 ;
    END
  END la_oenb[18]
  PIN la_oenb[17]
    DIRECTION INPUT ;
    USE SIGNAL ;
    PORT
      LAYER met2 ;
        RECT 922.460000 0.000000 922.600000 0.485000 ;
    END
  END la_oenb[17]
  PIN la_oenb[16]
    DIRECTION INPUT ;
    USE SIGNAL ;
    PORT
      LAYER met2 ;
        RECT 904.980000 0.000000 905.120000 0.485000 ;
    END
  END la_oenb[16]
  PIN la_oenb[15]
    DIRECTION INPUT ;
    USE SIGNAL ;
    PORT
      LAYER met2 ;
        RECT 887.960000 0.000000 888.100000 0.485000 ;
    END
  END la_oenb[15]
  PIN la_oenb[14]
    DIRECTION INPUT ;
    USE SIGNAL ;
    PORT
      LAYER met2 ;
        RECT 870.480000 0.000000 870.620000 0.485000 ;
    END
  END la_oenb[14]
  PIN la_oenb[13]
    DIRECTION INPUT ;
    USE SIGNAL ;
    PORT
      LAYER met2 ;
        RECT 853.000000 0.000000 853.140000 0.485000 ;
    END
  END la_oenb[13]
  PIN la_oenb[12]
    DIRECTION INPUT ;
    USE SIGNAL ;
    PORT
      LAYER met2 ;
        RECT 835.520000 0.000000 835.660000 0.485000 ;
    END
  END la_oenb[12]
  PIN la_oenb[11]
    DIRECTION INPUT ;
    USE SIGNAL ;
    PORT
      LAYER met2 ;
        RECT 818.040000 0.000000 818.180000 0.485000 ;
    END
  END la_oenb[11]
  PIN la_oenb[10]
    DIRECTION INPUT ;
    USE SIGNAL ;
    PORT
      LAYER met2 ;
        RECT 800.560000 0.000000 800.700000 0.485000 ;
    END
  END la_oenb[10]
  PIN la_oenb[9]
    DIRECTION INPUT ;
    USE SIGNAL ;
    PORT
      LAYER met2 ;
        RECT 783.540000 0.000000 783.680000 0.485000 ;
    END
  END la_oenb[9]
  PIN la_oenb[8]
    DIRECTION INPUT ;
    USE SIGNAL ;
    PORT
      LAYER met2 ;
        RECT 766.060000 0.000000 766.200000 0.485000 ;
    END
  END la_oenb[8]
  PIN la_oenb[7]
    DIRECTION INPUT ;
    USE SIGNAL ;
    PORT
      LAYER met2 ;
        RECT 748.580000 0.000000 748.720000 0.485000 ;
    END
  END la_oenb[7]
  PIN la_oenb[6]
    DIRECTION INPUT ;
    USE SIGNAL ;
    PORT
      LAYER met2 ;
        RECT 731.100000 0.000000 731.240000 0.485000 ;
    END
  END la_oenb[6]
  PIN la_oenb[5]
    DIRECTION INPUT ;
    USE SIGNAL ;
    PORT
      LAYER met2 ;
        RECT 713.620000 0.000000 713.760000 0.485000 ;
    END
  END la_oenb[5]
  PIN la_oenb[4]
    DIRECTION INPUT ;
    USE SIGNAL ;
    PORT
      LAYER met2 ;
        RECT 696.600000 0.000000 696.740000 0.485000 ;
    END
  END la_oenb[4]
  PIN la_oenb[3]
    DIRECTION INPUT ;
    USE SIGNAL ;
    PORT
      LAYER met2 ;
        RECT 679.120000 0.000000 679.260000 0.485000 ;
    END
  END la_oenb[3]
  PIN la_oenb[2]
    DIRECTION INPUT ;
    USE SIGNAL ;
    PORT
      LAYER met2 ;
        RECT 661.640000 0.000000 661.780000 0.485000 ;
    END
  END la_oenb[2]
  PIN la_oenb[1]
    DIRECTION INPUT ;
    USE SIGNAL ;
    PORT
      LAYER met2 ;
        RECT 644.160000 0.000000 644.300000 0.485000 ;
    END
  END la_oenb[1]
  PIN la_oenb[0]
    DIRECTION INPUT ;
    USE SIGNAL ;
    PORT
      LAYER met2 ;
        RECT 626.680000 0.000000 626.820000 0.485000 ;
    END
  END la_oenb[0]
  PIN io_in[37]
    DIRECTION INPUT ;
    USE SIGNAL ;
    PORT
      LAYER met3 ;
        RECT 0.000000 130.450000 0.800000 130.750000 ;
    END
  END io_in[37]
  PIN io_in[36]
    DIRECTION INPUT ;
    USE SIGNAL ;
    PORT
      LAYER met3 ;
        RECT 0.000000 326.260000 0.800000 326.560000 ;
    END
  END io_in[36]
  PIN io_in[35]
    DIRECTION INPUT ;
    USE SIGNAL ;
    PORT
      LAYER met3 ;
        RECT 0.000000 522.070000 0.800000 522.370000 ;
    END
  END io_in[35]
  PIN io_in[34]
    DIRECTION INPUT ;
    USE SIGNAL ;
    PORT
      LAYER met3 ;
        RECT 0.000000 783.150000 0.800000 783.450000 ;
    END
  END io_in[34]
  PIN io_in[33]
    DIRECTION INPUT ;
    USE SIGNAL ;
    PORT
      LAYER met3 ;
        RECT 0.000000 1044.230000 0.800000 1044.530000 ;
    END
  END io_in[33]
  PIN io_in[32]
    DIRECTION INPUT ;
    USE SIGNAL ;
    PORT
      LAYER met3 ;
        RECT 0.000000 1305.310000 0.800000 1305.610000 ;
    END
  END io_in[32]
  PIN io_in[31]
    DIRECTION INPUT ;
    USE SIGNAL ;
    PORT
      LAYER met3 ;
        RECT 0.000000 1566.390000 0.800000 1566.690000 ;
    END
  END io_in[31]
  PIN io_in[30]
    DIRECTION INPUT ;
    USE SIGNAL ;
    PORT
      LAYER met3 ;
        RECT 0.000000 1827.470000 0.800000 1827.770000 ;
    END
  END io_in[30]
  PIN io_in[29]
    DIRECTION INPUT ;
    USE SIGNAL ;
    PORT
      LAYER met3 ;
        RECT 0.000000 2088.550000 0.800000 2088.850000 ;
    END
  END io_in[29]
  PIN io_in[28]
    DIRECTION INPUT ;
    USE SIGNAL ;
    PORT
      LAYER met3 ;
        RECT 0.000000 2349.630000 0.800000 2349.930000 ;
    END
  END io_in[28]
  PIN io_in[27]
    DIRECTION INPUT ;
    USE SIGNAL ;
    PORT
      LAYER met3 ;
        RECT 0.000000 2610.710000 0.800000 2611.010000 ;
    END
  END io_in[27]
  PIN io_in[26]
    DIRECTION INPUT ;
    USE SIGNAL ;
    PORT
      LAYER met3 ;
        RECT 0.000000 2871.790000 0.800000 2872.090000 ;
    END
  END io_in[26]
  PIN io_in[25]
    DIRECTION INPUT ;
    USE SIGNAL ;
    PORT
      LAYER met3 ;
        RECT 0.000000 3132.870000 0.800000 3133.170000 ;
    END
  END io_in[25]
  PIN io_in[24]
    DIRECTION INPUT ;
    USE SIGNAL ;
    PORT
      LAYER met3 ;
        RECT 0.000000 3393.950000 0.800000 3394.250000 ;
    END
  END io_in[24]
  PIN io_in[23]
    DIRECTION INPUT ;
    USE SIGNAL ;
    PORT
      LAYER met2 ;
        RECT 163.460000 3459.355000 163.600000 3459.840000 ;
    END
  END io_in[23]
  PIN io_in[22]
    DIRECTION INPUT ;
    USE SIGNAL ;
    PORT
      LAYER met2 ;
        RECT 490.060000 3459.355000 490.200000 3459.840000 ;
    END
  END io_in[22]
  PIN io_in[21]
    DIRECTION INPUT ;
    USE SIGNAL ;
    PORT
      LAYER met2 ;
        RECT 816.660000 3459.355000 816.800000 3459.840000 ;
    END
  END io_in[21]
  PIN io_in[20]
    DIRECTION INPUT ;
    USE SIGNAL ;
    PORT
      LAYER met2 ;
        RECT 1143.720000 3459.355000 1143.860000 3459.840000 ;
    END
  END io_in[20]
  PIN io_in[19]
    DIRECTION INPUT ;
    USE SIGNAL ;
    PORT
      LAYER met2 ;
        RECT 1470.320000 3459.355000 1470.460000 3459.840000 ;
    END
  END io_in[19]
  PIN io_in[18]
    DIRECTION INPUT ;
    USE SIGNAL ;
    PORT
      LAYER met2 ;
        RECT 1797.380000 3459.355000 1797.520000 3459.840000 ;
    END
  END io_in[18]
  PIN io_in[17]
    DIRECTION INPUT ;
    USE SIGNAL ;
    PORT
      LAYER met2 ;
        RECT 2123.980000 3459.355000 2124.120000 3459.840000 ;
    END
  END io_in[17]
  PIN io_in[16]
    DIRECTION INPUT ;
    USE SIGNAL ;
    PORT
      LAYER met2 ;
        RECT 2451.040000 3459.355000 2451.180000 3459.840000 ;
    END
  END io_in[16]
  PIN io_in[15]
    DIRECTION INPUT ;
    USE SIGNAL ;
    PORT
      LAYER met2 ;
        RECT 2777.640000 3459.355000 2777.780000 3459.840000 ;
    END
  END io_in[15]
  PIN io_in[14]
    DIRECTION INPUT ;
    USE SIGNAL ;
    PORT
      LAYER met3 ;
        RECT 2859.020000 3326.240000 2859.820000 3326.540000 ;
    END
  END io_in[14]
  PIN io_in[13]
    DIRECTION INPUT ;
    USE SIGNAL ;
    PORT
      LAYER met3 ;
        RECT 2859.020000 3060.280000 2859.820000 3060.580000 ;
    END
  END io_in[13]
  PIN io_in[12]
    DIRECTION INPUT ;
    USE SIGNAL ;
    PORT
      LAYER met3 ;
        RECT 2859.020000 2794.320000 2859.820000 2794.620000 ;
    END
  END io_in[12]
  PIN io_in[11]
    DIRECTION INPUT ;
    USE SIGNAL ;
    PORT
      LAYER met3 ;
        RECT 2859.020000 2528.360000 2859.820000 2528.660000 ;
    END
  END io_in[11]
  PIN io_in[10]
    DIRECTION INPUT ;
    USE SIGNAL ;
    PORT
      LAYER met3 ;
        RECT 2859.020000 2262.400000 2859.820000 2262.700000 ;
    END
  END io_in[10]
  PIN io_in[9]
    DIRECTION INPUT ;
    USE SIGNAL ;
    PORT
      LAYER met3 ;
        RECT 2859.020000 1996.440000 2859.820000 1996.740000 ;
    END
  END io_in[9]
  PIN io_in[8]
    DIRECTION INPUT ;
    USE SIGNAL ;
    PORT
      LAYER met3 ;
        RECT 2859.020000 1730.480000 2859.820000 1730.780000 ;
    END
  END io_in[8]
  PIN io_in[7]
    DIRECTION INPUT ;
    USE SIGNAL ;
    PORT
      LAYER met3 ;
        RECT 2859.020000 1463.910000 2859.820000 1464.210000 ;
    END
  END io_in[7]
  PIN io_in[6]
    DIRECTION INPUT ;
    USE SIGNAL ;
    PORT
      LAYER met3 ;
        RECT 2859.020000 1197.950000 2859.820000 1198.250000 ;
    END
  END io_in[6]
  PIN io_in[5]
    DIRECTION INPUT ;
    USE SIGNAL ;
    PORT
      LAYER met3 ;
        RECT 2859.020000 998.480000 2859.820000 998.780000 ;
    END
  END io_in[5]
  PIN io_in[4]
    DIRECTION INPUT ;
    USE SIGNAL ;
    PORT
      LAYER met3 ;
        RECT 2859.020000 799.010000 2859.820000 799.310000 ;
    END
  END io_in[4]
  PIN io_in[3]
    DIRECTION INPUT ;
    USE SIGNAL ;
    PORT
      LAYER met3 ;
        RECT 2859.020000 599.540000 2859.820000 599.840000 ;
    END
  END io_in[3]
  PIN io_in[2]
    DIRECTION INPUT ;
    USE SIGNAL ;
    PORT
      LAYER met3 ;
        RECT 2859.020000 400.070000 2859.820000 400.370000 ;
    END
  END io_in[2]
  PIN io_in[1]
    DIRECTION INPUT ;
    USE SIGNAL ;
    PORT
      LAYER met3 ;
        RECT 2859.020000 200.600000 2859.820000 200.900000 ;
    END
  END io_in[1]
  PIN io_in[0]
    DIRECTION INPUT ;
    USE SIGNAL ;
    PORT
      LAYER met3 ;
        RECT 2859.020000 0.520000 2859.820000 0.820000 ;
    END
  END io_in[0]
  PIN io_out[37]
    DIRECTION OUTPUT ;
    USE SIGNAL ;
    ANTENNADIFFAREA 0.336 LAYER met3  ;
    ANTENNAPARTIALMETALAREA 0.1644 LAYER met3  ;
    ANTENNAPARTIALMETALSIDEAREA 0.872 LAYER met3  ;
    PORT
      LAYER met3 ;
        RECT 0.000000 65.180000 0.800000 65.480000 ;
    END
  END io_out[37]
  PIN io_out[36]
    DIRECTION OUTPUT ;
    USE SIGNAL ;
    ANTENNADIFFAREA 0.336 LAYER met3  ;
    ANTENNAPARTIALMETALAREA 0.1644 LAYER met3  ;
    ANTENNAPARTIALMETALSIDEAREA 0.872 LAYER met3  ;
    PORT
      LAYER met3 ;
        RECT 0.000000 260.990000 0.800000 261.290000 ;
    END
  END io_out[36]
  PIN io_out[35]
    DIRECTION OUTPUT ;
    USE SIGNAL ;
    ANTENNADIFFAREA 0.336 LAYER met3  ;
    ANTENNAPARTIALMETALAREA 0.1644 LAYER met3  ;
    ANTENNAPARTIALMETALSIDEAREA 0.872 LAYER met3  ;
    PORT
      LAYER met3 ;
        RECT 0.000000 456.800000 0.800000 457.100000 ;
    END
  END io_out[35]
  PIN io_out[34]
    DIRECTION OUTPUT ;
    USE SIGNAL ;
    ANTENNADIFFAREA 0.336 LAYER met3  ;
    ANTENNAPARTIALMETALAREA 0.1644 LAYER met3  ;
    ANTENNAPARTIALMETALSIDEAREA 0.872 LAYER met3  ;
    PORT
      LAYER met3 ;
        RECT 0.000000 717.880000 0.800000 718.180000 ;
    END
  END io_out[34]
  PIN io_out[33]
    DIRECTION OUTPUT ;
    USE SIGNAL ;
    ANTENNADIFFAREA 0.336 LAYER met3  ;
    ANTENNAPARTIALMETALAREA 0.1644 LAYER met3  ;
    ANTENNAPARTIALMETALSIDEAREA 0.872 LAYER met3  ;
    PORT
      LAYER met3 ;
        RECT 0.000000 978.960000 0.800000 979.260000 ;
    END
  END io_out[33]
  PIN io_out[32]
    DIRECTION OUTPUT ;
    USE SIGNAL ;
    ANTENNADIFFAREA 0.336 LAYER met3  ;
    ANTENNAPARTIALMETALAREA 8.8584 LAYER met3  ;
    ANTENNAPARTIALMETALSIDEAREA 47.24 LAYER met3  ;
    PORT
      LAYER met3 ;
        RECT 0.000000 1240.040000 0.800000 1240.340000 ;
    END
  END io_out[32]
  PIN io_out[31]
    DIRECTION OUTPUT ;
    USE SIGNAL ;
    ANTENNADIFFAREA 0.336 LAYER met3  ;
    ANTENNAPARTIALMETALAREA 0.1644 LAYER met3  ;
    ANTENNAPARTIALMETALSIDEAREA 0.872 LAYER met3  ;
    PORT
      LAYER met3 ;
        RECT 0.000000 1501.120000 0.800000 1501.420000 ;
    END
  END io_out[31]
  PIN io_out[30]
    DIRECTION OUTPUT ;
    USE SIGNAL ;
    ANTENNADIFFAREA 0.336 LAYER met3  ;
    ANTENNAPARTIALMETALAREA 0.9924 LAYER met3  ;
    ANTENNAPARTIALMETALSIDEAREA 5.288 LAYER met3  ;
    PORT
      LAYER met3 ;
        RECT 0.000000 1762.200000 0.800000 1762.500000 ;
    END
  END io_out[30]
  PIN io_out[29]
    DIRECTION OUTPUT ;
    USE SIGNAL ;
    ANTENNADIFFAREA 0.336 LAYER met3  ;
    ANTENNAPARTIALMETALAREA 1.5444 LAYER met3  ;
    ANTENNAPARTIALMETALSIDEAREA 8.232 LAYER met3  ;
    PORT
      LAYER met3 ;
        RECT 0.000000 2023.280000 0.800000 2023.580000 ;
    END
  END io_out[29]
  PIN io_out[28]
    DIRECTION OUTPUT ;
    USE SIGNAL ;
    ANTENNADIFFAREA 0.336 LAYER met3  ;
    ANTENNAPARTIALMETALAREA 8.5824 LAYER met3  ;
    ANTENNAPARTIALMETALSIDEAREA 45.768 LAYER met3  ;
    PORT
      LAYER met3 ;
        RECT 0.000000 2284.360000 0.800000 2284.660000 ;
    END
  END io_out[28]
  PIN io_out[27]
    DIRECTION OUTPUT ;
    USE SIGNAL ;
    ANTENNADIFFAREA 0.336 LAYER met3  ;
    ANTENNAPARTIALMETALAREA 0.4404 LAYER met3  ;
    ANTENNAPARTIALMETALSIDEAREA 2.344 LAYER met3  ;
    PORT
      LAYER met3 ;
        RECT 0.000000 2545.440000 0.800000 2545.740000 ;
    END
  END io_out[27]
  PIN io_out[26]
    DIRECTION OUTPUT ;
    USE SIGNAL ;
    ANTENNADIFFAREA 0.336 LAYER met3  ;
    ANTENNAPARTIALMETALAREA 8.5824 LAYER met3  ;
    ANTENNAPARTIALMETALSIDEAREA 45.768 LAYER met3  ;
    PORT
      LAYER met3 ;
        RECT 0.000000 2806.520000 0.800000 2806.820000 ;
    END
  END io_out[26]
  PIN io_out[25]
    DIRECTION OUTPUT ;
    USE SIGNAL ;
    ANTENNADIFFAREA 0.336 LAYER met3  ;
    ANTENNAPARTIALMETALAREA 8.5824 LAYER met3  ;
    ANTENNAPARTIALMETALSIDEAREA 45.768 LAYER met3  ;
    PORT
      LAYER met3 ;
        RECT 0.000000 3067.600000 0.800000 3067.900000 ;
    END
  END io_out[25]
  PIN io_out[24]
    DIRECTION OUTPUT ;
    USE SIGNAL ;
    ANTENNADIFFAREA 0.336 LAYER met3  ;
    ANTENNAPARTIALMETALAREA 8.1684 LAYER met3  ;
    ANTENNAPARTIALMETALSIDEAREA 43.56 LAYER met3  ;
    PORT
      LAYER met3 ;
        RECT 0.000000 3328.680000 0.800000 3328.980000 ;
    END
  END io_out[24]
  PIN io_out[23]
    DIRECTION OUTPUT ;
    USE SIGNAL ;
    ANTENNADIFFAREA 0.336 LAYER met2  ;
    ANTENNAPARTIALMETALAREA 4.0627 LAYER met2  ;
    ANTENNAPARTIALMETALSIDEAREA 20.2055 LAYER met2  ;
    PORT
      LAYER met2 ;
        RECT 81.580000 3459.355000 81.720000 3459.840000 ;
    END
  END io_out[23]
  PIN io_out[22]
    DIRECTION OUTPUT ;
    USE SIGNAL ;
    ANTENNADIFFAREA 0.336 LAYER met2  ;
    ANTENNAPARTIALMETALAREA 4.0627 LAYER met2  ;
    ANTENNAPARTIALMETALSIDEAREA 20.2055 LAYER met2  ;
    PORT
      LAYER met2 ;
        RECT 408.640000 3459.355000 408.780000 3459.840000 ;
    END
  END io_out[22]
  PIN io_out[21]
    DIRECTION OUTPUT ;
    USE SIGNAL ;
    ANTENNADIFFAREA 0.336 LAYER met2  ;
    ANTENNAPARTIALMETALAREA 4.0627 LAYER met2  ;
    ANTENNAPARTIALMETALSIDEAREA 20.2055 LAYER met2  ;
    PORT
      LAYER met2 ;
        RECT 735.240000 3459.355000 735.380000 3459.840000 ;
    END
  END io_out[21]
  PIN io_out[20]
    DIRECTION OUTPUT ;
    USE SIGNAL ;
    ANTENNADIFFAREA 0.336 LAYER met2  ;
    ANTENNAPARTIALMETALAREA 4.0627 LAYER met2  ;
    ANTENNAPARTIALMETALSIDEAREA 20.2055 LAYER met2  ;
    PORT
      LAYER met2 ;
        RECT 1061.840000 3459.355000 1061.980000 3459.840000 ;
    END
  END io_out[20]
  PIN io_out[19]
    DIRECTION OUTPUT ;
    USE SIGNAL ;
    ANTENNADIFFAREA 0.336 LAYER met2  ;
    ANTENNAPARTIALMETALAREA 4.3847 LAYER met2  ;
    ANTENNAPARTIALMETALSIDEAREA 21.8155 LAYER met2  ;
    PORT
      LAYER met2 ;
        RECT 1388.900000 3459.355000 1389.040000 3459.840000 ;
    END
  END io_out[19]
  PIN io_out[18]
    DIRECTION OUTPUT ;
    USE SIGNAL ;
    ANTENNADIFFAREA 0.336 LAYER met2  ;
    ANTENNAPARTIALMETALAREA 4.0627 LAYER met2  ;
    ANTENNAPARTIALMETALSIDEAREA 20.2055 LAYER met2  ;
    PORT
      LAYER met2 ;
        RECT 1715.500000 3459.355000 1715.640000 3459.840000 ;
    END
  END io_out[18]
  PIN io_out[17]
    DIRECTION OUTPUT ;
    USE SIGNAL ;
    ANTENNADIFFAREA 0.336 LAYER met2  ;
    ANTENNAPARTIALMETALAREA 4.0627 LAYER met2  ;
    ANTENNAPARTIALMETALSIDEAREA 20.2055 LAYER met2  ;
    PORT
      LAYER met2 ;
        RECT 2042.100000 3459.355000 2042.240000 3459.840000 ;
    END
  END io_out[17]
  PIN io_out[16]
    DIRECTION OUTPUT ;
    USE SIGNAL ;
    ANTENNADIFFAREA 0.336 LAYER met2  ;
    ANTENNAPARTIALMETALAREA 4.0627 LAYER met2  ;
    ANTENNAPARTIALMETALSIDEAREA 20.2055 LAYER met2  ;
    PORT
      LAYER met2 ;
        RECT 2369.160000 3459.355000 2369.300000 3459.840000 ;
    END
  END io_out[16]
  PIN io_out[15]
    DIRECTION OUTPUT ;
    USE SIGNAL ;
    ANTENNADIFFAREA 0.336 LAYER met2  ;
    ANTENNAPARTIALMETALAREA 4.0627 LAYER met2  ;
    ANTENNAPARTIALMETALSIDEAREA 20.2055 LAYER met2  ;
    PORT
      LAYER met2 ;
        RECT 2695.760000 3459.355000 2695.900000 3459.840000 ;
    END
  END io_out[15]
  PIN io_out[14]
    DIRECTION OUTPUT ;
    USE SIGNAL ;
    ANTENNADIFFAREA 0.336 LAYER met3  ;
    ANTENNAPARTIALMETALAREA 8.8584 LAYER met3  ;
    ANTENNAPARTIALMETALSIDEAREA 47.24 LAYER met3  ;
    PORT
      LAYER met3 ;
        RECT 2859.020000 3392.730000 2859.820000 3393.030000 ;
    END
  END io_out[14]
  PIN io_out[13]
    DIRECTION OUTPUT ;
    USE SIGNAL ;
    ANTENNADIFFAREA 0.336 LAYER met3  ;
    ANTENNAPARTIALMETALAREA 0.1644 LAYER met3  ;
    ANTENNAPARTIALMETALSIDEAREA 0.872 LAYER met3  ;
    PORT
      LAYER met3 ;
        RECT 2859.020000 3126.770000 2859.820000 3127.070000 ;
    END
  END io_out[13]
  PIN io_out[12]
    DIRECTION OUTPUT ;
    USE SIGNAL ;
    ANTENNADIFFAREA 0.336 LAYER met3  ;
    ANTENNAPARTIALMETALAREA 8.8584 LAYER met3  ;
    ANTENNAPARTIALMETALSIDEAREA 47.24 LAYER met3  ;
    PORT
      LAYER met3 ;
        RECT 2859.020000 2860.810000 2859.820000 2861.110000 ;
    END
  END io_out[12]
  PIN io_out[11]
    DIRECTION OUTPUT ;
    USE SIGNAL ;
    ANTENNADIFFAREA 0.336 LAYER met3  ;
    ANTENNAPARTIALMETALAREA 0.1644 LAYER met3  ;
    ANTENNAPARTIALMETALSIDEAREA 0.872 LAYER met3  ;
    PORT
      LAYER met3 ;
        RECT 2859.020000 2594.850000 2859.820000 2595.150000 ;
    END
  END io_out[11]
  PIN io_out[10]
    DIRECTION OUTPUT ;
    USE SIGNAL ;
    ANTENNADIFFAREA 0.336 LAYER met3  ;
    ANTENNAPARTIALMETALAREA 0.1644 LAYER met3  ;
    ANTENNAPARTIALMETALSIDEAREA 0.872 LAYER met3  ;
    PORT
      LAYER met3 ;
        RECT 2859.020000 2328.890000 2859.820000 2329.190000 ;
    END
  END io_out[10]
  PIN io_out[9]
    DIRECTION OUTPUT ;
    USE SIGNAL ;
    ANTENNADIFFAREA 0.336 LAYER met3  ;
    ANTENNAPARTIALMETALAREA 8.8584 LAYER met3  ;
    ANTENNAPARTIALMETALSIDEAREA 47.24 LAYER met3  ;
    PORT
      LAYER met3 ;
        RECT 2859.020000 2062.930000 2859.820000 2063.230000 ;
    END
  END io_out[9]
  PIN io_out[8]
    DIRECTION OUTPUT ;
    USE SIGNAL ;
    ANTENNADIFFAREA 0.336 LAYER met3  ;
    ANTENNAPARTIALMETALAREA 0.1644 LAYER met3  ;
    ANTENNAPARTIALMETALSIDEAREA 0.872 LAYER met3  ;
    PORT
      LAYER met3 ;
        RECT 2859.020000 1796.970000 2859.820000 1797.270000 ;
    END
  END io_out[8]
  PIN io_out[7]
    DIRECTION OUTPUT ;
    USE SIGNAL ;
    ANTENNADIFFAREA 0.336 LAYER met3  ;
    ANTENNAPARTIALMETALAREA 0.1644 LAYER met3  ;
    ANTENNAPARTIALMETALSIDEAREA 0.872 LAYER met3  ;
    PORT
      LAYER met3 ;
        RECT 2859.020000 1530.400000 2859.820000 1530.700000 ;
    END
  END io_out[7]
  PIN io_out[6]
    DIRECTION OUTPUT ;
    USE SIGNAL ;
    ANTENNADIFFAREA 0.336 LAYER met3  ;
    ANTENNAPARTIALMETALAREA 0.1644 LAYER met3  ;
    ANTENNAPARTIALMETALSIDEAREA 0.872 LAYER met3  ;
    PORT
      LAYER met3 ;
        RECT 2859.020000 1264.440000 2859.820000 1264.740000 ;
    END
  END io_out[6]
  PIN io_out[5]
    DIRECTION OUTPUT ;
    USE SIGNAL ;
    ANTENNADIFFAREA 0.336 LAYER met3  ;
    ANTENNAPARTIALMETALAREA 8.8584 LAYER met3  ;
    ANTENNAPARTIALMETALSIDEAREA 47.24 LAYER met3  ;
    PORT
      LAYER met3 ;
        RECT 2859.020000 1064.970000 2859.820000 1065.270000 ;
    END
  END io_out[5]
  PIN io_out[4]
    DIRECTION OUTPUT ;
    USE SIGNAL ;
    ANTENNADIFFAREA 0.336 LAYER met3  ;
    ANTENNAPARTIALMETALAREA 8.8584 LAYER met3  ;
    ANTENNAPARTIALMETALSIDEAREA 47.24 LAYER met3  ;
    PORT
      LAYER met3 ;
        RECT 2859.020000 865.500000 2859.820000 865.800000 ;
    END
  END io_out[4]
  PIN io_out[3]
    DIRECTION OUTPUT ;
    USE SIGNAL ;
    ANTENNADIFFAREA 0.336 LAYER met3  ;
    ANTENNAPARTIALMETALAREA 0.1644 LAYER met3  ;
    ANTENNAPARTIALMETALSIDEAREA 0.872 LAYER met3  ;
    PORT
      LAYER met3 ;
        RECT 2859.020000 666.030000 2859.820000 666.330000 ;
    END
  END io_out[3]
  PIN io_out[2]
    DIRECTION OUTPUT ;
    USE SIGNAL ;
    ANTENNADIFFAREA 0.336 LAYER met3  ;
    ANTENNAPARTIALMETALAREA 0.1644 LAYER met3  ;
    ANTENNAPARTIALMETALSIDEAREA 0.872 LAYER met3  ;
    PORT
      LAYER met3 ;
        RECT 2859.020000 466.560000 2859.820000 466.860000 ;
    END
  END io_out[2]
  PIN io_out[1]
    DIRECTION OUTPUT ;
    USE SIGNAL ;
    ANTENNADIFFAREA 0.336 LAYER met3  ;
    ANTENNAPARTIALMETALAREA 8.8584 LAYER met3  ;
    ANTENNAPARTIALMETALSIDEAREA 47.24 LAYER met3  ;
    PORT
      LAYER met3 ;
        RECT 2859.020000 267.090000 2859.820000 267.390000 ;
    END
  END io_out[1]
  PIN io_out[0]
    DIRECTION OUTPUT ;
    USE SIGNAL ;
    ANTENNADIFFAREA 0.336 LAYER met3  ;
    ANTENNAPARTIALMETALAREA 0.1644 LAYER met3  ;
    ANTENNAPARTIALMETALSIDEAREA 0.872 LAYER met3  ;
    PORT
      LAYER met3 ;
        RECT 2859.020000 67.620000 2859.820000 67.920000 ;
    END
  END io_out[0]
  PIN io_oeb[37]
    DIRECTION OUTPUT ;
    USE SIGNAL ;
    ANTENNADIFFAREA 0.336 LAYER met3  ;
    ANTENNAPARTIALMETALAREA 9.1344 LAYER met3  ;
    ANTENNAPARTIALMETALSIDEAREA 48.712 LAYER met3  ;
    PORT
      LAYER met3 ;
        RECT 0.000000 0.520000 0.800000 0.820000 ;
    END
  END io_oeb[37]
  PIN io_oeb[36]
    DIRECTION OUTPUT ;
    USE SIGNAL ;
    ANTENNADIFFAREA 0.336 LAYER met3  ;
    ANTENNAPARTIALMETALAREA 0.3024 LAYER met3  ;
    ANTENNAPARTIALMETALSIDEAREA 1.608 LAYER met3  ;
    PORT
      LAYER met3 ;
        RECT 0.000000 195.720000 0.800000 196.020000 ;
    END
  END io_oeb[36]
  PIN io_oeb[35]
    DIRECTION OUTPUT ;
    USE SIGNAL ;
    ANTENNADIFFAREA 0.336 LAYER met3  ;
    ANTENNAPARTIALMETALAREA 8.3064 LAYER met3  ;
    ANTENNAPARTIALMETALSIDEAREA 44.296 LAYER met3  ;
    PORT
      LAYER met3 ;
        RECT 0.000000 391.530000 0.800000 391.830000 ;
    END
  END io_oeb[35]
  PIN io_oeb[34]
    DIRECTION OUTPUT ;
    USE SIGNAL ;
    ANTENNADIFFAREA 0.336 LAYER met3  ;
    ANTENNAPARTIALMETALAREA 8.8584 LAYER met3  ;
    ANTENNAPARTIALMETALSIDEAREA 47.24 LAYER met3  ;
    PORT
      LAYER met3 ;
        RECT 0.000000 652.610000 0.800000 652.910000 ;
    END
  END io_oeb[34]
  PIN io_oeb[33]
    DIRECTION OUTPUT ;
    USE SIGNAL ;
    ANTENNADIFFAREA 0.336 LAYER met3  ;
    ANTENNAPARTIALMETALAREA 0.1644 LAYER met3  ;
    ANTENNAPARTIALMETALSIDEAREA 0.872 LAYER met3  ;
    PORT
      LAYER met3 ;
        RECT 0.000000 913.690000 0.800000 913.990000 ;
    END
  END io_oeb[33]
  PIN io_oeb[32]
    DIRECTION OUTPUT ;
    USE SIGNAL ;
    ANTENNADIFFAREA 0.336 LAYER met3  ;
    ANTENNAPARTIALMETALAREA 8.8584 LAYER met3  ;
    ANTENNAPARTIALMETALSIDEAREA 47.24 LAYER met3  ;
    PORT
      LAYER met3 ;
        RECT 0.000000 1174.770000 0.800000 1175.070000 ;
    END
  END io_oeb[32]
  PIN io_oeb[31]
    DIRECTION OUTPUT ;
    USE SIGNAL ;
    ANTENNADIFFAREA 0.336 LAYER met3  ;
    ANTENNAPARTIALMETALAREA 8.8584 LAYER met3  ;
    ANTENNAPARTIALMETALSIDEAREA 47.24 LAYER met3  ;
    PORT
      LAYER met3 ;
        RECT 0.000000 1435.850000 0.800000 1436.150000 ;
    END
  END io_oeb[31]
  PIN io_oeb[30]
    DIRECTION OUTPUT ;
    USE SIGNAL ;
    ANTENNADIFFAREA 0.336 LAYER met3  ;
    ANTENNAPARTIALMETALAREA 8.5824 LAYER met3  ;
    ANTENNAPARTIALMETALSIDEAREA 45.768 LAYER met3  ;
    PORT
      LAYER met3 ;
        RECT 0.000000 1696.930000 0.800000 1697.230000 ;
    END
  END io_oeb[30]
  PIN io_oeb[29]
    DIRECTION OUTPUT ;
    USE SIGNAL ;
    ANTENNADIFFAREA 0.336 LAYER met3  ;
    ANTENNAPARTIALMETALAREA 8.8584 LAYER met3  ;
    ANTENNAPARTIALMETALSIDEAREA 47.24 LAYER met3  ;
    PORT
      LAYER met3 ;
        RECT 0.000000 1958.010000 0.800000 1958.310000 ;
    END
  END io_oeb[29]
  PIN io_oeb[28]
    DIRECTION OUTPUT ;
    USE SIGNAL ;
    ANTENNADIFFAREA 0.336 LAYER met3  ;
    ANTENNAPARTIALMETALAREA 1.5444 LAYER met3  ;
    ANTENNAPARTIALMETALSIDEAREA 8.232 LAYER met3  ;
    PORT
      LAYER met3 ;
        RECT 0.000000 2219.090000 0.800000 2219.390000 ;
    END
  END io_oeb[28]
  PIN io_oeb[27]
    DIRECTION OUTPUT ;
    USE SIGNAL ;
    ANTENNADIFFAREA 0.336 LAYER met3  ;
    ANTENNAPARTIALMETALAREA 8.5824 LAYER met3  ;
    ANTENNAPARTIALMETALSIDEAREA 45.768 LAYER met3  ;
    PORT
      LAYER met3 ;
        RECT 0.000000 2480.170000 0.800000 2480.470000 ;
    END
  END io_oeb[27]
  PIN io_oeb[26]
    DIRECTION OUTPUT ;
    USE SIGNAL ;
    ANTENNADIFFAREA 0.336 LAYER met3  ;
    ANTENNAPARTIALMETALAREA 0.4404 LAYER met3  ;
    ANTENNAPARTIALMETALSIDEAREA 2.344 LAYER met3  ;
    PORT
      LAYER met3 ;
        RECT 0.000000 2741.250000 0.800000 2741.550000 ;
    END
  END io_oeb[26]
  PIN io_oeb[25]
    DIRECTION OUTPUT ;
    USE SIGNAL ;
    ANTENNADIFFAREA 0.336 LAYER met3  ;
    ANTENNAPARTIALMETALAREA 8.5824 LAYER met3  ;
    ANTENNAPARTIALMETALSIDEAREA 45.768 LAYER met3  ;
    PORT
      LAYER met3 ;
        RECT 0.000000 3002.330000 0.800000 3002.630000 ;
    END
  END io_oeb[25]
  PIN io_oeb[24]
    DIRECTION OUTPUT ;
    USE SIGNAL ;
    ANTENNADIFFAREA 0.336 LAYER met3  ;
    ANTENNAPARTIALMETALAREA 8.5824 LAYER met3  ;
    ANTENNAPARTIALMETALSIDEAREA 45.768 LAYER met3  ;
    PORT
      LAYER met3 ;
        RECT 0.000000 3263.410000 0.800000 3263.710000 ;
    END
  END io_oeb[24]
  PIN io_oeb[23]
    DIRECTION OUTPUT ;
    USE SIGNAL ;
    ANTENNADIFFAREA 0.336 LAYER met2  ;
    ANTENNAPARTIALMETALAREA 4.1103 LAYER met2  ;
    ANTENNAPARTIALMETALSIDEAREA 20.4435 LAYER met2  ;
    PORT
      LAYER met2 ;
        RECT 0.160000 3459.355000 0.300000 3459.840000 ;
    END
  END io_oeb[23]
  PIN io_oeb[22]
    DIRECTION OUTPUT ;
    USE SIGNAL ;
    ANTENNADIFFAREA 0.336 LAYER met2  ;
    ANTENNAPARTIALMETALAREA 4.0627 LAYER met2  ;
    ANTENNAPARTIALMETALSIDEAREA 20.2055 LAYER met2  ;
    PORT
      LAYER met2 ;
        RECT 326.760000 3459.355000 326.900000 3459.840000 ;
    END
  END io_oeb[22]
  PIN io_oeb[21]
    DIRECTION OUTPUT ;
    USE SIGNAL ;
    ANTENNADIFFAREA 0.336 LAYER met2  ;
    ANTENNAPARTIALMETALAREA 4.0627 LAYER met2  ;
    ANTENNAPARTIALMETALSIDEAREA 20.2055 LAYER met2  ;
    PORT
      LAYER met2 ;
        RECT 653.360000 3459.355000 653.500000 3459.840000 ;
    END
  END io_oeb[21]
  PIN io_oeb[20]
    DIRECTION OUTPUT ;
    USE SIGNAL ;
    ANTENNADIFFAREA 0.336 LAYER met2  ;
    ANTENNAPARTIALMETALAREA 4.0627 LAYER met2  ;
    ANTENNAPARTIALMETALSIDEAREA 20.2055 LAYER met2  ;
    PORT
      LAYER met2 ;
        RECT 980.420000 3459.355000 980.560000 3459.840000 ;
    END
  END io_oeb[20]
  PIN io_oeb[19]
    DIRECTION OUTPUT ;
    USE SIGNAL ;
    ANTENNADIFFAREA 0.336 LAYER met2  ;
    ANTENNAPARTIALMETALAREA 4.0627 LAYER met2  ;
    ANTENNAPARTIALMETALSIDEAREA 20.2055 LAYER met2  ;
    PORT
      LAYER met2 ;
        RECT 1307.020000 3459.355000 1307.160000 3459.840000 ;
    END
  END io_oeb[19]
  PIN io_oeb[18]
    DIRECTION OUTPUT ;
    USE SIGNAL ;
    ANTENNADIFFAREA 0.336 LAYER met2  ;
    ANTENNAPARTIALMETALAREA 4.0627 LAYER met2  ;
    ANTENNAPARTIALMETALSIDEAREA 20.2055 LAYER met2  ;
    PORT
      LAYER met2 ;
        RECT 1633.620000 3459.355000 1633.760000 3459.840000 ;
    END
  END io_oeb[18]
  PIN io_oeb[17]
    DIRECTION OUTPUT ;
    USE SIGNAL ;
    ANTENNADIFFAREA 0.336 LAYER met2  ;
    ANTENNAPARTIALMETALAREA 4.0627 LAYER met2  ;
    ANTENNAPARTIALMETALSIDEAREA 20.2055 LAYER met2  ;
    PORT
      LAYER met2 ;
        RECT 1960.680000 3459.355000 1960.820000 3459.840000 ;
    END
  END io_oeb[17]
  PIN io_oeb[16]
    DIRECTION OUTPUT ;
    USE SIGNAL ;
    ANTENNADIFFAREA 0.336 LAYER met2  ;
    ANTENNAPARTIALMETALAREA 4.0627 LAYER met2  ;
    ANTENNAPARTIALMETALSIDEAREA 20.2055 LAYER met2  ;
    PORT
      LAYER met2 ;
        RECT 2287.280000 3459.355000 2287.420000 3459.840000 ;
    END
  END io_oeb[16]
  PIN io_oeb[15]
    DIRECTION OUTPUT ;
    USE SIGNAL ;
    ANTENNADIFFAREA 0.336 LAYER met2  ;
    ANTENNAPARTIALMETALAREA 4.0627 LAYER met2  ;
    ANTENNAPARTIALMETALSIDEAREA 20.2055 LAYER met2  ;
    PORT
      LAYER met2 ;
        RECT 2614.340000 3459.355000 2614.480000 3459.840000 ;
    END
  END io_oeb[15]
  PIN io_oeb[14]
    DIRECTION OUTPUT ;
    USE SIGNAL ;
    ANTENNADIFFAREA 0.336 LAYER met3  ;
    ANTENNAPARTIALMETALAREA 8.8584 LAYER met3  ;
    ANTENNAPARTIALMETALSIDEAREA 47.24 LAYER met3  ;
    PORT
      LAYER met3 ;
        RECT 2859.020000 3459.220000 2859.820000 3459.520000 ;
    END
  END io_oeb[14]
  PIN io_oeb[13]
    DIRECTION OUTPUT ;
    USE SIGNAL ;
    ANTENNADIFFAREA 0.336 LAYER met3  ;
    ANTENNAPARTIALMETALAREA 0.1644 LAYER met3  ;
    ANTENNAPARTIALMETALSIDEAREA 0.872 LAYER met3  ;
    PORT
      LAYER met3 ;
        RECT 2859.020000 3193.260000 2859.820000 3193.560000 ;
    END
  END io_oeb[13]
  PIN io_oeb[12]
    DIRECTION OUTPUT ;
    USE SIGNAL ;
    ANTENNADIFFAREA 0.336 LAYER met3  ;
    ANTENNAPARTIALMETALAREA 8.8584 LAYER met3  ;
    ANTENNAPARTIALMETALSIDEAREA 47.24 LAYER met3  ;
    PORT
      LAYER met3 ;
        RECT 2859.020000 2927.300000 2859.820000 2927.600000 ;
    END
  END io_oeb[12]
  PIN io_oeb[11]
    DIRECTION OUTPUT ;
    USE SIGNAL ;
    ANTENNADIFFAREA 0.336 LAYER met3  ;
    ANTENNAPARTIALMETALAREA 8.8584 LAYER met3  ;
    ANTENNAPARTIALMETALSIDEAREA 47.24 LAYER met3  ;
    PORT
      LAYER met3 ;
        RECT 2859.020000 2661.340000 2859.820000 2661.640000 ;
    END
  END io_oeb[11]
  PIN io_oeb[10]
    DIRECTION OUTPUT ;
    USE SIGNAL ;
    ANTENNADIFFAREA 0.336 LAYER met3  ;
    ANTENNAPARTIALMETALAREA 0.1644 LAYER met3  ;
    ANTENNAPARTIALMETALSIDEAREA 0.872 LAYER met3  ;
    PORT
      LAYER met3 ;
        RECT 2859.020000 2395.380000 2859.820000 2395.680000 ;
    END
  END io_oeb[10]
  PIN io_oeb[9]
    DIRECTION OUTPUT ;
    USE SIGNAL ;
    ANTENNADIFFAREA 0.336 LAYER met3  ;
    ANTENNAPARTIALMETALAREA 0.1644 LAYER met3  ;
    ANTENNAPARTIALMETALSIDEAREA 0.872 LAYER met3  ;
    PORT
      LAYER met3 ;
        RECT 2859.020000 2129.420000 2859.820000 2129.720000 ;
    END
  END io_oeb[9]
  PIN io_oeb[8]
    DIRECTION OUTPUT ;
    USE SIGNAL ;
    ANTENNADIFFAREA 0.336 LAYER met3  ;
    ANTENNAPARTIALMETALAREA 8.8584 LAYER met3  ;
    ANTENNAPARTIALMETALSIDEAREA 47.24 LAYER met3  ;
    PORT
      LAYER met3 ;
        RECT 2859.020000 1863.460000 2859.820000 1863.760000 ;
    END
  END io_oeb[8]
  PIN io_oeb[7]
    DIRECTION OUTPUT ;
    USE SIGNAL ;
    ANTENNADIFFAREA 0.336 LAYER met3  ;
    ANTENNAPARTIALMETALAREA 8.8584 LAYER met3  ;
    ANTENNAPARTIALMETALSIDEAREA 47.24 LAYER met3  ;
    PORT
      LAYER met3 ;
        RECT 2859.020000 1596.890000 2859.820000 1597.190000 ;
    END
  END io_oeb[7]
  PIN io_oeb[6]
    DIRECTION OUTPUT ;
    USE SIGNAL ;
    ANTENNADIFFAREA 0.336 LAYER met3  ;
    ANTENNAPARTIALMETALAREA 8.8584 LAYER met3  ;
    ANTENNAPARTIALMETALSIDEAREA 47.24 LAYER met3  ;
    PORT
      LAYER met3 ;
        RECT 2859.020000 1330.930000 2859.820000 1331.230000 ;
    END
  END io_oeb[6]
  PIN io_oeb[5]
    DIRECTION OUTPUT ;
    USE SIGNAL ;
    ANTENNADIFFAREA 0.336 LAYER met3  ;
    ANTENNAPARTIALMETALAREA 0.1644 LAYER met3  ;
    ANTENNAPARTIALMETALSIDEAREA 0.872 LAYER met3  ;
    PORT
      LAYER met3 ;
        RECT 2859.020000 1131.460000 2859.820000 1131.760000 ;
    END
  END io_oeb[5]
  PIN io_oeb[4]
    DIRECTION OUTPUT ;
    USE SIGNAL ;
    ANTENNADIFFAREA 0.336 LAYER met3  ;
    ANTENNAPARTIALMETALAREA 0.1644 LAYER met3  ;
    ANTENNAPARTIALMETALSIDEAREA 0.872 LAYER met3  ;
    PORT
      LAYER met3 ;
        RECT 2859.020000 931.990000 2859.820000 932.290000 ;
    END
  END io_oeb[4]
  PIN io_oeb[3]
    DIRECTION OUTPUT ;
    USE SIGNAL ;
    ANTENNADIFFAREA 0.336 LAYER met3  ;
    ANTENNAPARTIALMETALAREA 8.8584 LAYER met3  ;
    ANTENNAPARTIALMETALSIDEAREA 47.24 LAYER met3  ;
    PORT
      LAYER met3 ;
        RECT 2859.020000 732.520000 2859.820000 732.820000 ;
    END
  END io_oeb[3]
  PIN io_oeb[2]
    DIRECTION OUTPUT ;
    USE SIGNAL ;
    ANTENNADIFFAREA 0.336 LAYER met3  ;
    ANTENNAPARTIALMETALAREA 0.1644 LAYER met3  ;
    ANTENNAPARTIALMETALSIDEAREA 0.872 LAYER met3  ;
    PORT
      LAYER met3 ;
        RECT 2859.020000 533.050000 2859.820000 533.350000 ;
    END
  END io_oeb[2]
  PIN io_oeb[1]
    DIRECTION OUTPUT ;
    USE SIGNAL ;
    ANTENNADIFFAREA 0.336 LAYER met3  ;
    ANTENNAPARTIALMETALAREA 0.1644 LAYER met3  ;
    ANTENNAPARTIALMETALSIDEAREA 0.872 LAYER met3  ;
    PORT
      LAYER met3 ;
        RECT 2859.020000 333.580000 2859.820000 333.880000 ;
    END
  END io_oeb[1]
  PIN io_oeb[0]
    DIRECTION OUTPUT ;
    USE SIGNAL ;
    ANTENNADIFFAREA 0.336 LAYER met3  ;
    ANTENNAPARTIALMETALAREA 0.1644 LAYER met3  ;
    ANTENNAPARTIALMETALSIDEAREA 0.872 LAYER met3  ;
    PORT
      LAYER met3 ;
        RECT 2859.020000 134.110000 2859.820000 134.410000 ;
    END
  END io_oeb[0]
  PIN analog_io[28]
    DIRECTION INOUT ;
    USE SIGNAL ;
    PORT
      LAYER met3 ;
        RECT 0.000000 587.340000 0.800000 587.640000 ;
    END
  END analog_io[28]
  PIN analog_io[27]
    DIRECTION INOUT ;
    USE SIGNAL ;
    PORT
      LAYER met3 ;
        RECT 0.000000 848.420000 0.800000 848.720000 ;
    END
  END analog_io[27]
  PIN analog_io[26]
    DIRECTION INOUT ;
    USE SIGNAL ;
    PORT
      LAYER met3 ;
        RECT 0.000000 1109.500000 0.800000 1109.800000 ;
    END
  END analog_io[26]
  PIN analog_io[25]
    DIRECTION INOUT ;
    USE SIGNAL ;
    PORT
      LAYER met3 ;
        RECT 0.000000 1370.580000 0.800000 1370.880000 ;
    END
  END analog_io[25]
  PIN analog_io[24]
    DIRECTION INOUT ;
    USE SIGNAL ;
    PORT
      LAYER met3 ;
        RECT 0.000000 1631.660000 0.800000 1631.960000 ;
    END
  END analog_io[24]
  PIN analog_io[23]
    DIRECTION INOUT ;
    USE SIGNAL ;
    PORT
      LAYER met3 ;
        RECT 0.000000 1892.740000 0.800000 1893.040000 ;
    END
  END analog_io[23]
  PIN analog_io[22]
    DIRECTION INOUT ;
    USE SIGNAL ;
    PORT
      LAYER met3 ;
        RECT 0.000000 2153.820000 0.800000 2154.120000 ;
    END
  END analog_io[22]
  PIN analog_io[21]
    DIRECTION INOUT ;
    USE SIGNAL ;
    PORT
      LAYER met3 ;
        RECT 0.000000 2414.900000 0.800000 2415.200000 ;
    END
  END analog_io[21]
  PIN analog_io[20]
    DIRECTION INOUT ;
    USE SIGNAL ;
    PORT
      LAYER met3 ;
        RECT 0.000000 2675.980000 0.800000 2676.280000 ;
    END
  END analog_io[20]
  PIN analog_io[19]
    DIRECTION INOUT ;
    USE SIGNAL ;
    PORT
      LAYER met3 ;
        RECT 0.000000 2937.060000 0.800000 2937.360000 ;
    END
  END analog_io[19]
  PIN analog_io[18]
    DIRECTION INOUT ;
    USE SIGNAL ;
    PORT
      LAYER met3 ;
        RECT 0.000000 3198.140000 0.800000 3198.440000 ;
    END
  END analog_io[18]
  PIN analog_io[17]
    DIRECTION INOUT ;
    USE SIGNAL ;
    PORT
      LAYER met3 ;
        RECT 0.000000 3458.610000 0.800000 3458.910000 ;
    END
  END analog_io[17]
  PIN analog_io[16]
    DIRECTION INOUT ;
    USE SIGNAL ;
    PORT
      LAYER met2 ;
        RECT 244.880000 3459.355000 245.020000 3459.840000 ;
    END
  END analog_io[16]
  PIN analog_io[15]
    DIRECTION INOUT ;
    USE SIGNAL ;
    PORT
      LAYER met2 ;
        RECT 571.940000 3459.355000 572.080000 3459.840000 ;
    END
  END analog_io[15]
  PIN analog_io[14]
    DIRECTION INOUT ;
    USE SIGNAL ;
    PORT
      LAYER met2 ;
        RECT 898.540000 3459.355000 898.680000 3459.840000 ;
    END
  END analog_io[14]
  PIN analog_io[13]
    DIRECTION INOUT ;
    USE SIGNAL ;
    PORT
      LAYER met2 ;
        RECT 1225.140000 3459.355000 1225.280000 3459.840000 ;
    END
  END analog_io[13]
  PIN analog_io[12]
    DIRECTION INOUT ;
    USE SIGNAL ;
    PORT
      LAYER met2 ;
        RECT 1552.200000 3459.355000 1552.340000 3459.840000 ;
    END
  END analog_io[12]
  PIN analog_io[11]
    DIRECTION INOUT ;
    USE SIGNAL ;
    PORT
      LAYER met2 ;
        RECT 1878.800000 3459.355000 1878.940000 3459.840000 ;
    END
  END analog_io[11]
  PIN analog_io[10]
    DIRECTION INOUT ;
    USE SIGNAL ;
    PORT
      LAYER met2 ;
        RECT 2205.860000 3459.355000 2206.000000 3459.840000 ;
    END
  END analog_io[10]
  PIN analog_io[9]
    DIRECTION INOUT ;
    USE SIGNAL ;
    PORT
      LAYER met2 ;
        RECT 2532.460000 3459.355000 2532.600000 3459.840000 ;
    END
  END analog_io[9]
  PIN analog_io[8]
    DIRECTION INOUT ;
    USE SIGNAL ;
    PORT
      LAYER met2 ;
        RECT 2859.520000 3459.355000 2859.660000 3459.840000 ;
    END
  END analog_io[8]
  PIN analog_io[7]
    DIRECTION INOUT ;
    USE SIGNAL ;
    PORT
      LAYER met3 ;
        RECT 2859.020000 3259.750000 2859.820000 3260.050000 ;
    END
  END analog_io[7]
  PIN analog_io[6]
    DIRECTION INOUT ;
    USE SIGNAL ;
    PORT
      LAYER met3 ;
        RECT 2859.020000 2993.790000 2859.820000 2994.090000 ;
    END
  END analog_io[6]
  PIN analog_io[5]
    DIRECTION INOUT ;
    USE SIGNAL ;
    PORT
      LAYER met3 ;
        RECT 2859.020000 2727.830000 2859.820000 2728.130000 ;
    END
  END analog_io[5]
  PIN analog_io[4]
    DIRECTION INOUT ;
    USE SIGNAL ;
    PORT
      LAYER met3 ;
        RECT 2859.020000 2461.870000 2859.820000 2462.170000 ;
    END
  END analog_io[4]
  PIN analog_io[3]
    DIRECTION INOUT ;
    USE SIGNAL ;
    PORT
      LAYER met3 ;
        RECT 2859.020000 2195.910000 2859.820000 2196.210000 ;
    END
  END analog_io[3]
  PIN analog_io[2]
    DIRECTION INOUT ;
    USE SIGNAL ;
    PORT
      LAYER met3 ;
        RECT 2859.020000 1929.950000 2859.820000 1930.250000 ;
    END
  END analog_io[2]
  PIN analog_io[1]
    DIRECTION INOUT ;
    USE SIGNAL ;
    PORT
      LAYER met3 ;
        RECT 2859.020000 1663.380000 2859.820000 1663.680000 ;
    END
  END analog_io[1]
  PIN analog_io[0]
    DIRECTION INOUT ;
    USE SIGNAL ;
    PORT
      LAYER met3 ;
        RECT 2859.020000 1397.420000 2859.820000 1397.720000 ;
    END
  END analog_io[0]
  PIN user_clock2
    DIRECTION INPUT ;
    USE SIGNAL ;
    PORT
      LAYER met2 ;
        RECT 2842.500000 0.000000 2842.640000 0.485000 ;
    END
  END user_clock2
  PIN user_irq[2]
    DIRECTION OUTPUT ;
    USE SIGNAL ;
    ANTENNADIFFAREA 0.336 LAYER met2  ;
    ANTENNAPARTIALMETALAREA 4.8719 LAYER met2  ;
    ANTENNAPARTIALMETALSIDEAREA 24.2515 LAYER met2  ;
    PORT
      LAYER met2 ;
        RECT 2859.520000 0.000000 2859.660000 0.485000 ;
    END
  END user_irq[2]
  PIN user_irq[1]
    DIRECTION OUTPUT ;
    USE SIGNAL ;
    ANTENNADIFFAREA 0.336 LAYER met2  ;
    ANTENNAPARTIALMETALAREA 4.4435 LAYER met2  ;
    ANTENNAPARTIALMETALSIDEAREA 22.1095 LAYER met2  ;
    PORT
      LAYER met2 ;
        RECT 2854.000000 0.000000 2854.140000 0.485000 ;
    END
  END user_irq[1]
  PIN user_irq[0]
    DIRECTION OUTPUT ;
    USE SIGNAL ;
    ANTENNADIFFAREA 0.336 LAYER met2  ;
    ANTENNAPARTIALMETALAREA 4.1579 LAYER met2  ;
    ANTENNAPARTIALMETALSIDEAREA 20.6815 LAYER met2  ;
    PORT
      LAYER met2 ;
        RECT 2848.020000 0.000000 2848.160000 0.485000 ;
    END
  END user_irq[0]
  PIN vssd1
    DIRECTION INOUT ;
    USE GROUND ;
    PORT
      LAYER met5 ;
        RECT 2851.660000 3447.600000 2859.820000 3455.760000 ;
    END
    PORT
      LAYER met5 ;
        RECT 0.000000 3447.600000 8.160000 3455.760000 ;
    END
    PORT
      LAYER met5 ;
        RECT 2851.660000 4.080000 2859.820000 12.240000 ;
    END
    PORT
      LAYER met5 ;
        RECT 0.000000 4.080000 8.160000 12.240000 ;
    END
    PORT
      LAYER met4 ;
        RECT 2847.620000 3451.680000 2855.780000 3459.840000 ;
    END
    PORT
      LAYER met4 ;
        RECT 2847.620000 0.000000 2855.780000 8.160000 ;
    END
    PORT
      LAYER met4 ;
        RECT 4.040000 3451.680000 12.200000 3459.840000 ;
    END
    PORT
      LAYER met4 ;
        RECT 4.040000 0.000000 12.200000 8.160000 ;
    END

# P/G power stripe data as pin
    PORT
      LAYER met4 ;
        RECT 2733.600000 4.080000 2736.960000 3455.760000 ;
        RECT 2461.600000 4.080000 2464.960000 3455.760000 ;
        RECT 2189.600000 4.080000 2192.960000 3455.760000 ;
        RECT 1917.600000 4.080000 1920.960000 3455.760000 ;
        RECT 1645.600000 4.080000 1648.960000 3455.760000 ;
        RECT 1373.600000 4.080000 1376.960000 3455.760000 ;
        RECT 1101.600000 4.080000 1104.960000 3455.760000 ;
        RECT 829.600000 4.080000 832.960000 3455.760000 ;
        RECT 557.600000 4.080000 560.960000 3455.760000 ;
        RECT 285.600000 4.080000 288.960000 3455.760000 ;
        RECT 2847.620000 0.000000 2855.780000 3459.840000 ;
        RECT 4.040000 0.000000 12.200000 3459.840000 ;
      LAYER met5 ;
        RECT 0.000000 4.080000 2859.820000 12.240000 ;
        RECT 0.000000 3447.600000 2859.820000 3455.760000 ;
    END
# end of P/G power stripe data as pin

  END vssd1
  PIN vccd1
    DIRECTION INOUT ;
    USE POWER ;
    PORT
      LAYER met5 ;
        RECT 2851.660000 3435.360000 2859.820000 3443.520000 ;
    END
    PORT
      LAYER met5 ;
        RECT 0.000000 3435.360000 8.160000 3443.520000 ;
    END
    PORT
      LAYER met5 ;
        RECT 2851.660000 16.320000 2859.820000 24.480000 ;
    END
    PORT
      LAYER met5 ;
        RECT 0.000000 16.320000 8.160000 24.480000 ;
    END
    PORT
      LAYER met4 ;
        RECT 2835.380000 3451.680000 2843.540000 3459.840000 ;
    END
    PORT
      LAYER met4 ;
        RECT 2835.380000 0.000000 2843.540000 8.160000 ;
    END
    PORT
      LAYER met4 ;
        RECT 16.280000 3451.680000 24.440000 3459.840000 ;
    END
    PORT
      LAYER met4 ;
        RECT 16.280000 0.000000 24.440000 8.160000 ;
    END

# P/G power stripe data as pin
    PORT
      LAYER met4 ;
        RECT 2747.200000 16.320000 2750.560000 3443.520000 ;
        RECT 2475.200000 16.320000 2478.560000 3443.520000 ;
        RECT 2203.200000 16.320000 2206.560000 3443.520000 ;
        RECT 1931.200000 16.320000 1934.560000 3443.520000 ;
        RECT 1659.200000 16.320000 1662.560000 3443.520000 ;
        RECT 1387.200000 16.320000 1390.560000 3443.520000 ;
        RECT 1115.200000 16.320000 1118.560000 3443.520000 ;
        RECT 843.200000 16.320000 846.560000 3443.520000 ;
        RECT 571.200000 16.320000 574.560000 3443.520000 ;
        RECT 299.200000 16.320000 302.560000 3443.520000 ;
        RECT 27.200000 16.320000 30.560000 3443.520000 ;
        RECT 2835.380000 0.000000 2843.540000 3459.840000 ;
        RECT 16.280000 0.000000 24.440000 3459.840000 ;
      LAYER met5 ;
        RECT 0.000000 16.320000 2859.820000 24.480000 ;
        RECT 0.000000 3435.360000 2859.820000 3443.520000 ;
    END
# end of P/G power stripe data as pin

  END vccd1
  OBS
    LAYER li1 ;
      RECT 0.000000 0.000000 2859.820000 3459.840000 ;
    LAYER met1 ;
      RECT 0.000000 0.000000 2859.820000 3459.840000 ;
    LAYER met2 ;
      RECT 0.000000 0.000000 2859.820000 3459.840000 ;
    LAYER met3 ;
      RECT 0.000000 0.000000 2859.820000 3459.840000 ;
    LAYER met4 ;
      RECT 0.000000 0.000000 2859.820000 3459.840000 ;
    LAYER met5 ;
      RECT 0.000000 0.000000 2859.820000 3459.840000 ;
  END
END user_proj_example

END LIBRARY
